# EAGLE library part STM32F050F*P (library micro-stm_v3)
ARM 32-bit Cortex™-M0 CPU 48 MHz maximum frequency 16to 32 Kbytes of Flash memory 4 kbytes of SRAM 15 GPIOs 2.0 to 3.6 V application supply

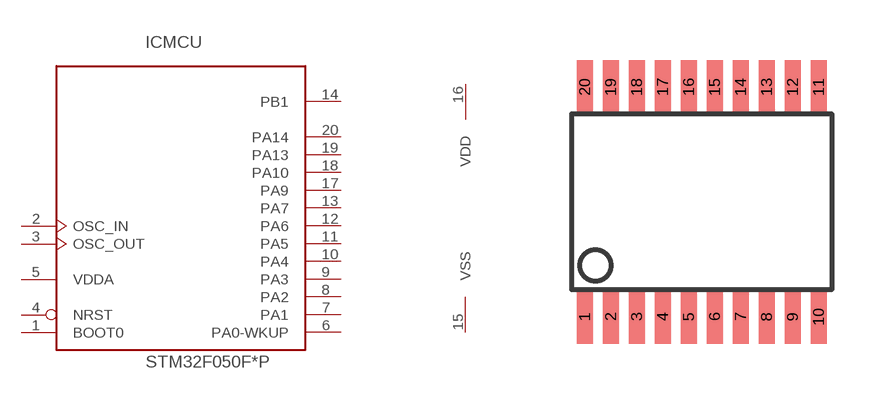
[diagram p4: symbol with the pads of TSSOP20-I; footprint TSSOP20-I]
Designator prefix IC; gates MCU=STM32_20PIN_TYP1 PWR=PWR_VDD1_VSS1

## STM32F050F4P, STM32F050F6P  [TSSOP20-I]
1  MCU:BOOT0  in
2  MCU:OSC_IN
3  MCU:OSC_OUT
4  MCU:NRST
5  MCU:VDDA  pwr
6  MCU:PA0-WKUP
7  MCU:PA1
8  MCU:PA2
9  MCU:PA3
10  MCU:PA4
11  MCU:PA5
12  MCU:PA6
13  MCU:PA7
14  MCU:PB1
15  PWR:VSS  pwr
16  PWR:VDD  pwr
17  MCU:PA9
18  MCU:PA10
19  MCU:PA13
20  MCU:PA14

## Footprint TSSOP20-I (pad centres in mm)
TSSOP20-I 20-pin thin shrink small outline package
smd 0.4 x 1.35: 1 -2.925,-2.875; 2 -2.275,-2.875; 3 -1.625,-2.875; 4 -0.975,-2.875; 5 -0.325,-2.875; 6 0.325,-2.875; 7 0.975,-2.875; 8 1.625,-2.875; 9 2.275,-2.875; 10 2.925,-2.875; 11 2.925,2.875; 12 2.275,2.875; 13 1.625,2.875; 14 0.975,2.875; 15 0.325,2.875; 16 -0.325,2.875; 17 -0.975,2.875; 18 -1.625,2.875; 19 -2.275,2.875; 20 -2.925,2.875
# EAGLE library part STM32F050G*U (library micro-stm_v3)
ARM 32-bit Cortex™-M0 CPU 48 MHz maximum frequency 16 to 32 Kbytes of Flash memory 4 kbytes of SRAM 23 GPIOs 2.0 to 3.6 V application supply

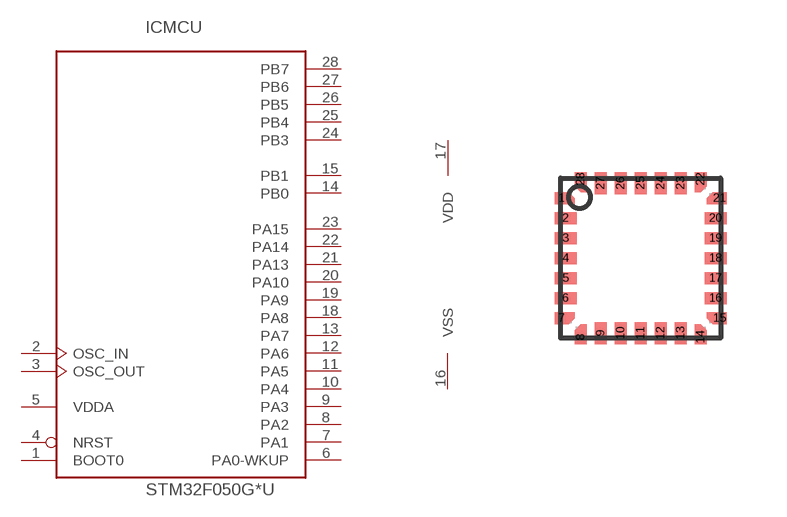
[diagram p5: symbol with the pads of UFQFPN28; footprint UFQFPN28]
Designator prefix IC; gates MCU=STM32_28PIN_TYP1 PWR=PWR_VDD1_VSS1

## STM32F050G4U, STM32F050G6U  [UFQFPN28]
1  MCU:BOOT0  in
2  MCU:OSC_IN
3  MCU:OSC_OUT
4  MCU:NRST
5  MCU:VDDA  pwr
6  MCU:PA0-WKUP
7  MCU:PA1
8  MCU:PA2
9  MCU:PA3
10  MCU:PA4
11  MCU:PA5
12  MCU:PA6
13  MCU:PA7
14  MCU:PB0
15  MCU:PB1
16  PWR:VSS  pwr
17  PWR:VDD  pwr
18  MCU:PA8
19  MCU:PA9
20  MCU:PA10
21  MCU:PA13
22  MCU:PA14
23  MCU:PA15
24  MCU:PB3
25  MCU:PB4
26  MCU:PB5
27  MCU:PB6
28  MCU:PB7

## Footprint UFQFPN28 (pad centres in mm)
UFQFPN28 4 x 4 mm, 28-pin ultra thin fine pitch quad flat no-lead package
smd 0.35 x 0.3: 1 -1.975,1.5; 7 -1.975,-1.5; 15 1.975,-1.5; 21 1.975,1.5
smd 0.55 x 0.3: 2 -1.875,1; 3 -1.875,0.5; 4 -1.875,0; 5 -1.875,-0.5; 6 -1.875,-1; 16 1.875,-1; 17 1.875,-0.5; 18 1.875,0; 19 1.875,0.5; 20 1.875,1
smd 0.3 x 0.35: 8 -1.5,-1.975; 14 1.5,-1.975; 22 1.5,1.975; 28 -1.5,1.975
smd 0.3 x 0.55: 9 -1,-1.875; 10 -0.5,-1.875; 11 0,-1.875; 12 0.5,-1.875; 13 1,-1.875; 23 1,1.875; 24 0.5,1.875; 25 0,1.875; 26 -0.5,1.875; 27 -1,1.875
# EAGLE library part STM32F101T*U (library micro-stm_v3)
ARM 32-bit Cortex™-M3 CPU 36 MHz maximum frequency 16 to 128 Kbytes of Flash memory 4 to 16 kbytes of SRAM 26 GPIOs 2.0 to 3.6 V application supply

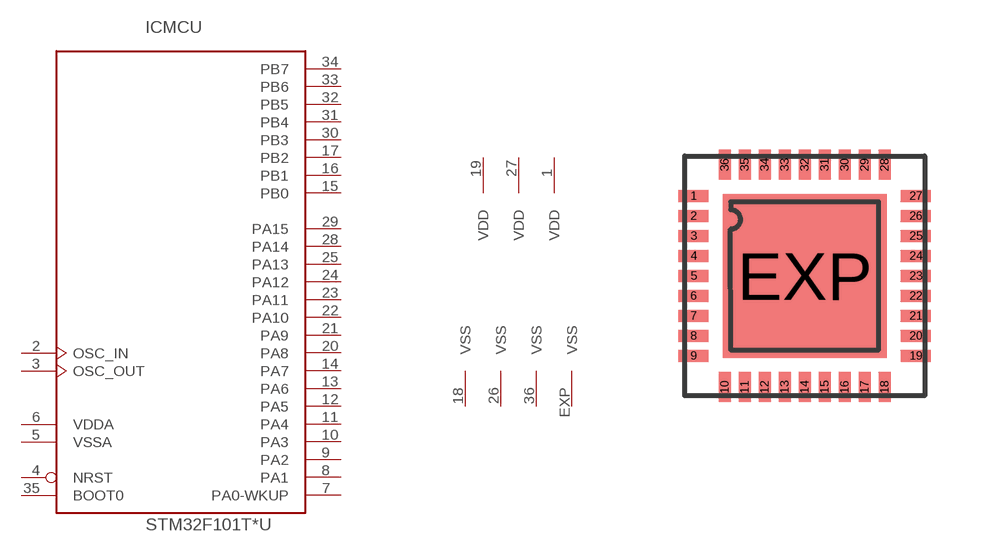
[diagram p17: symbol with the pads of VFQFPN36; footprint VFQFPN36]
Designator prefix IC; gates MCU=STM32_36PIN_TYP1 PWR=PWR_VDD3_VSS4

## STM32F101T4U, STM32F101T6U, STM32F101T8U, STM32F101TBU  [VFQFPN36]
1  PWR:VDD  pwr
2  MCU:OSC_IN
3  MCU:OSC_OUT
4  MCU:NRST
5  MCU:VSSA  pwr
6  MCU:VDDA  pwr
7  MCU:PA0-WKUP
8  MCU:PA1
9  MCU:PA2
10  MCU:PA3
11  MCU:PA4
12  MCU:PA5
13  MCU:PA6
14  MCU:PA7
15  MCU:PB0
16  MCU:PB1
17  MCU:PB2
18  PWR:VSS  pwr
19  PWR:VDD  pwr
20  MCU:PA8
21  MCU:PA9
22  MCU:PA10
23  MCU:PA11
24  MCU:PA12
25  MCU:PA13
26  PWR:VSS  pwr
27  PWR:VDD  pwr
28  MCU:PA14
29  MCU:PA15
30  MCU:PB3
31  MCU:PB4
32  MCU:PB5
33  MCU:PB6
34  MCU:PB7
35  MCU:BOOT0  in
36  PWR:VSS  pwr
EXP  PWR:VSS  pwr

## Footprint VFQFPN36 (pad centres in mm)
VFQFPN36 6 x 6 mm, 36-pin very thin 0.5 mm pitch quad flat no-lead package
smd 0.75 x 0.3: 1 -2.78,2; 2 -2.78,1.5; 3 -2.78,1; 4 -2.78,0.5; 5 -2.78,0; 6 -2.78,-0.5; 7 -2.78,-1; 8 -2.78,-1.5; 9 -2.78,-2; 19 2.78,-2; 20 2.78,-1.5; 21 2.78,-1; 22 2.78,-0.5; 23 2.78,0; 24 2.78,0.5; 25 2.78,1; 26 2.78,1.5; 27 2.78,2
smd 0.3 x 0.75: 10 -2,-2.78; 11 -1.5,-2.78; 12 -1,-2.78; 13 -0.5,-2.78; 14 0,-2.78; 15 0.5,-2.78; 16 1,-2.78; 17 1.5,-2.78; 18 2,-2.78; 28 2,2.78; 29 1.5,2.78; 30 1,2.78; 31 0.5,2.78; 32 0,2.78; 33 -0.5,2.78; 34 -1,2.78; 35 -1.5,2.78; 36 -2,2.78
smd 4.1 x 4.1: EXP 0,0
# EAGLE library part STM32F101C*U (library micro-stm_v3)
ARM 32-bit Cortex™-M3 CPU 36 MHz maximum frequency 16 to 128 Kbytes of Flash memory 4 to 16 kbytes of SRAM 37 GPIOs 2.0 to 3.6 V application supply

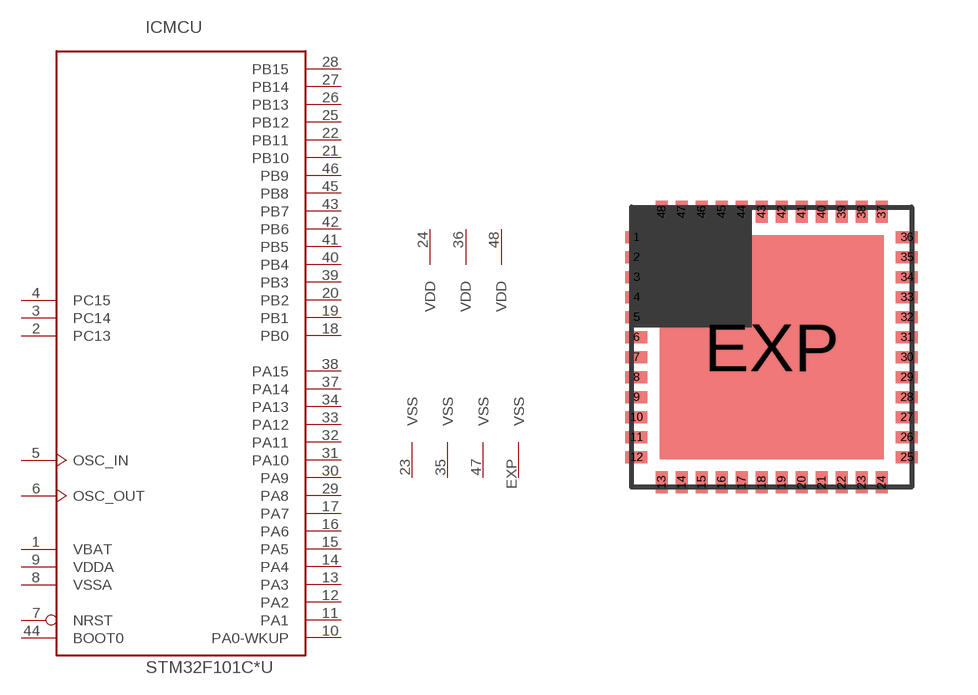
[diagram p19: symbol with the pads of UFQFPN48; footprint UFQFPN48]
Designator prefix IC; gates MCU=STM32_48PIN_TYP3 PWR=PWR_VDD3_VSS4

## STM32F101C4U, STM32F101C6U, STM32F101C8U, STM32F101CBU  [UFQFPN48]
1  MCU:VBAT  pwr
2  MCU:PC13
3  MCU:PC14
4  MCU:PC15
5  MCU:OSC_IN
6  MCU:OSC_OUT
7  MCU:NRST
8  MCU:VSSA  pwr
9  MCU:VDDA  pwr
10  MCU:PA0-WKUP
11  MCU:PA1
12  MCU:PA2
13  MCU:PA3
14  MCU:PA4
15  MCU:PA5
16  MCU:PA6
17  MCU:PA7
18  MCU:PB0
19  MCU:PB1
20  MCU:PB2
21  MCU:PB10
22  MCU:PB11
23  PWR:VSS  pwr
24  PWR:VDD  pwr
25  MCU:PB12
26  MCU:PB13
27  MCU:PB14
28  MCU:PB15
29  MCU:PA8
30  MCU:PA9
31  MCU:PA10
32  MCU:PA11
33  MCU:PA12
34  MCU:PA13
35  PWR:VSS  pwr
36  PWR:VDD  pwr
37  MCU:PA14
38  MCU:PA15
39  MCU:PB3
40  MCU:PB4
41  MCU:PB5
42  MCU:PB6
43  MCU:PB7
44  MCU:BOOT0  in
45  MCU:PB8
46  MCU:PB9
47  PWR:VSS  pwr
48  PWR:VDD  pwr
EXP  PWR:VSS  pwr

## Footprint UFQFPN48 (pad centres in mm)
UFQFPN48 7 x 7 mm, 48-pin ultra thin 0.5 mm pitch quad flat no-lead package
smd 0.55 x 0.3: 1 -3.38,2.75; 2 -3.38,2.25; 3 -3.38,1.75; 4 -3.38,1.25; 5 -3.38,0.75; 6 -3.38,0.25; 7 -3.38,-0.25; 8 -3.38,-0.75; 9 -3.38,-1.25; 10 -3.38,-1.75; 11 -3.38,-2.25; 12 -3.38,-2.75; 25 3.38,-2.75; 26 3.38,-2.25; 27 3.38,-1.75; 28 3.38,-1.25; 29 3.38,-0.75; 30 3.38,-0.25; 31 3.38,0.25; 32 3.38,0.75; 33 3.38,1.25; 34 3.38,1.75; 35 3.38,2.25; 36 3.38,2.75
smd 0.3 x 0.55: 13 -2.75,-3.38; 14 -2.25,-3.38; 15 -1.75,-3.38; 16 -1.25,-3.38; 17 -0.75,-3.38; 18 -0.25,-3.38; 19 0.25,-3.38; 20 0.75,-3.38; 21 1.25,-3.38; 22 1.75,-3.38; 23 2.25,-3.38; 24 2.75,-3.38; 37 2.75,3.38; 38 2.25,3.38; 39 1.75,3.38; 40 1.25,3.38; 41 0.75,3.38; 42 0.25,3.38; 43 -0.25,3.38; 44 -0.75,3.38; 45 -1.25,3.38; 46 -1.75,3.38; 47 -2.25,3.38; 48 -2.75,3.38
smd 5.6 x 5.6: EXP 0,0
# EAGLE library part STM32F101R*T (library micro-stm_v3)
ARM 32-bit Cortex™-M3 CPU 36 MHz maximum frequency 16 to 1024 Kbytes of Flash memory 4 to 80 kbytes of SRAM 51 GPIOs 2.0 to 3.6 V application supply

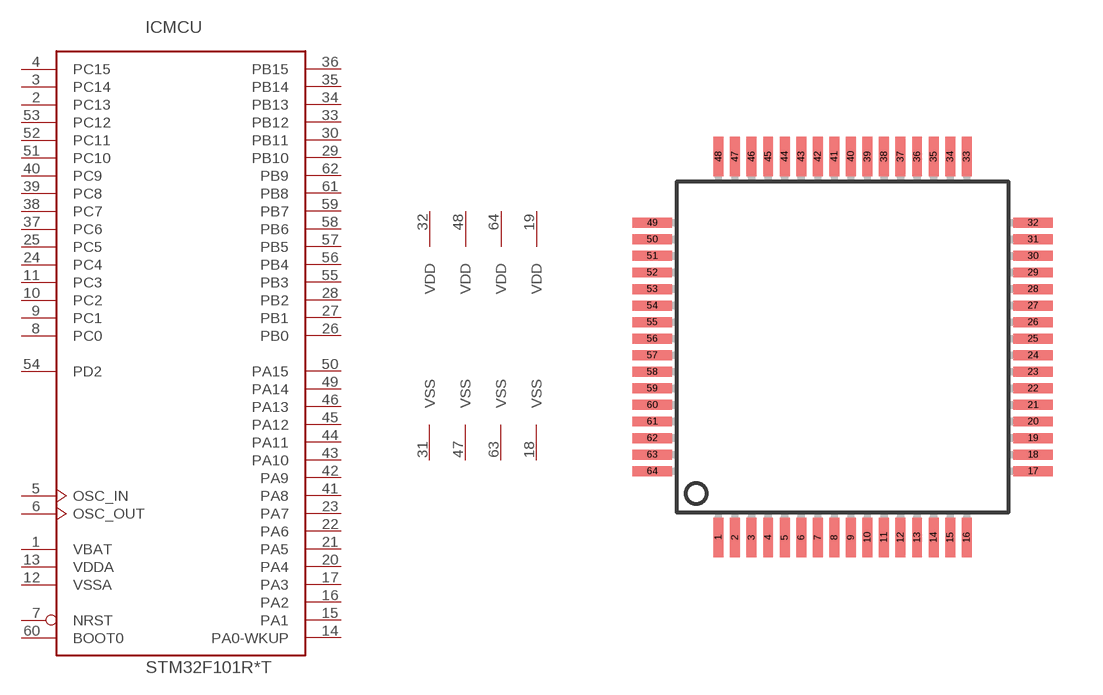
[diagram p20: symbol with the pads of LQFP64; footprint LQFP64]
Designator prefix IC; gates MCU=STM32_64PIN_TYP3 PWR=PWR_VDD4_VSS4

## STM32F101R4T, STM32F101R6T, STM32F101R8T, STM32F101RBT, STM32F101RCT, STM32F101RDT, STM32F101RET, STM32F101RFT, STM32F101RGT  [LQFP64]
1  MCU:VBAT  pwr
2  MCU:PC13
3  MCU:PC14
4  MCU:PC15
5  MCU:OSC_IN
6  MCU:OSC_OUT
7  MCU:NRST
8  MCU:PC0
9  MCU:PC1
10  MCU:PC2
11  MCU:PC3
12  MCU:VSSA  pwr
13  MCU:VDDA  pwr
14  MCU:PA0-WKUP
15  MCU:PA1
16  MCU:PA2
17  MCU:PA3
18  PWR:VSS  pwr
19  PWR:VDD  pwr
20  MCU:PA4
21  MCU:PA5
22  MCU:PA6
23  MCU:PA7
24  MCU:PC4
25  MCU:PC5
26  MCU:PB0
27  MCU:PB1
28  MCU:PB2
29  MCU:PB10
30  MCU:PB11
31  PWR:VSS  pwr
32  PWR:VDD  pwr
33  MCU:PB12
34  MCU:PB13
35  MCU:PB14
36  MCU:PB15
37  MCU:PC6
38  MCU:PC7
39  MCU:PC8
40  MCU:PC9
41  MCU:PA8
42  MCU:PA9
43  MCU:PA10
44  MCU:PA11
45  MCU:PA12
46  MCU:PA13
47  PWR:VSS  pwr
48  PWR:VDD  pwr
49  MCU:PA14
50  MCU:PA15
51  MCU:PC10
52  MCU:PC11
53  MCU:PC12
54  MCU:PD2
55  MCU:PB3
56  MCU:PB4
57  MCU:PB5
58  MCU:PB6
59  MCU:PB7
60  MCU:BOOT0  in
61  MCU:PB8
62  MCU:PB9
63  PWR:VSS  pwr
64  PWR:VDD  pwr

## Footprint LQFP64 (pad centres in mm)
LQFP64 10 x 10 mm, 64-pin low-profile quad flat package
smd 0.3 x 1.2: 1 -3.75,-5.75; 2 -3.25,-5.75; 3 -2.75,-5.75; 4 -2.25,-5.75; 5 -1.75,-5.75; 6 -1.25,-5.75; 7 -0.75,-5.75; 8 -0.25,-5.75; 9 0.25,-5.75; 10 0.75,-5.75; 11 1.25,-5.75; 12 1.75,-5.75; 13 2.25,-5.75; 14 2.75,-5.75; 15 3.25,-5.75; 16 3.75,-5.75; 33 3.75,5.75; 34 3.25,5.75; 35 2.75,5.75; 36 2.25,5.75; 37 1.75,5.75; 38 1.25,5.75; 39 0.75,5.75; 40 0.25,5.75; 41 -0.25,5.75; 42 -0.75,5.75; 43 -1.25,5.75; 44 -1.75,5.75; 45 -2.25,5.75; 46 -2.75,5.75; 47 -3.25,5.75; 48 -3.75,5.75
smd 1.2 x 0.3: 17 5.75,-3.75; 18 5.75,-3.25; 19 5.75,-2.75; 20 5.75,-2.25; 21 5.75,-1.75; 22 5.75,-1.25; 23 5.75,-0.75; 24 5.75,-0.25; 25 5.75,0.25; 26 5.75,0.75; 27 5.75,1.25; 28 5.75,1.75; 29 5.75,2.25; 30 5.75,2.75; 31 5.75,3.25; 32 5.75,3.75; 49 -5.75,3.75; 50 -5.75,3.25; 51 -5.75,2.75; 52 -5.75,2.25; 53 -5.75,1.75; 54 -5.75,1.25; 55 -5.75,0.75; 56 -5.75,0.25; 57 -5.75,-0.25; 58 -5.75,-0.75; 59 -5.75,-1.25; 60 -5.75,-1.75; 61 -5.75,-2.25; 62 -5.75,-2.75; 63 -5.75,-3.25; 64 -5.75,-3.75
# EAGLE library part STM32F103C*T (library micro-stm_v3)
ARM 32-bit Cortex™-M3 CPU 72 MHz maximum frequency 16 to 128 Kbytes of Flash memory 6 to 20 kbytes of SRAM 37 GPIOs 2.0 to 3.6 V application supply

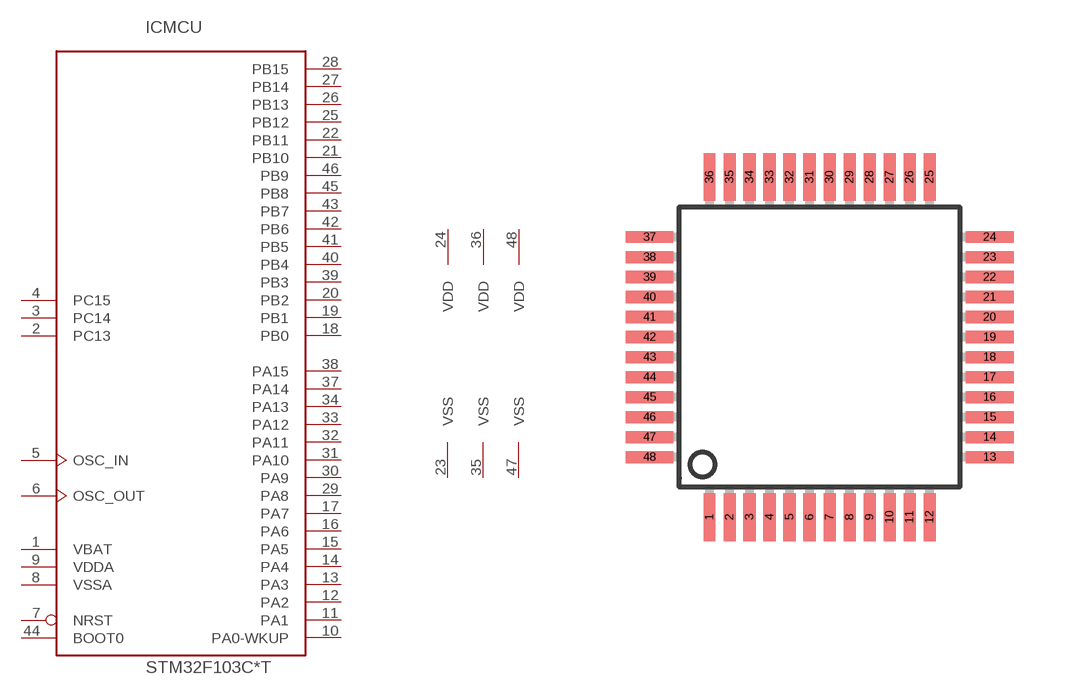
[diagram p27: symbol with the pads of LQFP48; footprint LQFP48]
Designator prefix IC; gates MCU=STM32_48PIN_TYP3 PWR=PWR_VDD3_VSS3

## STM32F103C4T, STM32F103C6T, STM32F103C8T, STM32F103CBT  [LQFP48]
1  MCU:VBAT  pwr
2  MCU:PC13
3  MCU:PC14
4  MCU:PC15
5  MCU:OSC_IN
6  MCU:OSC_OUT
7  MCU:NRST
8  MCU:VSSA  pwr
9  MCU:VDDA  pwr
10  MCU:PA0-WKUP
11  MCU:PA1
12  MCU:PA2
13  MCU:PA3
14  MCU:PA4
15  MCU:PA5
16  MCU:PA6
17  MCU:PA7
18  MCU:PB0
19  MCU:PB1
20  MCU:PB2
21  MCU:PB10
22  MCU:PB11
23  PWR:VSS  pwr
24  PWR:VDD  pwr
25  MCU:PB12
26  MCU:PB13
27  MCU:PB14
28  MCU:PB15
29  MCU:PA8
30  MCU:PA9
31  MCU:PA10
32  MCU:PA11
33  MCU:PA12
34  MCU:PA13
35  PWR:VSS  pwr
36  PWR:VDD  pwr
37  MCU:PA14
38  MCU:PA15
39  MCU:PB3
40  MCU:PB4
41  MCU:PB5
42  MCU:PB6
43  MCU:PB7
44  MCU:BOOT0  in
45  MCU:PB8
46  MCU:PB9
47  PWR:VSS  pwr
48  PWR:VDD  pwr

## Footprint LQFP48 (pad centres in mm)
LQFP48 7 x 7 mm, 48-pin low-profile quad flat package
smd 0.3 x 1.2: 1 -2.75,-4.25; 2 -2.25,-4.25; 3 -1.75,-4.25; 4 -1.25,-4.25; 5 -0.75,-4.25; 6 -0.25,-4.25; 7 0.25,-4.25; 8 0.75,-4.25; 9 1.25,-4.25; 10 1.75,-4.25; 11 2.25,-4.25; 12 2.75,-4.25; 25 2.75,4.25; 26 2.25,4.25; 27 1.75,4.25; 28 1.25,4.25; 29 0.75,4.25; 30 0.25,4.25; 31 -0.25,4.25; 32 -0.75,4.25; 33 -1.25,4.25; 34 -1.75,4.25; 35 -2.25,4.25; 36 -2.75,4.25
smd 1.2 x 0.3: 13 4.25,-2.75; 14 4.25,-2.25; 15 4.25,-1.75; 16 4.25,-1.25; 17 4.25,-0.75; 18 4.25,-0.25; 19 4.25,0.25; 20 4.25,0.75; 21 4.25,1.25; 22 4.25,1.75; 23 4.25,2.25; 24 4.25,2.75; 37 -4.25,2.75; 38 -4.25,2.25; 39 -4.25,1.75; 40 -4.25,1.25; 41 -4.25,0.75; 42 -4.25,0.25; 43 -4.25,-0.25; 44 -4.25,-0.75; 45 -4.25,-1.25; 46 -4.25,-1.75; 47 -4.25,-2.25; 48 -4.25,-2.75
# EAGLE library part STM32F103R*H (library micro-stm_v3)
ARM 32-bit Cortex™-M3 CPU 72 MHz maximum frequency 16 to 128 Kbytes of Flash memory 6 to 20 kbytes of SRAM 51 GPIOs 2.0 to 3.6 V application supply

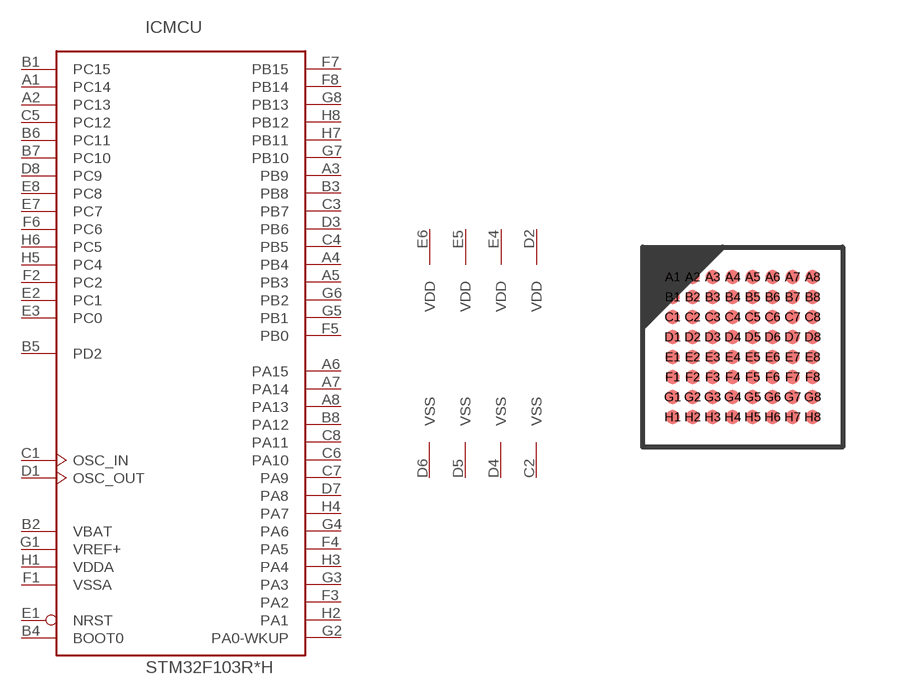
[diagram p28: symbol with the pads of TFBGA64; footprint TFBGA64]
Designator prefix IC; gates MCU=STM32_64PIN_TYP4 PWR=PWR_VDD4_VSS4

## STM32F103R4H, STM32F103R6H, STM32F103R8H, STM32F103RBH  [TFBGA64]
A1  MCU:PC14
A2  MCU:PC13
A3  MCU:PB9
A4  MCU:PB4
A5  MCU:PB3
A6  MCU:PA15
A7  MCU:PA14
A8  MCU:PA13
B1  MCU:PC15
B2  MCU:VBAT  pwr
B3  MCU:PB8
B4  MCU:BOOT0  in
B5  MCU:PD2
B6  MCU:PC11
B7  MCU:PC10
B8  MCU:PA12
C1  MCU:OSC_IN
C2  PWR:VSS  pwr
C3  MCU:PB7
C4  MCU:PB5
C5  MCU:PC12
C6  MCU:PA10
C7  MCU:PA9
C8  MCU:PA11
D1  MCU:OSC_OUT
D2  PWR:VDD  pwr
D3  MCU:PB6
D4  PWR:VSS  pwr
D5  PWR:VSS  pwr
D6  PWR:VSS  pwr
D7  MCU:PA8
D8  MCU:PC9
E1  MCU:NRST
E2  MCU:PC1
E3  MCU:PC0
E4  PWR:VDD  pwr
E5  PWR:VDD  pwr
E6  PWR:VDD  pwr
E7  MCU:PC7
E8  MCU:PC8
F1  MCU:VSSA  pwr
F2  MCU:PC2
F3  MCU:PA2
F4  MCU:PA5
F5  MCU:PB0
F6  MCU:PC6
F7  MCU:PB15
F8  MCU:PB14
G1  MCU:VREF+  pwr
G2  MCU:PA0-WKUP
G3  MCU:PA3
G4  MCU:PA6
G5  MCU:PB1
G6  MCU:PB2
G7  MCU:PB10
G8  MCU:PB13
H1  MCU:VDDA  pwr
H2  MCU:PA1
H3  MCU:PA4
H4  MCU:PA7
H5  MCU:PC4
H6  MCU:PC5
H7  MCU:PB11
H8  MCU:PB12

## Footprint TFBGA64 (pad centres in mm)
TFBGA64 5 x 5 mm, 8 x 8-pin thin 0.5 mm pitch ball grid array package
smd 0.35 x 0.35: A1 -1.75,1.75; A2 -1.25,1.75; A3 -0.75,1.75; A4 -0.25,1.75; A5 0.25,1.75; A6 0.75,1.75; A7 1.25,1.75; A8 1.75,1.75; B1 -1.75,1.25; B2 -1.25,1.25; B3 -0.75,1.25; B4 -0.25,1.25; B5 0.25,1.25; B6 0.75,1.25; B7 1.25,1.25; B8 1.75,1.25; C1 -1.75,0.75; C2 -1.25,0.75; C3 -0.75,0.75; C4 -0.25,0.75; C5 0.25,0.75; C6 0.75,0.75; C7 1.25,0.75; C8 1.75,0.75; D1 -1.75,0.25; D2 -1.25,0.25; D3 -0.75,0.25; D4 -0.25,0.25; D5 0.25,0.25; D6 0.75,0.25; D7 1.25,0.25; D8 1.75,0.25; E1 -1.75,-0.25; E2 -1.25,-0.25; E3 -0.75,-0.25; E4 -0.25,-0.25; E5 0.25,-0.25; E6 0.75,-0.25; E7 1.25,-0.25; E8 1.75,-0.25; F1 -1.75,-0.75; F2 -1.25,-0.75; F3 -0.75,-0.75; F4 -0.25,-0.75; F5 0.25,-0.75; F6 0.75,-0.75; F7 1.25,-0.75; F8 1.75,-0.75; G1 -1.75,-1.25; G2 -1.25,-1.25; G3 -0.75,-1.25; G4 -0.25,-1.25; G5 0.25,-1.25; G6 0.75,-1.25; G7 1.25,-1.25; G8 1.75,-1.25; H1 -1.75,-1.75; H2 -1.25,-1.75; H3 -0.75,-1.75; H4 -0.25,-1.75; H5 0.25,-1.75; H6 0.75,-1.75; H7 1.25,-1.75; H8 1.75,-1.75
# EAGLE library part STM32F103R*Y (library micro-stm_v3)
ARM 32-bit Cortex™-M3 CPU 72 MHz maximum frequency 256 to 512 Kbytes of Flash memory 64 kbytes of SRAM 51 GPIOs 2.0 to 3.6 V application supply

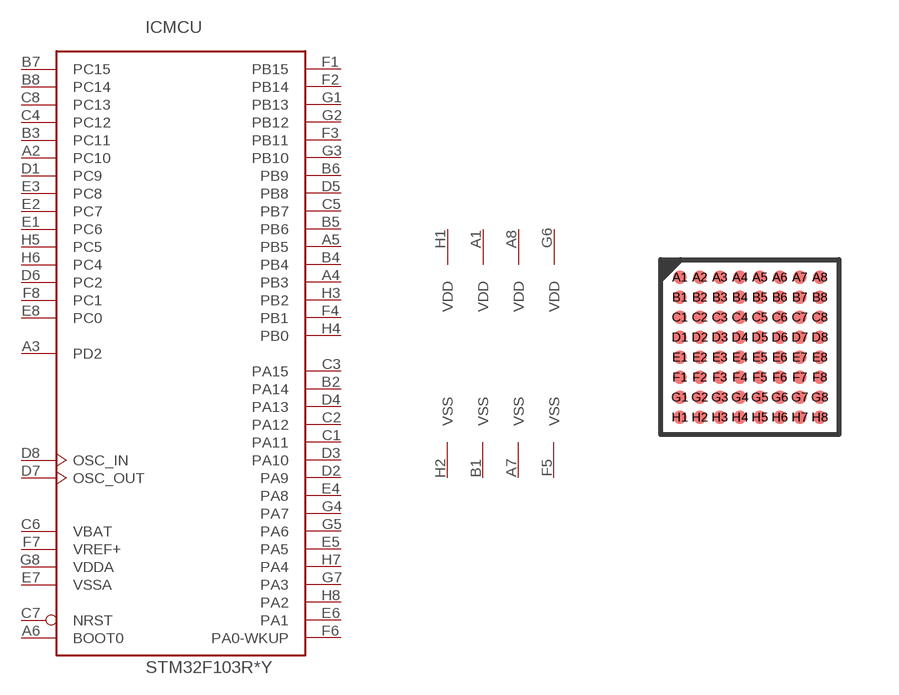
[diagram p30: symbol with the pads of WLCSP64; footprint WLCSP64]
Designator prefix IC; gates MCU=STM32_64PIN_TYP4 PWR=PWR_VDD4_VSS4

## STM32F103RCY, STM32F103RDY, STM32F103REY  [WLCSP64]
A1  PWR:VDD  pwr
A2  MCU:PC10
A3  MCU:PD2
A4  MCU:PB3
A5  MCU:PB5
A6  MCU:BOOT0  in
A7  PWR:VSS  pwr
A8  PWR:VDD  pwr
B1  PWR:VSS  pwr
B2  MCU:PA14
B3  MCU:PC11
B4  MCU:PB4
B5  MCU:PB6
B6  MCU:PB9
B7  MCU:PC15
B8  MCU:PC14
C1  MCU:PA11
C2  MCU:PA12
C3  MCU:PA15
C4  MCU:PC12
C5  MCU:PB7
C6  MCU:VBAT  pwr
C7  MCU:NRST
C8  MCU:PC13
D1  MCU:PC9
D2  MCU:PA9
D3  MCU:PA10
D4  MCU:PA13
D5  MCU:PB8
D6  MCU:PC2
D7  MCU:OSC_OUT
D8  MCU:OSC_IN
E1  MCU:PC6
E2  MCU:PC7
E3  MCU:PC8
E4  MCU:PA8
E5  MCU:PA5
E6  MCU:PA1
E7  MCU:VSSA  pwr
E8  MCU:PC0
F1  MCU:PB15
F2  MCU:PB14
F3  MCU:PB11
F4  MCU:PB1
F5  PWR:VSS  pwr
F6  MCU:PA0-WKUP
F7  MCU:VREF+  pwr
F8  MCU:PC1
G1  MCU:PB13
G2  MCU:PB12
G3  MCU:PB10
G4  MCU:PA7
G5  MCU:PA6
G6  PWR:VDD  pwr
G7  MCU:PA3
G8  MCU:VDDA  pwr
H1  PWR:VDD  pwr
H2  PWR:VSS  pwr
H3  MCU:PB2
H4  MCU:PB0
H5  MCU:PC5
H6  MCU:PC4
H7  MCU:PA4
H8  MCU:PA2

## Footprint WLCSP64 (pad centres in mm)
WLCSP64 4.466 x 4.395 mm, 8 x 8-pin 0.5 mm pitch wafer-level chip-scale package
smd 0.34 x 0.34: A1 -1.75,1.75; A2 -1.25,1.75; A3 -0.75,1.75; A4 -0.25,1.75; A5 0.25,1.75; A6 0.75,1.75; A7 1.25,1.75; A8 1.75,1.75; B1 -1.75,1.25; B2 -1.25,1.25; B3 -0.75,1.25; B4 -0.25,1.25; B5 0.25,1.25; B6 0.75,1.25; B7 1.25,1.25; B8 1.75,1.25; C1 -1.75,0.75; C2 -1.25,0.75; C3 -0.75,0.75; C4 -0.25,0.75; C5 0.25,0.75; C6 0.75,0.75; C7 1.25,0.75; C8 1.75,0.75; D1 -1.75,0.25; D2 -1.25,0.25; D3 -0.75,0.25; D4 -0.25,0.25; D5 0.25,0.25; D6 0.75,0.25; D7 1.25,0.25; D8 1.75,0.25; E1 -1.75,-0.25; E2 -1.25,-0.25; E3 -0.75,-0.25; E4 -0.25,-0.25; E5 0.25,-0.25; E6 0.75,-0.25; E7 1.25,-0.25; E8 1.75,-0.25; F1 -1.75,-0.75; F2 -1.25,-0.75; F3 -0.75,-0.75; F4 -0.25,-0.75; F5 0.25,-0.75; F6 0.75,-0.75; F7 1.25,-0.75; F8 1.75,-0.75; G1 -1.75,-1.25; G2 -1.25,-1.25; G3 -0.75,-1.25; G4 -0.25,-1.25; G5 0.25,-1.25; G6 0.75,-1.25; G7 1.25,-1.25; G8 1.75,-1.25; H1 -1.75,-1.75; H2 -1.25,-1.75; H3 -0.75,-1.75; H4 -0.25,-1.75; H5 0.25,-1.75; H6 0.75,-1.75; H7 1.25,-1.75; H8 1.75,-1.75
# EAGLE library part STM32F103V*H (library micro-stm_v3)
ARM 32-bit Cortex™-M3 CPU 72 MHz maximum frequency 64 to 512 Kbytes of Flash memory 20 to 64 kbytes of SRAM 80 GPIOs 2.0 to 3.6 V application supply

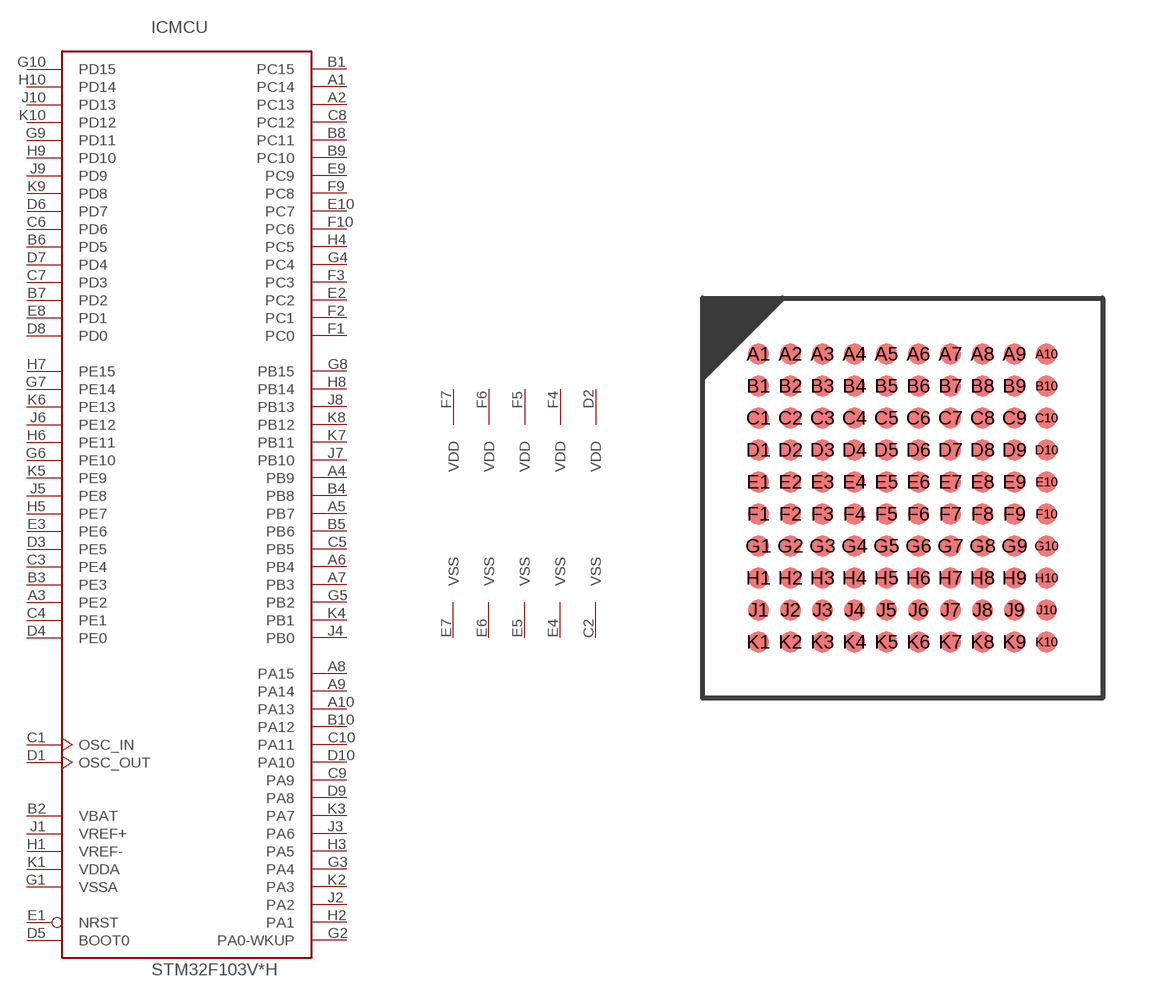
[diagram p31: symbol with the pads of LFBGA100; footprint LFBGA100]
Designator prefix IC; gates MCU=STM32_100PIN_TYP1 PWR=PWR_VDD5_VSS5

## STM32F103V8H, STM32F103VBH, STM32F103VCH, STM32F103VDH, STM32F103VEH  [LFBGA100]
A1  MCU:PC14
A2  MCU:PC13
A3  MCU:PE2
A4  MCU:PB9
A5  MCU:PB7
A6  MCU:PB4
A7  MCU:PB3
A8  MCU:PA15
A9  MCU:PA14
A10  MCU:PA13
B1  MCU:PC15
B2  MCU:VBAT  pwr
B3  MCU:PE3
B4  MCU:PB8
B5  MCU:PB6
B6  MCU:PD5
B7  MCU:PD2
B8  MCU:PC11
B9  MCU:PC10
B10  MCU:PA12
C1  MCU:OSC_IN
C2  PWR:VSS  pwr
C3  MCU:PE4
C4  MCU:PE1
C5  MCU:PB5
C6  MCU:PD6
C7  MCU:PD3
C8  MCU:PC12
C9  MCU:PA9
C10  MCU:PA11
D1  MCU:OSC_OUT
D2  PWR:VDD  pwr
D3  MCU:PE5
D4  MCU:PE0
D5  MCU:BOOT0  in
D6  MCU:PD7
D7  MCU:PD4
D8  MCU:PD0
D9  MCU:PA8
D10  MCU:PA10
E1  MCU:NRST
E2  MCU:PC2
E3  MCU:PE6
E4  PWR:VSS  pwr
E5  PWR:VSS  pwr
E6  PWR:VSS  pwr
E7  PWR:VSS  pwr
E8  MCU:PD1
E9  MCU:PC9
E10  MCU:PC7
F1  MCU:PC0
F2  MCU:PC1
F3  MCU:PC3
F4  PWR:VDD  pwr
F5  PWR:VDD  pwr
F6  PWR:VDD  pwr
F7  PWR:VDD  pwr
F9  MCU:PC8
F10  MCU:PC6
G1  MCU:VSSA  pwr
G2  MCU:PA0-WKUP
G3  MCU:PA4
G4  MCU:PC4
G5  MCU:PB2
G6  MCU:PE10
G7  MCU:PE14
G8  MCU:PB15
G9  MCU:PD11
G10  MCU:PD15
H1  MCU:VREF-  pwr
H2  MCU:PA1
H3  MCU:PA5
H4  MCU:PC5
H5  MCU:PE7
H6  MCU:PE11
H7  MCU:PE15
H8  MCU:PB14
H9  MCU:PD10
H10  MCU:PD14
J1  MCU:VREF+  pwr
J2  MCU:PA2
J3  MCU:PA6
J4  MCU:PB0
J5  MCU:PE8
J6  MCU:PE12
J7  MCU:PB10
J8  MCU:PB13
J9  MCU:PD9
J10  MCU:PD13
K1  MCU:VDDA  pwr
K2  MCU:PA3
K3  MCU:PA7
K4  MCU:PB1
K5  MCU:PE9
K6  MCU:PE13
K7  MCU:PB11
K8  MCU:PB12
K9  MCU:PD8
K10  MCU:PD12

## Footprint LFBGA100 (pad centres in mm)
LFBGA100 10 x 10 mm, 10 x 10-pin low profil 0.8 mm pitch ball grid array package
smd 0.52 x 0.52: A1 -3.6,3.6; A2 -2.8,3.6; A3 -2,3.6; A4 -1.2,3.6; A5 -0.4,3.6; A6 0.4,3.6; A7 1.2,3.6; A8 2,3.6; A9 2.8,3.6; A10 3.6,3.6; B1 -3.6,2.8; B2 -2.8,2.8; B3 -2,2.8; B4 -1.2,2.8; B5 -0.4,2.8; B6 0.4,2.8; B7 1.2,2.8; B8 2,2.8; B9 2.8,2.8; B10 3.6,2.8; C1 -3.6,2; C2 -2.8,2; C3 -2,2; C4 -1.2,2; C5 -0.4,2; C6 0.4,2; C7 1.2,2; C8 2,2; C9 2.8,2; C10 3.6,2; D1 -3.6,1.2; D2 -2.8,1.2; D3 -2,1.2; D4 -1.2,1.2; D5 -0.4,1.2; D6 0.4,1.2; D7 1.2,1.2; D8 2,1.2; D9 2.8,1.2; D10 3.6,1.2; E1 -3.6,0.4; E2 -2.8,0.4; E3 -2,0.4; E4 -1.2,0.4; E5 -0.4,0.4; E6 0.4,0.4; E7 1.2,0.4; E8 2,0.4; E9 2.8,0.4; E10 3.6,0.4; F1 -3.6,-0.4; F2 -2.8,-0.4; F3 -2,-0.4; F4 -1.2,-0.4; F5 -0.4,-0.4; F6 0.4,-0.4; F7 1.2,-0.4; F8 2,-0.4; F9 2.8,-0.4; F10 3.6,-0.4; G1 -3.6,-1.2; G2 -2.8,-1.2; G3 -2,-1.2; G4 -1.2,-1.2; G5 -0.4,-1.2; G6 0.4,-1.2; G7 1.2,-1.2; G8 2,-1.2; G9 2.8,-1.2; G10 3.6,-1.2; H1 -3.6,-2; H2 -2.8,-2; H3 -2,-2; H4 -1.2,-2; H5 -0.4,-2; H6 0.4,-2; H7 1.2,-2; H8 2,-2; H9 2.8,-2; H10 3.6,-2; J1 -3.6,-2.8; J2 -2.8,-2.8; J3 -2,-2.8; J4 -1.2,-2.8; J5 -0.4,-2.8; J6 0.4,-2.8; J7 1.2,-2.8; J8 2,-2.8; J9 2.8,-2.8; J10 3.6,-2.8; K1 -3.6,-3.6; K2 -2.8,-3.6; K3 -2,-3.6; K4 -1.2,-3.6; K5 -0.4,-3.6; K6 0.4,-3.6; K7 1.2,-3.6; K8 2,-3.6; K9 2.8,-3.6; K10 3.6,-3.6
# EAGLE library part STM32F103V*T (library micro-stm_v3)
ARM 32-bit Cortex™-M3 CPU 72 MHz maximum frequency 64 to 1028 Kbytes of Flash memory 20 to 96 kbytes of SRAM 80 GPIOs 2.0 to 3.6 V application supply

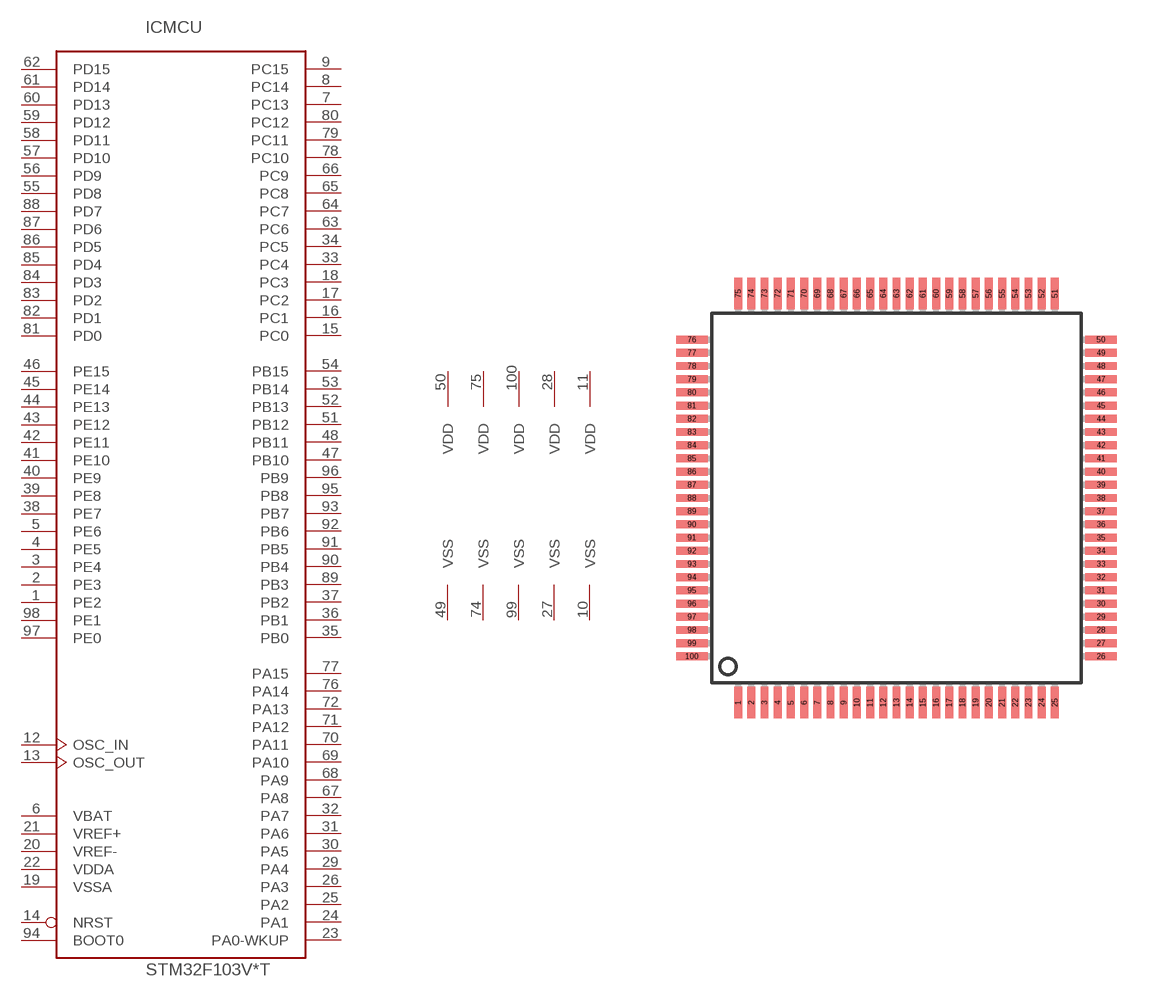
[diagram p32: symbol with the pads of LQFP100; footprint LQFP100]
Designator prefix IC; gates MCU=STM32_100PIN_TYP1 PWR=PWR_VDD5_VSS5

## STM32F103V8T, STM32F103VBT, STM32F103VCT, STM32F103VDT, STM32F103VET, STM32F103VFT, STM32F103VGT  [LQFP100]
1  MCU:PE2
2  MCU:PE3
3  MCU:PE4
4  MCU:PE5
5  MCU:PE6
6  MCU:VBAT  pwr
7  MCU:PC13
8  MCU:PC14
9  MCU:PC15
10  PWR:VSS  pwr
11  PWR:VDD  pwr
12  MCU:OSC_IN
13  MCU:OSC_OUT
14  MCU:NRST
15  MCU:PC0
16  MCU:PC1
17  MCU:PC2
18  MCU:PC3
19  MCU:VSSA  pwr
20  MCU:VREF-  pwr
21  MCU:VREF+  pwr
22  MCU:VDDA  pwr
23  MCU:PA0-WKUP
24  MCU:PA1
25  MCU:PA2
26  MCU:PA3
27  PWR:VSS  pwr
28  PWR:VDD  pwr
29  MCU:PA4
30  MCU:PA5
31  MCU:PA6
32  MCU:PA7
33  MCU:PC4
34  MCU:PC5
35  MCU:PB0
36  MCU:PB1
37  MCU:PB2
38  MCU:PE7
39  MCU:PE8
40  MCU:PE9
41  MCU:PE10
42  MCU:PE11
43  MCU:PE12
44  MCU:PE13
45  MCU:PE14
46  MCU:PE15
47  MCU:PB10
48  MCU:PB11
49  PWR:VSS  pwr
50  PWR:VDD  pwr
51  MCU:PB12
52  MCU:PB13
53  MCU:PB14
54  MCU:PB15
55  MCU:PD8
56  MCU:PD9
57  MCU:PD10
58  MCU:PD11
59  MCU:PD12
60  MCU:PD13
61  MCU:PD14
62  MCU:PD15
63  MCU:PC6
64  MCU:PC7
65  MCU:PC8
66  MCU:PC9
67  MCU:PA8
68  MCU:PA9
69  MCU:PA10
70  MCU:PA11
71  MCU:PA12
72  MCU:PA13
74  PWR:VSS  pwr
75  PWR:VDD  pwr
76  MCU:PA14
77  MCU:PA15
78  MCU:PC10
79  MCU:PC11
80  MCU:PC12
81  MCU:PD0
82  MCU:PD1
83  MCU:PD2
84  MCU:PD3
85  MCU:PD4
86  MCU:PD5
87  MCU:PD6
88  MCU:PD7
89  MCU:PB3
90  MCU:PB4
91  MCU:PB5
92  MCU:PB6
93  MCU:PB7
94  MCU:BOOT0  in
95  MCU:PB8
96  MCU:PB9
97  MCU:PE0
98  MCU:PE1
99  PWR:VSS  pwr
100  PWR:VDD  pwr

## Footprint LQFP100 (pad centres in mm)
LQFP100 14 x 14 mm, 100-pin low-profile quad flat package
smd 0.3 x 1.2: 1 -6,-7.75; 2 -5.5,-7.75; 3 -5,-7.75; 4 -4.5,-7.75; 5 -4,-7.75; 6 -3.5,-7.75; 7 -3,-7.75; 8 -2.5,-7.75; 9 -2,-7.75; 10 -1.5,-7.75; 11 -1,-7.75; 12 -0.5,-7.75; 13 0,-7.75; 14 0.5,-7.75; 15 1,-7.75; 16 1.5,-7.75; 17 2,-7.75; 18 2.5,-7.75; 19 3,-7.75; 20 3.5,-7.75; 21 4,-7.75; 22 4.5,-7.75; 23 5,-7.75; 24 5.5,-7.75; 25 6,-7.75; 51 6,7.75; 52 5.5,7.75; 53 5,7.75; 54 4.5,7.75; 55 4,7.75; 56 3.5,7.75; 57 3,7.75; 58 2.5,7.75; 59 2,7.75; 60 1.5,7.75; 61 1,7.75; 62 0.5,7.75; 63 0,7.75; 64 -0.5,7.75; 65 -1,7.75; 66 -1.5,7.75; 67 -2,7.75; 68 -2.5,7.75; 69 -3,7.75; 70 -3.5,7.75; 71 -4,7.75; 72 -4.5,7.75; 73 -5,7.75; 74 -5.5,7.75; 75 -6,7.75
smd 1.2 x 0.3: 26 7.75,-6; 27 7.75,-5.5; 28 7.75,-5; 29 7.75,-4.5; 30 7.75,-4; 31 7.75,-3.5; 32 7.75,-3; 33 7.75,-2.5; 34 7.75,-2; 35 7.75,-1.5; 36 7.75,-1; 37 7.75,-0.5; 38 7.75,0; 39 7.75,0.5; 40 7.75,1; 41 7.75,1.5; 42 7.75,2; 43 7.75,2.5; 44 7.75,3; 45 7.75,3.5; 46 7.75,4; 47 7.75,4.5; 48 7.75,5; 49 7.75,5.5; 50 7.75,6; 76 -7.75,6; 77 -7.75,5.5; 78 -7.75,5; 79 -7.75,4.5; 80 -7.75,4; 81 -7.75,3.5; 82 -7.75,3; 83 -7.75,2.5; 84 -7.75,2; 85 -7.75,1.5; 86 -7.75,1; 87 -7.75,0.5; 88 -7.75,0; 89 -7.75,-0.5; 90 -7.75,-1; 91 -7.75,-1.5; 92 -7.75,-2; 93 -7.75,-2.5; 94 -7.75,-3; 95 -7.75,-3.5; 96 -7.75,-4; 97 -7.75,-4.5; 98 -7.75,-5; 99 -7.75,-5.5; 100 -7.75,-6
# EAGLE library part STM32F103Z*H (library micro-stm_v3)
ARM 32-bit Cortex™-M3 CPU 72 MHz maximum frequency 256 to 1024 Kbytes of Flash memory 48 to 96 kbytes of SRAM 112 GPIOs 2.0 to 3.6 V application supply

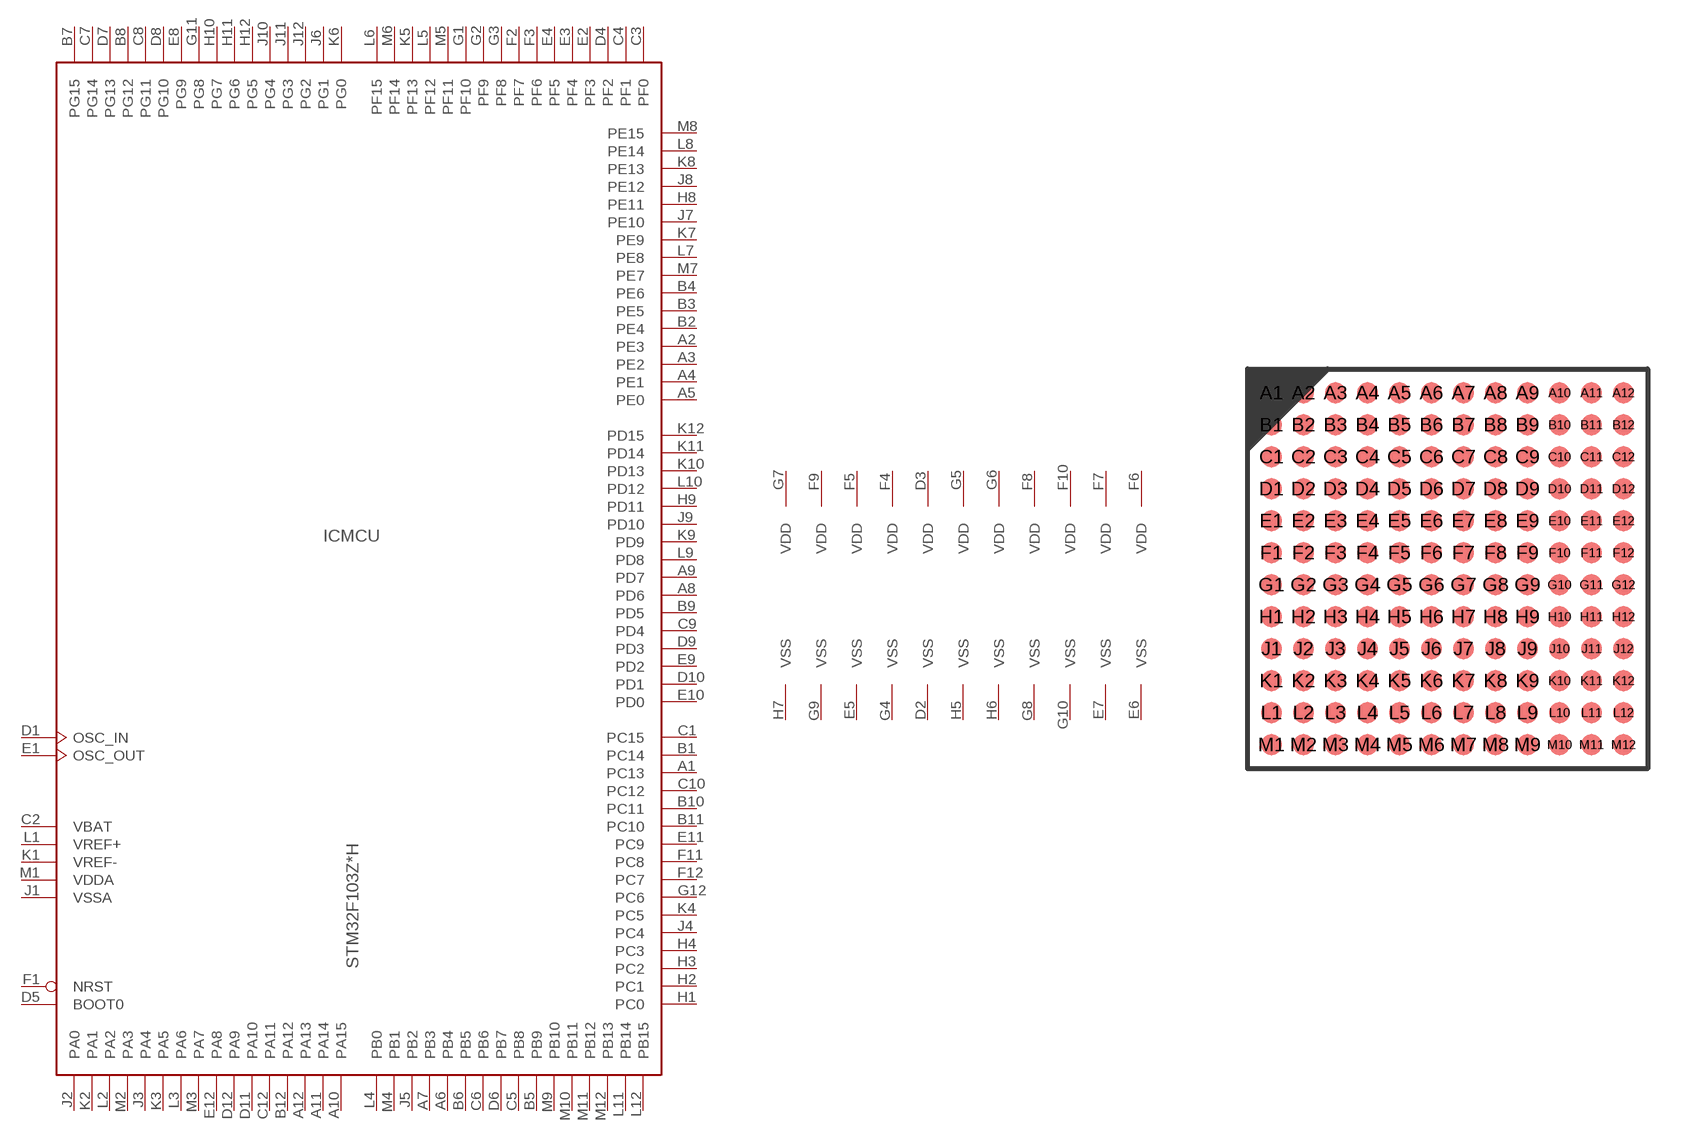
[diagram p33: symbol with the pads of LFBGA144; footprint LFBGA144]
Designator prefix IC; gates MCU=STM32_144PIN_TYP1 PWR=PWR_VDD11_VSS11

## STM32F103ZCH, STM32F103ZDH, STM32F103ZEH, STM32F103ZFH, STM32F103ZGH  [LFBGA144]
A1  MCU:PC13
A2  MCU:PE3
A3  MCU:PE2
A4  MCU:PE1
A5  MCU:PE0
A6  MCU:PB4
A7  MCU:PB3
A8  MCU:PD6
A9  MCU:PD7
A10  MCU:PA15
A11  MCU:PA14
A12  MCU:PA13
B1  MCU:PC14
B2  MCU:PE4
B3  MCU:PE5
B4  MCU:PE6
B5  MCU:PB9
B6  MCU:PB5
B7  MCU:PG15
B8  MCU:PG12
B9  MCU:PD5
B10  MCU:PC11
B11  MCU:PC10
B12  MCU:PA12
C1  MCU:PC15
C2  MCU:VBAT  pwr
C3  MCU:PF0
C4  MCU:PF1
C5  MCU:PB8
C6  MCU:PB6
C7  MCU:PG14
C8  MCU:PG11
C9  MCU:PD4
C10  MCU:PC12
C12  MCU:PA11
D1  MCU:OSC_IN
D2  PWR:VSS  pwr
D3  PWR:VDD  pwr
D4  MCU:PF2
D5  MCU:BOOT0  in
D6  MCU:PB7
D7  MCU:PG13
D8  MCU:PG10
D9  MCU:PD3
D10  MCU:PD1
D11  MCU:PA10
D12  MCU:PA9
E1  MCU:OSC_OUT
E2  MCU:PF3
E3  MCU:PF4
E4  MCU:PF5
E5  PWR:VSS  pwr
E6  PWR:VSS  pwr
E7  PWR:VSS  pwr
E8  MCU:PG9
E9  MCU:PD2
E10  MCU:PD0
E11  MCU:PC9
E12  MCU:PA8
F1  MCU:NRST
F2  MCU:PF7
F3  MCU:PF6
F4  PWR:VDD  pwr
F5  PWR:VDD  pwr
F6  PWR:VDD  pwr
F7  PWR:VDD  pwr
F8  PWR:VDD  pwr
F9  PWR:VDD  pwr
F10  PWR:VDD  pwr
F11  MCU:PC8
F12  MCU:PC7
G1  MCU:PF10
G2  MCU:PF9
G3  MCU:PF8
G4  PWR:VSS  pwr
G5  PWR:VDD  pwr
G6  PWR:VDD  pwr
G7  PWR:VDD  pwr
G8  PWR:VSS  pwr
G9  PWR:VSS  pwr
G10  PWR:VSS  pwr
G11  MCU:PG8
G12  MCU:PC6
H1  MCU:PC0
H2  MCU:PC1
H3  MCU:PC2
H4  MCU:PC3
H5  PWR:VSS  pwr
H6  PWR:VSS  pwr
H7  PWR:VSS  pwr
H8  MCU:PE11
H9  MCU:PD11
H10  MCU:PG7
H11  MCU:PG6
H12  MCU:PG5
J1  MCU:VSSA  pwr
J2  MCU:PA0
J3  MCU:PA4
J4  MCU:PC4
J5  MCU:PB2
J6  MCU:PG1
J7  MCU:PE10
J8  MCU:PE12
J9  MCU:PD10
J10  MCU:PG4
J11  MCU:PG3
J12  MCU:PG2
K1  MCU:VREF-  pwr
K2  MCU:PA1
K3  MCU:PA5
K4  MCU:PC5
K5  MCU:PF13
K6  MCU:PG0
K7  MCU:PE9
K8  MCU:PE13
K9  MCU:PD9
K10  MCU:PD13
K11  MCU:PD14
K12  MCU:PD15
L1  MCU:VREF+  pwr
L2  MCU:PA2
L3  MCU:PA6
L4  MCU:PB0
L5  MCU:PF12
L6  MCU:PF15
L7  MCU:PE8
L8  MCU:PE14
L9  MCU:PD8
L10  MCU:PD12
L11  MCU:PB14
L12  MCU:PB15
M1  MCU:VDDA  pwr
M2  MCU:PA3
M3  MCU:PA7
M4  MCU:PB1
M5  MCU:PF11
M6  MCU:PF14
M7  MCU:PE7
M8  MCU:PE15
M9  MCU:PB10
M10  MCU:PB11
M11  MCU:PB12
M12  MCU:PB13

## Footprint LFBGA144 (pad centres in mm)
LFBGA144 10 x 10 mm, 12 x 12-pin low profil 0.8 mm pitch ball grid array package
smd 0.52 x 0.52: A1 -4.4,4.4; A2 -3.6,4.4; A3 -2.8,4.4; A4 -2,4.4; A5 -1.2,4.4; A6 -0.4,4.4; A7 0.4,4.4; A8 1.2,4.4; A9 2,4.4; A10 2.8,4.4; A11 3.6,4.4; A12 4.4,4.4; B1 -4.4,3.6; B2 -3.6,3.6; B3 -2.8,3.6; B4 -2,3.6; B5 -1.2,3.6; B6 -0.4,3.6; B7 0.4,3.6; B8 1.2,3.6; B9 2,3.6; B10 2.8,3.6; B11 3.6,3.6; B12 4.4,3.6; C1 -4.4,2.8; C2 -3.6,2.8; C3 -2.8,2.8; C4 -2,2.8; C5 -1.2,2.8; C6 -0.4,2.8; C7 0.4,2.8; C8 1.2,2.8; C9 2,2.8; C10 2.8,2.8; C11 3.6,2.8; C12 4.4,2.8; D1 -4.4,2; D2 -3.6,2; D3 -2.8,2; D4 -2,2; D5 -1.2,2; D6 -0.4,2; D7 0.4,2; D8 1.2,2; D9 2,2; D10 2.8,2; D11 3.6,2; D12 4.4,2; E1 -4.4,1.2; E2 -3.6,1.2; E3 -2.8,1.2; E4 -2,1.2; E5 -1.2,1.2; E6 -0.4,1.2; E7 0.4,1.2; E8 1.2,1.2; E9 2,1.2; E10 2.8,1.2; E11 3.6,1.2; E12 4.4,1.2; F1 -4.4,0.4; F2 -3.6,0.4; F3 -2.8,0.4; F4 -2,0.4; F5 -1.2,0.4; F6 -0.4,0.4; F7 0.4,0.4; F8 1.2,0.4; F9 2,0.4; F10 2.8,0.4; F11 3.6,0.4; F12 4.4,0.4; G1 -4.4,-0.4; G2 -3.6,-0.4; G3 -2.8,-0.4; G4 -2,-0.4; G5 -1.2,-0.4; G6 -0.4,-0.4; G7 0.4,-0.4; G8 1.2,-0.4; G9 2,-0.4; G10 2.8,-0.4; G11 3.6,-0.4; G12 4.4,-0.4; H1 -4.4,-1.2; H2 -3.6,-1.2; H3 -2.8,-1.2; H4 -2,-1.2; H5 -1.2,-1.2; H6 -0.4,-1.2; H7 0.4,-1.2; H8 1.2,-1.2; H9 2,-1.2; H10 2.8,-1.2; H11 3.6,-1.2; H12 4.4,-1.2; J1 -4.4,-2; J2 -3.6,-2; J3 -2.8,-2; J4 -2,-2; J5 -1.2,-2; J6 -0.4,-2; J7 0.4,-2; J8 1.2,-2; J9 2,-2; J10 2.8,-2; J11 3.6,-2; J12 4.4,-2; K1 -4.4,-2.8; K2 -3.6,-2.8; K3 -2.8,-2.8; K4 -2,-2.8; K5 -1.2,-2.8; K6 -0.4,-2.8; K7 0.4,-2.8; K8 1.2,-2.8; K9 2,-2.8; K10 2.8,-2.8; K11 3.6,-2.8; K12 4.4,-2.8; L1 -4.4,-3.6; L2 -3.6,-3.6; L3 -2.8,-3.6; L4 -2,-3.6; L5 -1.2,-3.6; L6 -0.4,-3.6; L7 0.4,-3.6; L8 1.2,-3.6; L9 2,-3.6; L10 2.8,-3.6; L11 3.6,-3.6; L12 4.4,-3.6; M1 -4.4,-4.4; M2 -3.6,-4.4; M3 -2.8,-4.4; M4 -2,-4.4; M5 -1.2,-4.4; M6 -0.4,-4.4; M7 0.4,-4.4; M8 1.2,-4.4; M9 2,-4.4; M10 2.8,-4.4; M11 3.6,-4.4; M12 4.4,-4.4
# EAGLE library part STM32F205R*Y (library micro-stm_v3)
ARM 32-bit Cortex™-M3 CPU 120 MHz maximum frequency 512 to 1024 Kbytes of Flash memory 128 kbytes of SRAM 51 GPIOs 1.8 to 3.6 V application supply

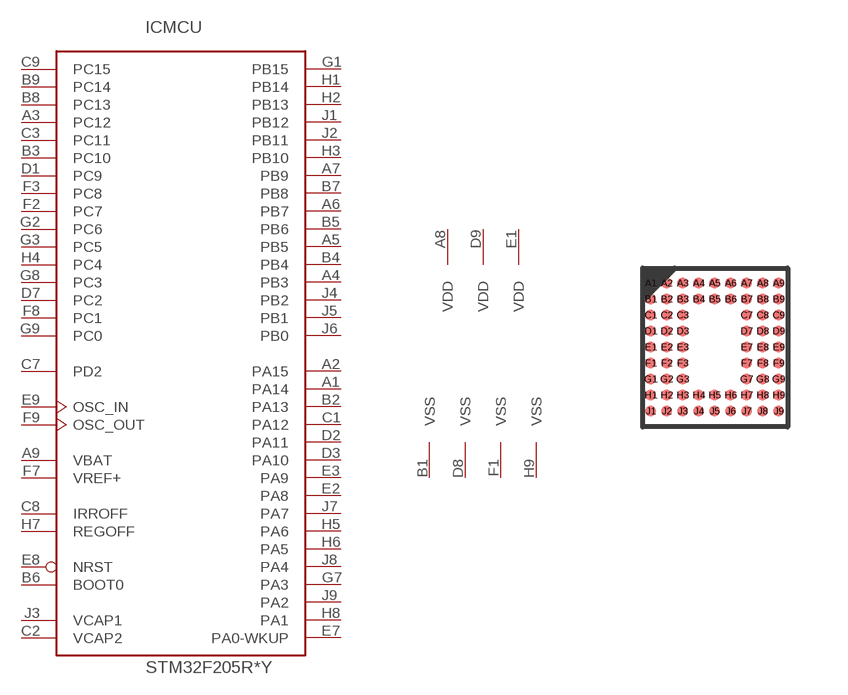
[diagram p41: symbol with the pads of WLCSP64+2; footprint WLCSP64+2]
Designator prefix IC; gates MCU=STM32_66PIN_TYP1 PWR=PWR_VDD3_VSS4

## STM32F205REY, STM32F205RGY  [WLCSP64+2]
A1  MCU:PA14
A2  MCU:PA15
A3  MCU:PC12
A4  MCU:PB3
A5  MCU:PB5
A6  MCU:PB7
A7  MCU:PB9
A8  PWR:VDD  pwr
A9  MCU:VBAT  pwr
B1  PWR:VSS  pwr
B2  MCU:PA13
B3  MCU:PC10
B4  MCU:PB4
B5  MCU:PB6
B6  MCU:BOOT0  in
B7  MCU:PB8
B8  MCU:PC13
B9  MCU:PC14
C1  MCU:PA12
C2  MCU:VCAP2  pwr
C3  MCU:PC11
C7  MCU:PD2
C8  MCU:IRROFF  in
C9  MCU:PC15
D1  MCU:PC9
D2  MCU:PA11
D3  MCU:PA10
D7  MCU:PC2
D8  PWR:VSS  pwr
D9  PWR:VDD  pwr
E1  PWR:VDD  pwr
E2  MCU:PA8
E3  MCU:PA9
E7  MCU:PA0-WKUP
E8  MCU:NRST
E9  MCU:OSC_IN
F1  PWR:VSS  pwr
F2  MCU:PC7
F3  MCU:PC8
F7  MCU:VREF+  pwr
F8  MCU:PC1
F9  MCU:OSC_OUT
G1  MCU:PB15
G2  MCU:PC6
G3  MCU:PC5
G7  MCU:PA3
G8  MCU:PC3
G9  MCU:PC0
H1  MCU:PB14
H2  MCU:PB13
H3  MCU:PB10
H4  MCU:PC4
H5  MCU:PA6
H6  MCU:PA5
H7  MCU:REGOFF  in
H8  MCU:PA1
H9  PWR:VSS  pwr
J1  MCU:PB12
J2  MCU:PB11
J3  MCU:VCAP1  pwr
J4  MCU:PB2
J5  MCU:PB1
J6  MCU:PB0
J7  MCU:PA7
J8  MCU:PA4
J9  MCU:PA2

## Footprint WLCSP64+2 (pad centres in mm)
WLCSP64+2 3.639 x 3.971 mm, 9 x 9-pin 0.4 mm pitch wafer-level chip-scale package
smd 0.27 x 0.27: A1 -1.609,1.609; A2 -1.209,1.609; A3 -0.809,1.609; A4 -0.409,1.609; A5 -0.009,1.609; A6 0.391,1.609; A7 0.791,1.609; A8 1.191,1.609; A9 1.591,1.609; B1 -1.61,1.209; B2 -1.21,1.209; B3 -0.81,1.209; B4 -0.41,1.209; B5 -0.01,1.209; B6 0.39,1.209; B7 0.79,1.209; B8 1.19,1.209; B9 1.59,1.209; C1 -1.61,0.809; C2 -1.21,0.809; C3 -0.81,0.809; C7 0.79,0.809; C8 1.19,0.809; C9 1.59,0.809; D1 -1.61,0.409; D2 -1.21,0.409; D3 -0.81,0.409; D7 0.79,0.409; D8 1.19,0.409; D9 1.59,0.409; E1 -1.61,0.009; E2 -1.21,0.009; E3 -0.81,0.009; E7 0.79,0.009; E8 1.19,0.009; E9 1.59,0.009; F1 -1.61,-0.391; F2 -1.21,-0.391; F3 -0.81,-0.391; F7 0.79,-0.391; F8 1.19,-0.391; F9 1.59,-0.391; G1 -1.61,-0.791; G2 -1.21,-0.791; G3 -0.81,-0.791; G7 0.79,-0.791; G8 1.19,-0.791; G9 1.59,-0.791; H1 -1.61,-1.191; H2 -1.21,-1.191; H3 -0.81,-1.191; H4 -0.41,-1.191; H5 -0.01,-1.191; H6 0.39,-1.191; H7 0.79,-1.191; H8 1.19,-1.191; H9 1.59,-1.191; J1 -1.61,-1.591; J2 -1.21,-1.591; J3 -0.81,-1.591; J4 -0.41,-1.591; J5 -0.01,-1.591; J6 0.39,-1.591; J7 0.79,-1.591; J8 1.19,-1.591; J9 1.59,-1.591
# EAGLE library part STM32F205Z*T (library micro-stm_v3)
ARM 32-bit Cortex™-M3 CPU 120 MHz maximum frequency 256 to 1024 Kbytes of Flash memory 96 to 128 kbytes of SRAM 114 GPIOs 1.8 to 3.6 V application supply

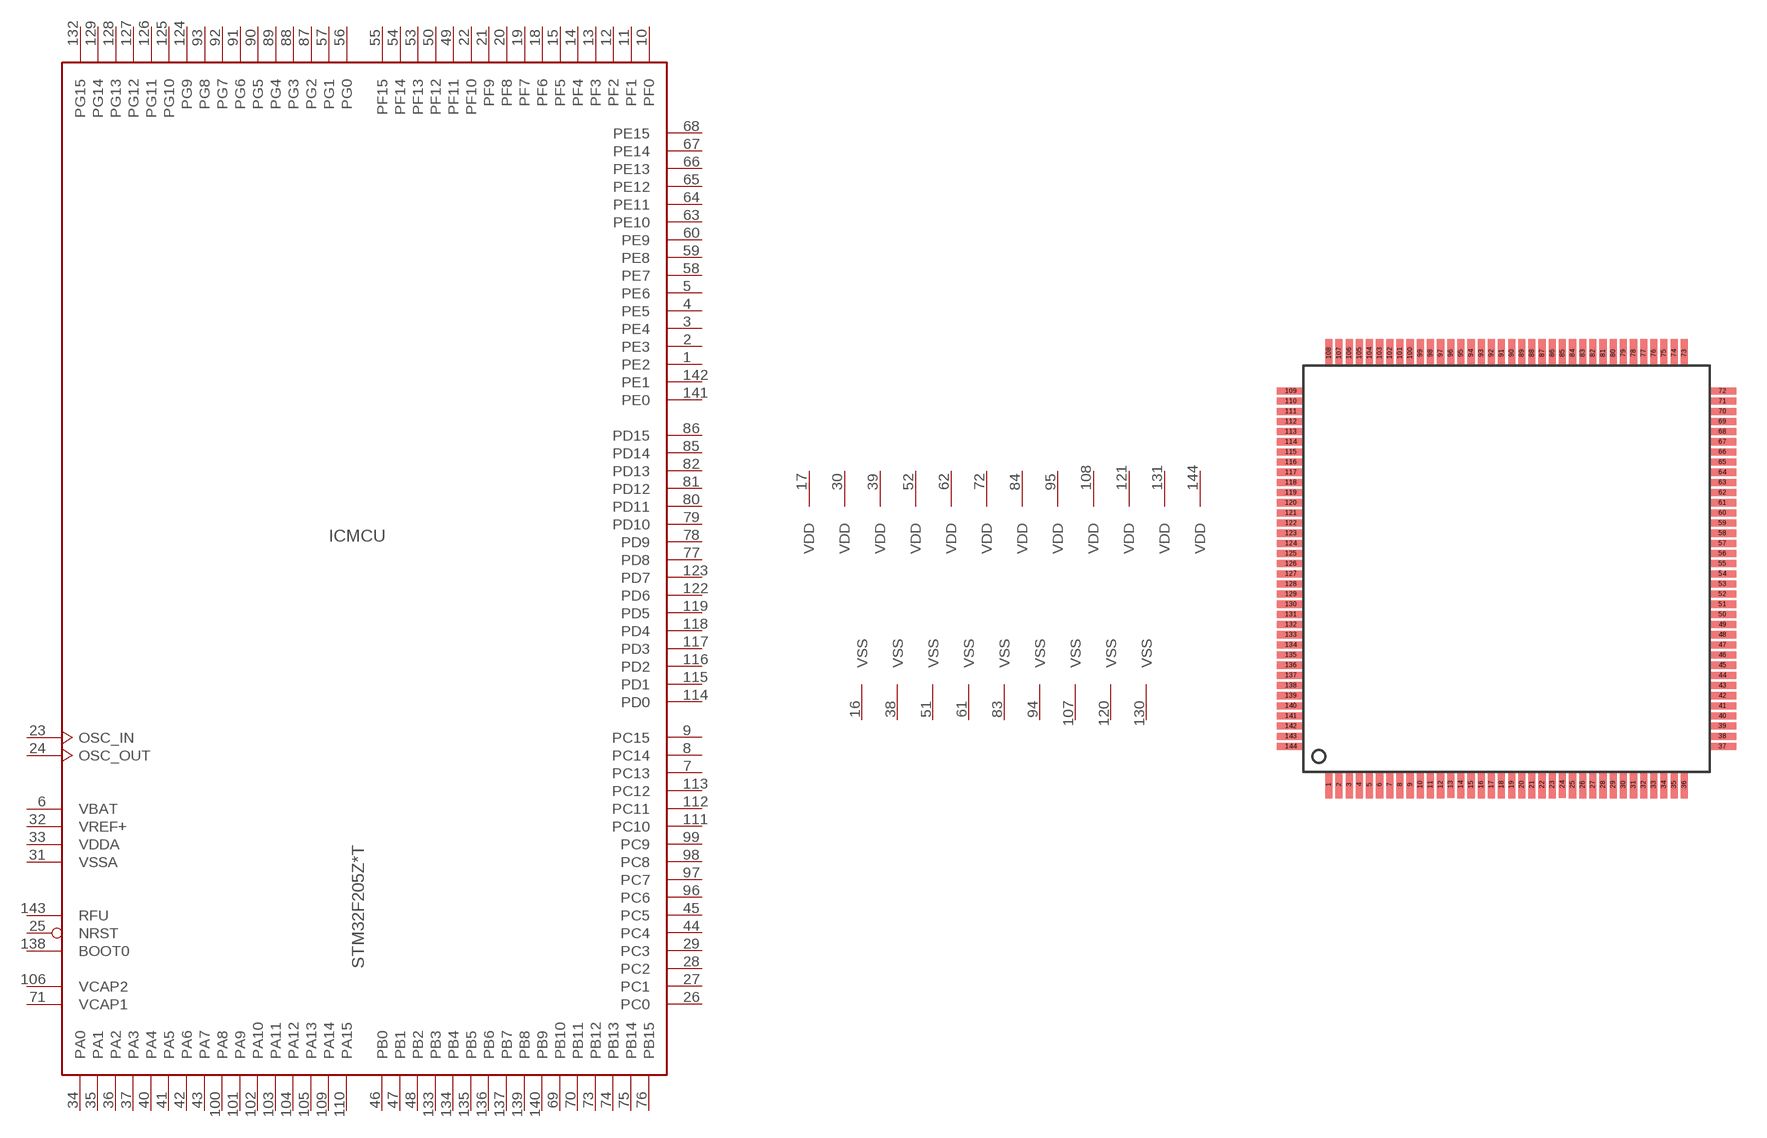
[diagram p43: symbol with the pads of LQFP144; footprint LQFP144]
Designator prefix IC; gates MCU=STM32_144PIN_TYP2 PWR=PWR_VDD12_VSS9

## STM32F205ZCT, STM32F205ZET, STM32F205ZFT, STM32F205ZGT  [LQFP144]
1  MCU:PE2
2  MCU:PE3
3  MCU:PE4
4  MCU:PE5
5  MCU:PE6
6  MCU:VBAT  pwr
7  MCU:PC13
8  MCU:PC14
9  MCU:PC15
10  MCU:PF0
11  MCU:PF1
12  MCU:PF2
13  MCU:PF3
14  MCU:PF4
15  MCU:PF5
16  PWR:VSS  pwr
17  PWR:VDD  pwr
18  MCU:PF6
19  MCU:PF7
20  MCU:PF8
21  MCU:PF9
22  MCU:PF10
23  MCU:OSC_IN
24  MCU:OSC_OUT
25  MCU:NRST
26  MCU:PC0
27  MCU:PC1
28  MCU:PC2
29  MCU:PC3
30  PWR:VDD  pwr
31  MCU:VSSA  pwr
32  MCU:VREF+  pwr
33  MCU:VDDA  pwr
34  MCU:PA0
35  MCU:PA1
36  MCU:PA2
37  MCU:PA3
38  PWR:VSS  pwr
39  PWR:VDD  pwr
40  MCU:PA4
41  MCU:PA5
42  MCU:PA6
43  MCU:PA7
44  MCU:PC4
45  MCU:PC5
46  MCU:PB0
47  MCU:PB1
48  MCU:PB2
49  MCU:PF11
50  MCU:PF12
51  PWR:VSS  pwr
52  PWR:VDD  pwr
53  MCU:PF13
54  MCU:PF14
55  MCU:PF15
56  MCU:PG0
57  MCU:PG1
58  MCU:PE7
59  MCU:PE8
60  MCU:PE9
61  PWR:VSS  pwr
62  PWR:VDD  pwr
63  MCU:PE10
64  MCU:PE11
65  MCU:PE12
66  MCU:PE13
67  MCU:PE14
68  MCU:PE15
69  MCU:PB10
70  MCU:PB11
71  MCU:VCAP1  pwr
72  PWR:VDD  pwr
73  MCU:PB12
74  MCU:PB13
75  MCU:PB14
76  MCU:PB15
77  MCU:PD8
78  MCU:PD9
79  MCU:PD10
80  MCU:PD11
81  MCU:PD12
82  MCU:PD13
83  PWR:VSS  pwr
84  PWR:VDD  pwr
85  MCU:PD14
86  MCU:PD15
87  MCU:PG2
88  MCU:PG3
89  MCU:PG4
90  MCU:PG5
91  MCU:PG6
92  MCU:PG7
93  MCU:PG8
94  PWR:VSS  pwr
95  PWR:VDD  pwr
96  MCU:PC6
97  MCU:PC7
98  MCU:PC8
99  MCU:PC9
100  MCU:PA8
101  MCU:PA9
102  MCU:PA10
103  MCU:PA11
104  MCU:PA12
105  MCU:PA13
106  MCU:VCAP2  pwr
107  PWR:VSS  pwr
108  PWR:VDD  pwr
109  MCU:PA14
110  MCU:PA15
111  MCU:PC10
112  MCU:PC11
113  MCU:PC12
114  MCU:PD0
115  MCU:PD1
116  MCU:PD2
117  MCU:PD3
118  MCU:PD4
119  MCU:PD5
120  PWR:VSS  pwr
121  PWR:VDD  pwr
122  MCU:PD6
123  MCU:PD7
124  MCU:PG9
125  MCU:PG10
126  MCU:PG11
127  MCU:PG12
128  MCU:PG13
129  MCU:PG14
130  PWR:VSS  pwr
131  PWR:VDD  pwr
132  MCU:PG15
133  MCU:PB3
134  MCU:PB4
135  MCU:PB5
136  MCU:PB6
137  MCU:PB7
138  MCU:BOOT0  in
139  MCU:PB8
140  MCU:PB9
141  MCU:PE0
142  MCU:PE1
143  MCU:RFU  in
144  PWR:VDD  pwr

## Footprint LQFP144 (pad centres in mm)
LQFP144 20 x 20 mm, 144-pin low-profile quad flat package
smd 0.35 x 1.35: 1 -8.75,-10.625; 2 -8.25,-10.625; 3 -7.75,-10.625; 4 -7.25,-10.625; 5 -6.75,-10.625; 6 -6.25,-10.625; 7 -5.75,-10.625; 8 -5.25,-10.625; 9 -4.75,-10.625; 10 -4.25,-10.625; 11 -3.75,-10.625; 12 -3.25,-10.625; 13 -2.75,-10.62; 14 -2.25,-10.625; 15 -1.75,-10.625; 16 -1.25,-10.625; 17 -0.75,-10.625; 18 -0.25,-10.625; 19 0.25,-10.625; 20 0.75,-10.625; 21 1.25,-10.625; 22 1.75,-10.625; 23 2.25,-10.625; 24 2.75,-10.62; 25 3.25,-10.625; 26 3.75,-10.625; 27 4.25,-10.625; 28 4.75,-10.625; 29 5.25,-10.625; 30 5.75,-10.625; 31 6.25,-10.625; 32 6.75,-10.625; 33 7.25,-10.625; 34 7.75,-10.625; 35 8.25,-10.625; 36 8.75,-10.625; 73 8.75,10.625; 74 8.25,10.625; 75 7.75,10.625; 76 7.25,10.625; 77 6.75,10.625; 78 6.25,10.625; 79 5.75,10.625; 80 5.25,10.625; 81 4.75,10.625; 82 4.25,10.625; 83 3.75,10.625; 84 3.25,10.625; 85 2.75,10.625; 86 2.25,10.625; 87 1.75,10.625; 88 1.25,10.625; 89 0.75,10.625; 90 0.25,10.625; 91 -0.25,10.625; 92 -0.75,10.625; 93 -1.25,10.625; 94 -1.75,10.625; 95 -2.25,10.625; 96 -2.75,10.625; 97 -3.25,10.625; 98 -3.75,10.625; 99 -4.25,10.625; 100 -4.75,10.625; 101 -5.25,10.625; 102 -5.75,10.625; 103 -6.25,10.625; 104 -6.75,10.625; 105 -7.25,10.625; 106 -7.75,10.625; 107 -8.25,10.625; 108 -8.75,10.625
smd 1.35 x 0.35: 37 10.625,-8.75; 38 10.625,-8.25; 39 10.625,-7.75; 40 10.625,-7.25; 41 10.625,-6.75; 42 10.625,-6.25; 43 10.625,-5.75; 44 10.625,-5.25; 45 10.625,-4.75; 46 10.625,-4.25; 47 10.625,-3.75; 48 10.625,-3.25; 49 10.625,-2.75; 50 10.625,-2.25; 51 10.625,-1.75; 52 10.625,-1.25; 53 10.625,-0.75; 54 10.625,-0.25; 55 10.625,0.25; 56 10.625,0.75; 57 10.625,1.25; 58 10.625,1.75; 59 10.625,2.25; 60 10.625,2.75; 61 10.625,3.25; 62 10.625,3.75; 63 10.625,4.25; 64 10.625,4.75; 65 10.625,5.25; 66 10.625,5.75; 67 10.625,6.25; 68 10.625,6.75; 69 10.625,7.25; 70 10.625,7.75; 71 10.625,8.25; 72 10.625,8.75; 109 -10.625,8.75; 110 -10.625,8.25; 111 -10.625,7.75; 112 -10.625,7.25; 113 -10.625,6.75; 114 -10.625,6.25; 115 -10.625,5.75; 116 -10.625,5.25; 117 -10.625,4.75; 118 -10.625,4.25; 119 -10.625,3.75; 120 -10.625,3.25; 121 -10.625,2.75; 122 -10.625,2.25; 123 -10.625,1.75; 124 -10.625,1.25; 125 -10.625,0.75; 126 -10.625,0.25; 127 -10.625,-0.25; 128 -10.625,-0.75; 129 -10.625,-1.25; 130 -10.625,-1.75; 131 -10.625,-2.25; 132 -10.625,-2.75; 133 -10.625,-3.25; 134 -10.625,-3.75; 135 -10.625,-4.25; 136 -10.625,-4.75; 137 -10.625,-5.25; 138 -10.625,-5.75; 139 -10.625,-6.25; 140 -10.625,-6.75; 141 -10.625,-7.25; 142 -10.625,-7.75; 143 -10.625,-8.25; 144 -10.625,-8.75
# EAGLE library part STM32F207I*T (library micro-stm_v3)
ARM 32-bit Cortex™-M3 CPU 120 MHz maximum frequency 256 to 1024 Kbytes of Flash memory 128 kbytes of SRAM 140 GPIOs 1.8 to 3.6 V application supply

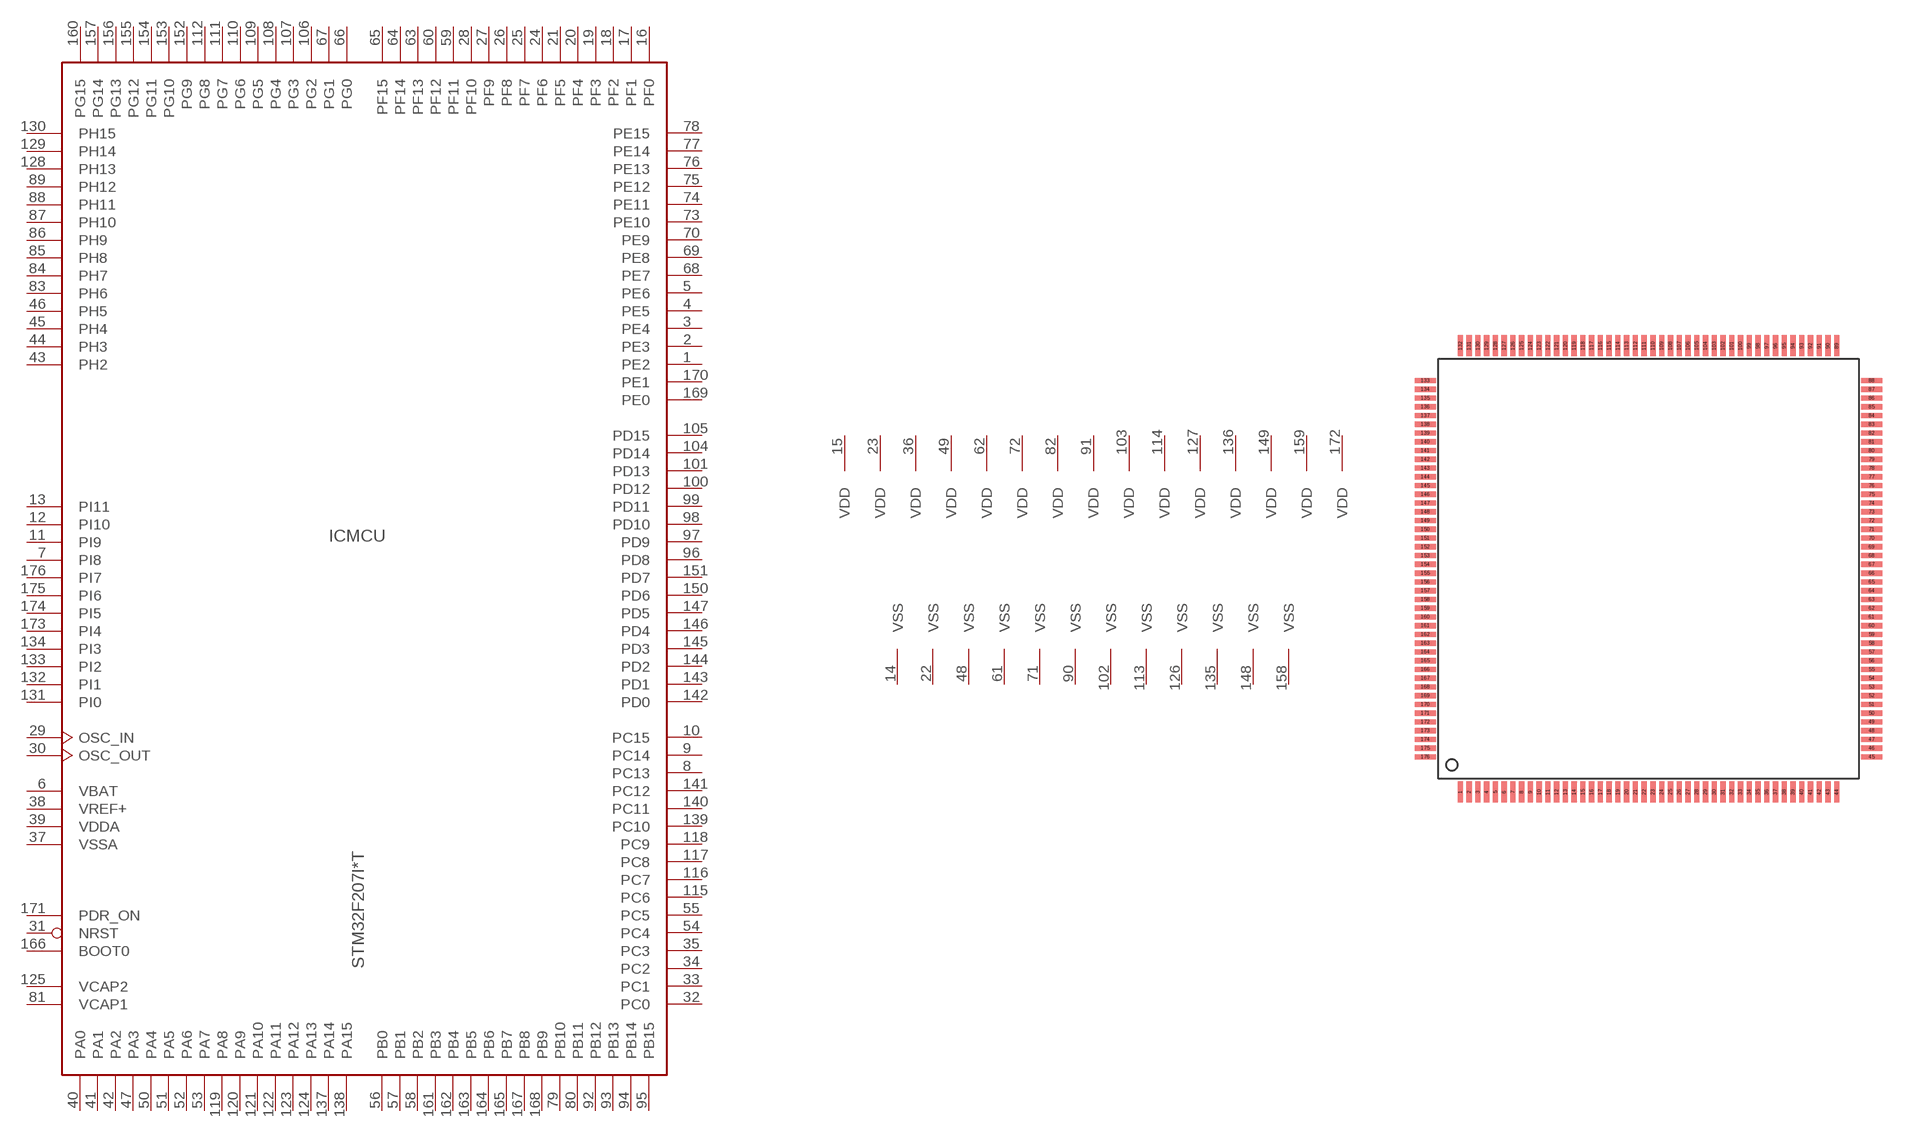
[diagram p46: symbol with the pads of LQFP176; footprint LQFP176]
Designator prefix IC; gates MCU=STM32_176PIN_TYP1 PWR=PWR_VDD15_VSS12

## STM32F207ICT, STM32F207IET, STM32F207IFT, STM32F207IGT  [LQFP176]
1  MCU:PE2
2  MCU:PE3
3  MCU:PE4
4  MCU:PE5
5  MCU:PE6
6  MCU:VBAT  pwr
7  MCU:PI8
8  MCU:PC13
9  MCU:PC14
10  MCU:PC15
11  MCU:PI9
12  MCU:PI10
13  MCU:PI11
14  PWR:VSS  pwr
15  PWR:VDD  pwr
16  MCU:PF0
17  MCU:PF1
18  MCU:PF2
19  MCU:PF3
20  MCU:PF4
21  MCU:PF5
22  PWR:VSS  pwr
23  PWR:VDD  pwr
24  MCU:PF6
25  MCU:PF7
26  MCU:PF8
27  MCU:PF9
28  MCU:PF10
29  MCU:OSC_IN
30  MCU:OSC_OUT
31  MCU:NRST
32  MCU:PC0
33  MCU:PC1
34  MCU:PC2
35  MCU:PC3
36  PWR:VDD  pwr
37  MCU:VSSA  pwr
38  MCU:VREF+  pwr
39  MCU:VDDA  pwr
40  MCU:PA0
41  MCU:PA1
42  MCU:PA2
43  MCU:PH2
44  MCU:PH3
45  MCU:PH4
46  MCU:PH5
47  MCU:PA3
48  PWR:VSS  pwr
49  PWR:VDD  pwr
50  MCU:PA4
51  MCU:PA5
52  MCU:PA6
53  MCU:PA7
54  MCU:PC4
55  MCU:PC5
56  MCU:PB0
57  MCU:PB1
58  MCU:PB2
59  MCU:PF11
60  MCU:PF12
61  PWR:VSS  pwr
62  PWR:VDD  pwr
63  MCU:PF13
64  MCU:PF14
65  MCU:PF15
66  MCU:PG0
67  MCU:PG1
68  MCU:PE7
69  MCU:PE8
70  MCU:PE9
71  PWR:VSS  pwr
72  PWR:VDD  pwr
73  MCU:PE10
74  MCU:PE11
75  MCU:PE12
76  MCU:PE13
77  MCU:PE14
78  MCU:PE15
79  MCU:PB10
80  MCU:PB11
81  MCU:VCAP1  pwr
82  PWR:VDD  pwr
83  MCU:PH6
84  MCU:PH7
85  MCU:PH8
86  MCU:PH9
87  MCU:PH10
88  MCU:PH11
89  MCU:PH12
90  PWR:VSS  pwr
91  PWR:VDD  pwr
92  MCU:PB12
93  MCU:PB13
94  MCU:PB14
95  MCU:PB15
96  MCU:PD8
97  MCU:PD9
98  MCU:PD10
99  MCU:PD11
100  MCU:PD12
101  MCU:PD13
102  PWR:VSS  pwr
103  PWR:VDD  pwr
104  MCU:PD14
105  MCU:PD15
106  MCU:PG2
107  MCU:PG3
108  MCU:PG4
109  MCU:PG5
110  MCU:PG6
111  MCU:PG7
112  MCU:PG8
113  PWR:VSS  pwr
114  PWR:VDD  pwr
115  MCU:PC6
116  MCU:PC7
117  MCU:PC8
118  MCU:PC9
119  MCU:PA8
120  MCU:PA9
121  MCU:PA10
122  MCU:PA11
123  MCU:PA12
124  MCU:PA13
125  MCU:VCAP2  pwr
126  PWR:VSS  pwr
127  PWR:VDD  pwr
128  MCU:PH13
129  MCU:PH14
130  MCU:PH15
131  MCU:PI0
132  MCU:PI1
133  MCU:PI2
134  MCU:PI3
135  PWR:VSS  pwr
136  PWR:VDD  pwr
137  MCU:PA14
138  MCU:PA15
139  MCU:PC10
140  MCU:PC11
141  MCU:PC12
142  MCU:PD0
143  MCU:PD1
144  MCU:PD2
145  MCU:PD3
146  MCU:PD4
147  MCU:PD5
148  PWR:VSS  pwr
149  PWR:VDD  pwr
150  MCU:PD6
151  MCU:PD7
152  MCU:PG9
153  MCU:PG10
154  MCU:PG11
155  MCU:PG12
156  MCU:PG13
157  MCU:PG14
158  PWR:VSS  pwr
159  PWR:VDD  pwr
160  MCU:PG15
161  MCU:PB3
162  MCU:PB4
163  MCU:PB5
164  MCU:PB6
165  MCU:PB7
166  MCU:BOOT0  in
167  MCU:PB8
168  MCU:PB9
169  MCU:PE0
170  MCU:PE1
171  MCU:PDR_ON  in
172  PWR:VDD  pwr
173  MCU:PI4
174  MCU:PI5
175  MCU:PI6
176  MCU:PI7

## Footprint LQFP176 (pad centres in mm)
LQFP176 24 x 24 mm, 176-pin low-profile quad flat package
smd 0.3 x 1.2: 1 -10.75,-12.75; 2 -10.25,-12.75; 3 -9.75,-12.75; 4 -9.25,-12.75; 5 -8.75,-12.75; 6 -8.25,-12.75; 7 -7.75,-12.75; 8 -7.25,-12.75; 9 -6.75,-12.75; 10 -6.25,-12.75; 11 -5.75,-12.75; 12 -5.25,-12.75; 13 -4.75,-12.75; 14 -4.25,-12.75; 15 -3.75,-12.75; 16 -3.25,-12.75; 17 -2.75,-12.75; 18 -2.25,-12.75; 19 -1.75,-12.75; 20 -1.25,-12.75; 21 -0.75,-12.75; 22 -0.25,-12.75; 23 0.25,-12.75; 24 0.75,-12.75; 25 1.25,-12.75; 26 1.75,-12.75; 27 2.25,-12.75; 28 2.75,-12.75; 29 3.25,-12.75; 30 3.75,-12.75; 31 4.25,-12.75; 32 4.75,-12.75; 33 5.25,-12.75; 34 5.75,-12.75; 35 6.25,-12.75; 36 6.75,-12.75; 37 7.25,-12.75; 38 7.75,-12.75; 39 8.25,-12.75; 40 8.75,-12.75; 41 9.25,-12.75; 42 9.75,-12.75; 43 10.25,-12.75; 44 10.75,-12.75; 89 10.75,12.75; 90 10.25,12.75; 91 9.75,12.75; 92 9.25,12.75; 93 8.75,12.75; 94 8.25,12.75; 95 7.75,12.75; 96 7.25,12.75; 97 6.75,12.75; 98 6.25,12.75; 99 5.75,12.75; 100 5.25,12.75; 101 4.75,12.75; 102 4.25,12.75; 103 3.75,12.75; 104 3.25,12.75; 105 2.75,12.75; 106 2.25,12.75; 107 1.75,12.75; 108 1.25,12.75; 109 0.75,12.75; 110 0.25,12.75; 111 -0.25,12.75; 112 -0.75,12.75; 113 -1.25,12.75; 114 -1.75,12.75; 115 -2.25,12.75; 116 -2.75,12.75; 117 -3.25,12.75; 118 -3.75,12.75; 119 -4.25,12.75; 120 -4.75,12.75; 121 -5.25,12.75; 122 -5.75,12.75; 123 -6.25,12.75; 124 -6.75,12.75; 125 -7.25,12.75; 126 -7.75,12.75; 127 -8.25,12.75; 128 -8.75,12.75; 129 -9.25,12.75; 130 -9.75,12.75; 131 -10.25,12.75; 132 -10.75,12.75
smd 1.2 x 0.3: 45 12.75,-10.75; 46 12.75,-10.25; 47 12.75,-9.75; 48 12.75,-9.25; 49 12.75,-8.75; 50 12.75,-8.25; 51 12.75,-7.75; 52 12.75,-7.25; 53 12.75,-6.75; 54 12.75,-6.25; 55 12.75,-5.75; 56 12.75,-5.25; 57 12.75,-4.75; 58 12.75,-4.25; 59 12.75,-3.75; 60 12.75,-3.25; 61 12.75,-2.75; 62 12.75,-2.25; 63 12.75,-1.75; 64 12.75,-1.25; 65 12.75,-0.75; 66 12.75,-0.25; 67 12.75,0.25; 68 12.75,0.75; 69 12.75,1.25; 70 12.75,1.75; 71 12.75,2.25; 72 12.75,2.75; 73 12.75,3.25; 74 12.75,3.75; 75 12.75,4.25; 76 12.75,4.75; 77 12.75,5.25; 78 12.75,5.75; 79 12.75,6.25; 80 12.75,6.75; 81 12.75,7.25; 82 12.75,7.75; 83 12.75,8.25; 84 12.75,8.75; 85 12.75,9.25; 86 12.75,9.75; 87 12.75,10.25; 88 12.75,10.75; 133 -12.75,10.75; 134 -12.75,10.25; 135 -12.75,9.75; 136 -12.75,9.25; 137 -12.75,8.75; 138 -12.75,8.25; 139 -12.75,7.75; 140 -12.75,7.25; 141 -12.75,6.75; 142 -12.75,6.25; 143 -12.75,5.75; 144 -12.75,5.25; 145 -12.75,4.75; 146 -12.75,4.25; 147 -12.75,3.75; 148 -12.75,3.25; 149 -12.75,2.75; 150 -12.75,2.25; 151 -12.75,1.75; 152 -12.75,1.25; 153 -12.75,0.75; 154 -12.75,0.25; 155 -12.75,-0.25; 156 -12.75,-0.75; 157 -12.75,-1.25; 158 -12.75,-1.75; 159 -12.75,-2.25; 160 -12.75,-2.75; 161 -12.75,-3.25; 162 -12.75,-3.75; 163 -12.75,-4.25; 164 -12.75,-4.75; 165 -12.75,-5.25; 166 -12.75,-5.75; 167 -12.75,-6.25; 168 -12.75,-6.75; 169 -12.75,-7.25; 170 -12.75,-7.75; 171 -12.75,-8.25; 172 -12.75,-8.75; 173 -12.75,-9.25; 174 -12.75,-9.75; 175 -12.75,-10.25; 176 -12.75,-10.75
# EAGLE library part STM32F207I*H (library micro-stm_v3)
ARM 32-bit Cortex™-M3 CPU 120 MHz maximum frequency 256 to 1024 Kbytes of Flash memory 128 kbytes of SRAM 140 GPIOs 1.8 to 3.6 V application supply

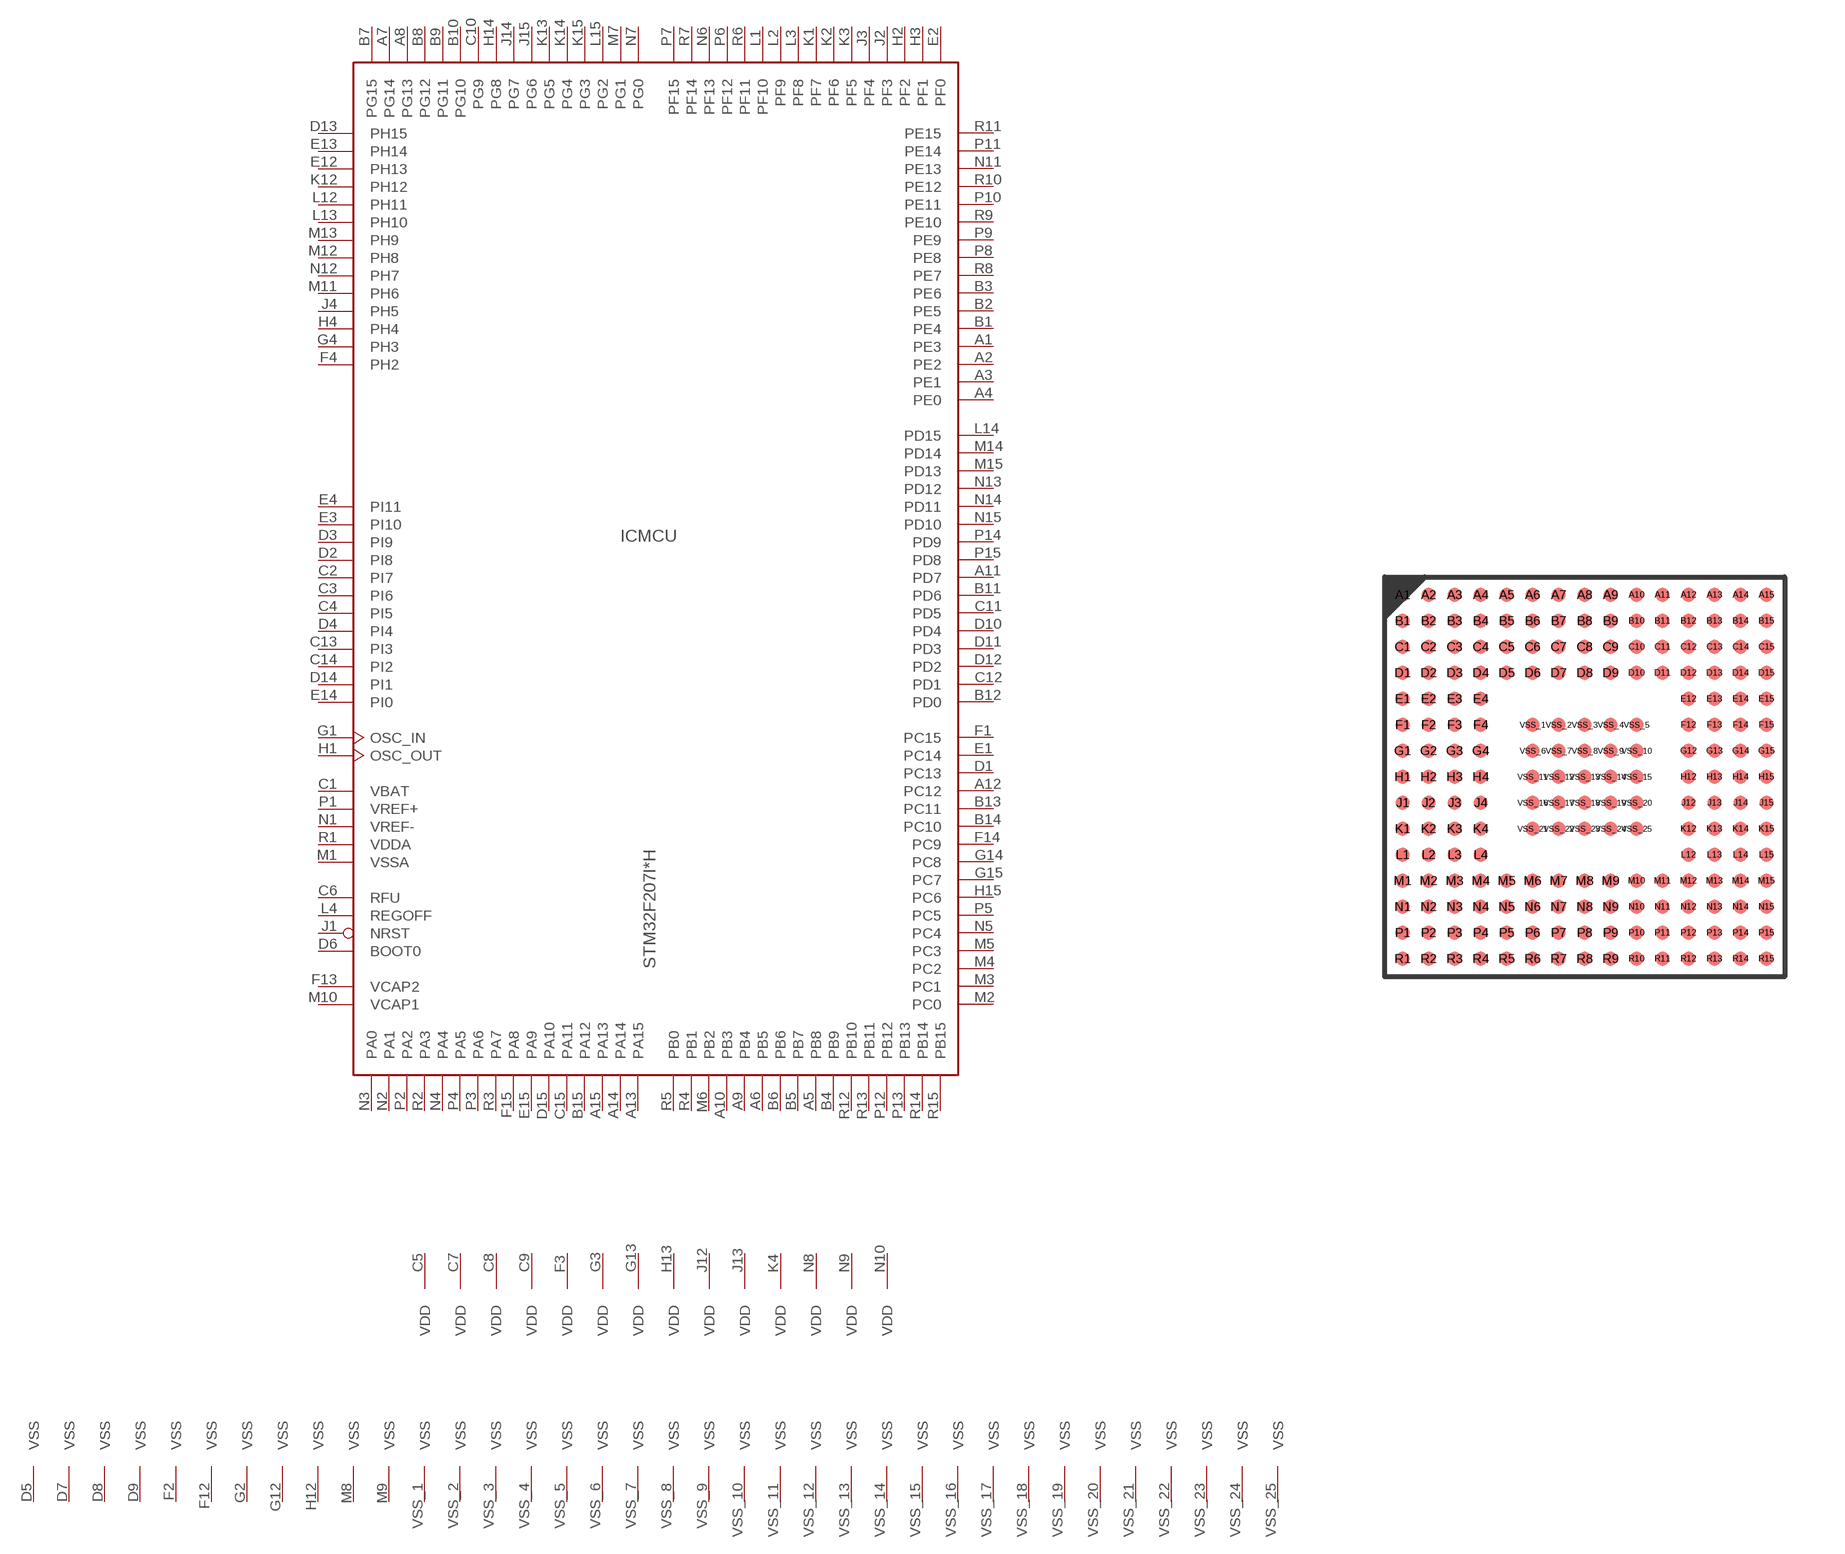
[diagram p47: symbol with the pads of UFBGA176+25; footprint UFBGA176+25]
Designator prefix IC; gates MCU=STM32_176PIN_TYP2 PWR=PWR_VDD14_VSS36

## STM32F207ICH, STM32F207IEH, STM32F207IFH, STM32F207IGH  [UFBGA176+25]
A1  MCU:PE3
A2  MCU:PE2
A3  MCU:PE1
A4  MCU:PE0
A5  MCU:PB8
A6  MCU:PB5
A7  MCU:PG14
A8  MCU:PG13
A9  MCU:PB4
A10  MCU:PB3
A11  MCU:PD7
A12  MCU:PC12
A13  MCU:PA15
A14  MCU:PA14
A15  MCU:PA13
B1  MCU:PE4
B2  MCU:PE5
B3  MCU:PE6
B4  MCU:PB9
B5  MCU:PB7
B6  MCU:PB6
B7  MCU:PG15
B8  MCU:PG12
B9  MCU:PG11
B10  MCU:PG10
B11  MCU:PD6
B12  MCU:PD0
B13  MCU:PC11
B14  MCU:PC10
B15  MCU:PA12
C1  MCU:VBAT  pwr
C2  MCU:PI7
C3  MCU:PI6
C4  MCU:PI5
C5  PWR:VDD  pwr
C6  MCU:RFU  in
C7  PWR:VDD  pwr
C8  PWR:VDD  pwr
C9  PWR:VDD  pwr
C10  MCU:PG9
C11  MCU:PD5
C12  MCU:PD1
C13  MCU:PI3
C14  MCU:PI2
C15  MCU:PA11
D1  MCU:PC13
D2  MCU:PI8
D3  MCU:PI9
D4  MCU:PI4
D5  PWR:VSS  pwr
D6  MCU:BOOT0  in
D7  PWR:VSS  pwr
D8  PWR:VSS  pwr
D9  PWR:VSS  pwr
D10  MCU:PD4
D11  MCU:PD3
D12  MCU:PD2
D13  MCU:PH15
D14  MCU:PI1
D15  MCU:PA10
E1  MCU:PC14
E2  MCU:PF0
E3  MCU:PI10
E4  MCU:PI11
E12  MCU:PH13
E13  MCU:PH14
E14  MCU:PI0
E15  MCU:PA9
F1  MCU:PC15
F2  PWR:VSS  pwr
F3  PWR:VDD  pwr
F4  MCU:PH2
F12  PWR:VSS  pwr
F13  MCU:VCAP2  pwr
F14  MCU:PC9
F15  MCU:PA8
G1  MCU:OSC_IN
G2  PWR:VSS  pwr
G3  PWR:VDD  pwr
G4  MCU:PH3
G12  PWR:VSS  pwr
G13  PWR:VDD  pwr
G14  MCU:PC8
G15  MCU:PC7
H1  MCU:OSC_OUT
H2  MCU:PF2
H3  MCU:PF1
H4  MCU:PH4
H12  PWR:VSS  pwr
H13  PWR:VDD  pwr
H14  MCU:PG8
H15  MCU:PC6
J1  MCU:NRST
J2  MCU:PF3
J3  MCU:PF4
J4  MCU:PH5
J12  PWR:VDD  pwr
J13  PWR:VDD  pwr
J14  MCU:PG7
J15  MCU:PG6
K1  MCU:PF7
K2  MCU:PF6
K3  MCU:PF5
K4  PWR:VDD  pwr
K12  MCU:PH12
K13  MCU:PG5
K14  MCU:PG4
K15  MCU:PG3
L1  MCU:PF10
L2  MCU:PF9
L3  MCU:PF8
L4  MCU:REGOFF  in
L12  MCU:PH11
L13  MCU:PH10
L14  MCU:PD15
L15  MCU:PG2
M1  MCU:VSSA  pwr
M2  MCU:PC0
M3  MCU:PC1
M4  MCU:PC2
M5  MCU:PC3
M6  MCU:PB2
M7  MCU:PG1
M8  PWR:VSS  pwr
M9  PWR:VSS  pwr
M10  MCU:VCAP1  pwr
M11  MCU:PH6
M12  MCU:PH8
M13  MCU:PH9
M14  MCU:PD14
M15  MCU:PD13
N1  MCU:VREF-  pwr
N2  MCU:PA1
N3  MCU:PA0
N4  MCU:PA4
N5  MCU:PC4
N6  MCU:PF13
N7  MCU:PG0
N8  PWR:VDD  pwr
N9  PWR:VDD  pwr
N10  PWR:VDD  pwr
N11  MCU:PE13
N12  MCU:PH7
N13  MCU:PD12
N14  MCU:PD11
N15  MCU:PD10
P1  MCU:VREF+  pwr
P2  MCU:PA2
P3  MCU:PA6
P4  MCU:PA5
P5  MCU:PC5
P6  MCU:PF12
P7  MCU:PF15
P8  MCU:PE8
P9  MCU:PE9
P10  MCU:PE11
P11  MCU:PE14
P12  MCU:PB12
P13  MCU:PB13
P14  MCU:PD9
P15  MCU:PD8
R1  MCU:VDDA  pwr
R2  MCU:PA3
R3  MCU:PA7
R4  MCU:PB1
R5  MCU:PB0
R6  MCU:PF11
R7  MCU:PF14
R8  MCU:PE7
R9  MCU:PE10
R10  MCU:PE12
R11  MCU:PE15
R12  MCU:PB10
R13  MCU:PB11
R14  MCU:PB14
R15  MCU:PB15
VSS_1  PWR:VSS  pwr
VSS_2  PWR:VSS  pwr
VSS_3  PWR:VSS  pwr
VSS_4  PWR:VSS  pwr
VSS_5  PWR:VSS  pwr
VSS_6  PWR:VSS  pwr
VSS_7  PWR:VSS  pwr
VSS_8  PWR:VSS  pwr
VSS_9  PWR:VSS  pwr
VSS_10  PWR:VSS  pwr
VSS_11  PWR:VSS  pwr
VSS_12  PWR:VSS  pwr
VSS_13  PWR:VSS  pwr
VSS_14  PWR:VSS  pwr
VSS_15  PWR:VSS  pwr
VSS_16  PWR:VSS  pwr
VSS_17  PWR:VSS  pwr
VSS_18  PWR:VSS  pwr
VSS_19  PWR:VSS  pwr
VSS_20  PWR:VSS  pwr
VSS_21  PWR:VSS  pwr
VSS_22  PWR:VSS  pwr
VSS_23  PWR:VSS  pwr
VSS_24  PWR:VSS  pwr
VSS_25  PWR:VSS  pwr

## Footprint UFBGA176+25 (pad centres in mm)
UFBGA176+25 10 x 10 mm, 15 x 15-pin ultra fine 0.65 mm pitch ball grid array package
smd 0.35 x 0.35: A1 -4.55,4.55; A2 -3.9,4.55; A3 -3.25,4.55; A4 -2.6,4.55; A5 -1.95,4.55; A6 -1.3,4.55; A7 -0.65,4.55; A8 0,4.55; A9 0.65,4.55; A10 1.3,4.55; A11 1.95,4.55; A12 2.6,4.55; A13 3.25,4.55; A14 3.9,4.55; A15 4.55,4.55; B1 -4.55,3.9; B2 -3.9,3.9; B3 -3.25,3.9; B4 -2.6,3.9; B5 -1.95,3.9; B6 -1.3,3.9; B7 -0.65,3.9; B8 0,3.9; B9 0.65,3.9; B10 1.3,3.9; B11 1.95,3.9; B12 2.6,3.9; B13 3.25,3.9; B14 3.9,3.9; B15 4.55,3.9; C1 -4.55,3.25; C2 -3.9,3.25; C3 -3.25,3.25; C4 -2.6,3.25; C5 -1.95,3.25; C6 -1.3,3.25; C7 -0.65,3.25; C8 0,3.25; C9 0.65,3.25; C10 1.3,3.25; C11 1.95,3.25; C12 2.6,3.25; C13 3.25,3.25; C14 3.9,3.25; C15 4.55,3.25; D1 -4.55,2.6; D2 -3.9,2.6; D3 -3.25,2.6; D4 -2.6,2.6; D5 -1.95,2.6; D6 -1.3,2.6; D7 -0.65,2.6; D8 0,2.6; D9 0.65,2.6; D10 1.3,2.6; D11 1.95,2.6; D12 2.6,2.6; D13 3.25,2.6; D14 3.9,2.6; D15 4.55,2.6; E1 -4.55,1.95; E2 -3.9,1.95; E3 -3.25,1.95; E4 -2.6,1.95; E12 2.6,1.95; E13 3.25,1.95; E14 3.9,1.95; E15 4.55,1.95; F1 -4.55,1.3; F2 -3.9,1.3; F3 -3.25,1.3; F4 -2.6,1.3; F12 2.6,1.3; F13 3.25,1.3; F14 3.9,1.3; F15 4.55,1.3; G1 -4.55,0.65; G2 -3.9,0.65; G3 -3.25,0.65; G4 -2.6,0.65; G12 2.6,0.65; G13 3.25,0.65; G14 3.9,0.65; G15 4.55,0.65; H1 -4.55,0; H2 -3.9,0; H3 -3.25,0; H4 -2.6,0; H12 2.6,0; H13 3.25,0; H14 3.9,0; H15 4.55,0; J1 -4.55,-0.65; J2 -3.9,-0.65; J3 -3.25,-0.65; J4 -2.6,-0.65; J12 2.6,-0.65; J13 3.25,-0.65; J14 3.9,-0.65; J15 4.55,-0.65; K1 -4.55,-1.3; K2 -3.9,-1.3; K3 -3.25,-1.3; K4 -2.6,-1.3; K12 2.6,-1.3; K13 3.25,-1.3; K14 3.9,-1.3; K15 4.55,-1.3; L1 -4.55,-1.95; L2 -3.9,-1.95; L3 -3.25,-1.95; L4 -2.6,-1.95; L12 2.6,-1.95; L13 3.25,-1.95; L14 3.9,-1.95; L15 4.55,-1.95; M1 -4.55,-2.6; M2 -3.9,-2.6; M3 -3.25,-2.6; M4 -2.6,-2.6; M5 -1.95,-2.6; M6 -1.3,-2.6; M7 -0.65,-2.6; M8 0,-2.6; M9 0.65,-2.6; M10 1.3,-2.6; M11 1.95,-2.6; M12 2.6,-2.6; M13 3.25,-2.6; M14 3.9,-2.6; M15 4.55,-2.6; N1 -4.55,-3.25; N2 -3.9,-3.25; N3 -3.25,-3.25; N4 -2.6,-3.25; N5 -1.95,-3.25; N6 -1.3,-3.25; N7 -0.65,-3.25; N8 0,-3.25; N9 0.65,-3.25; N10 1.3,-3.25; N11 1.95,-3.25; N12 2.6,-3.25; N13 3.25,-3.25; N14 3.9,-3.25; N15 4.55,-3.25; P1 -4.55,-3.9; P2 -3.9,-3.9; P3 -3.25,-3.9; P4 -2.6,-3.9; P5 -1.95,-3.9; P6 -1.3,-3.9; P7 -0.65,-3.9; P8 0,-3.9; P9 0.65,-3.9; P10 1.3,-3.9; P11 1.95,-3.9; P12 2.6,-3.9; P13 3.25,-3.9; P14 3.9,-3.9; P15 4.55,-3.9; R1 -4.55,-4.55; R2 -3.9,-4.55; R3 -3.25,-4.55; R4 -2.6,-4.55; R5 -1.95,-4.55; R6 -1.3,-4.55; R7 -0.65,-4.55; R8 0,-4.55; R9 0.65,-4.55; R10 1.3,-4.55; R11 1.95,-4.55; R12 2.6,-4.55; R13 3.25,-4.55; R14 3.9,-4.55; R15 4.55,-4.55; VSS_1 -1.3,1.3; VSS_2 -0.65,1.3; VSS_3 0,1.3; VSS_4 0.65,1.3; VSS_5 1.3,1.3; VSS_6 -1.3,0.65; VSS_7 -0.65,0.65; VSS_8 0,0.65; VSS_9 0.65,0.65; VSS_10 1.3,0.65; VSS_11 -1.3,0; VSS_12 -0.65,0; VSS_13 0,0; VSS_14 0.65,0; VSS_15 1.3,0; VSS_16 -1.3,-0.65; VSS_17 -0.65,-0.65; VSS_18 0,-0.65; VSS_19 0.65,-0.65; VSS_20 1.3,-0.65; VSS_21 -1.3,-1.3; VSS_22 -0.65,-1.3; VSS_23 0,-1.3; VSS_24 0.65,-1.3; VSS_25 1.3,-1.3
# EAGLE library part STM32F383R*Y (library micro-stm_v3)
ARM 32-bit Cortex™-M3 CPU 72 MHz maximum frequency 64 to 256 Kbytes of Flash memory 16 to 32 kbytes of SRAM 51 GPIOs 1.8 to 3.6 V application supply

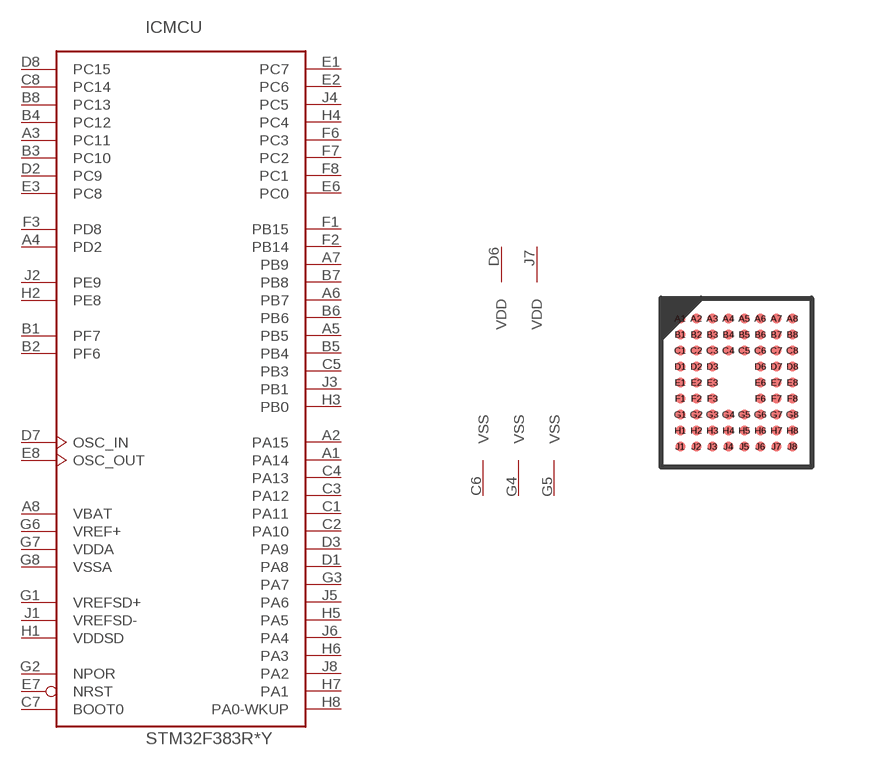
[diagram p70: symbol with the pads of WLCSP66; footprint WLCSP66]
Designator prefix IC; gates MCU=STM32_66PIN_TYP2 PWR=PWR_VDD2_VSS3

## STM32F383R8Y, STM32F383RBY, STM32F383RCY  [WLCSP66]
A1  MCU:PA14
A2  MCU:PA15
A3  MCU:PC11
A4  MCU:PD2
A5  MCU:PB5
A6  MCU:PB7
A7  MCU:PB9
A8  MCU:VBAT  pwr
B1  MCU:PF7
B2  MCU:PF6
B3  MCU:PC10
B4  MCU:PC12
B5  MCU:PB4
B6  MCU:PB6
B7  MCU:PB8
B8  MCU:PC13
C1  MCU:PA11
C2  MCU:PA10
C3  MCU:PA12
C4  MCU:PA13
C5  MCU:PB3
C6  PWR:VSS  pwr
C7  MCU:BOOT0  in
C8  MCU:PC14
D1  MCU:PA8
D2  MCU:PC9
D3  MCU:PA9
D6  PWR:VDD  pwr
D7  MCU:OSC_IN
D8  MCU:PC15
E1  MCU:PC7
E2  MCU:PC6
E3  MCU:PC8
E6  MCU:PC0
E7  MCU:NRST
E8  MCU:OSC_OUT
F1  MCU:PB15
F2  MCU:PB14
F3  MCU:PD8
F6  MCU:PC3
F7  MCU:PC2
F8  MCU:PC1
G1  MCU:VREFSD+  pwr
G2  MCU:NPOR  in
G3  MCU:PA7
G4  PWR:VSS  pwr
G5  PWR:VSS  pwr
G6  MCU:VREF+  pwr
G7  MCU:VDDA  pwr
G8  MCU:VSSA  pwr
H1  MCU:VDDSD  pwr
H2  MCU:PE8
H3  MCU:PB0
H4  MCU:PC4
H5  MCU:PA5
H6  MCU:PA3
H7  MCU:PA1
H8  MCU:PA0-WKUP
J1  MCU:VREFSD-  pwr
J2  MCU:PE9
J3  MCU:PB1
J4  MCU:PC5
J5  MCU:PA6
J6  MCU:PA4
J7  PWR:VDD  pwr
J8  MCU:PA2

## Footprint WLCSP66 (pad centres in mm)
WLCSP66 3.767 x 4.229 mm, 8 x 9-pin 0.4 mm pitch wafer-level chip-scale package
smd 0.25 x 0.25: A1 -1.4,1.6; A2 -1,1.6; A3 -0.6,1.6; A4 -0.2,1.6; A5 0.2,1.6; A6 0.6,1.6; A7 1,1.6; A8 1.4,1.6; B1 -1.4,1.2; B2 -1,1.2; B3 -0.6,1.2; B4 -0.2,1.2; B5 0.2,1.2; B6 0.6,1.2; B7 1,1.2; B8 1.4,1.2; C1 -1.4,0.8; C2 -1,0.8; C3 -0.6,0.8; C4 -0.2,0.8; C5 0.2,0.8; C6 0.6,0.8; C7 1,0.8; C8 1.4,0.8; D1 -1.4,0.4; D2 -1,0.4; D3 -0.6,0.4; D6 0.6,0.4; D7 1,0.4; D8 1.4,0.4; E1 -1.4,0; E2 -1,0; E3 -0.6,0; E6 0.6,0; E7 1,0; E8 1.4,0; F1 -1.4,-0.4; F2 -1,-0.4; F3 -0.6,-0.4; F6 0.6,-0.4; F7 1,-0.4; F8 1.4,-0.4; G1 -1.4,-0.8; G2 -1,-0.8; G3 -0.6,-0.8; G4 -0.2,-0.8; G5 0.2,-0.8; G6 0.6,-0.8; G7 1,-0.8; G8 1.4,-0.8; H1 -1.4,-1.2; H2 -1,-1.2; H3 -0.6,-1.2; H4 -0.2,-1.2; H5 0.2,-1.2; H6 0.6,-1.2; H7 1,-1.2; H8 1.4,-1.2; J1 -1.4,-1.6; J2 -1,-1.6; J3 -0.6,-1.6; J4 -0.2,-1.6; J5 0.2,-1.6; J6 0.6,-1.6; J7 1,-1.6; J8 1.4,-1.6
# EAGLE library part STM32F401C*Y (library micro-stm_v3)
ARM 32-bit Cortex™-M3 CPU 84 MHz maximum frequency 128 to 256 Kbytes of Flash memory 64 kbytes of SRAM 36 GPIOs 1.7 to 3.6 V application supply

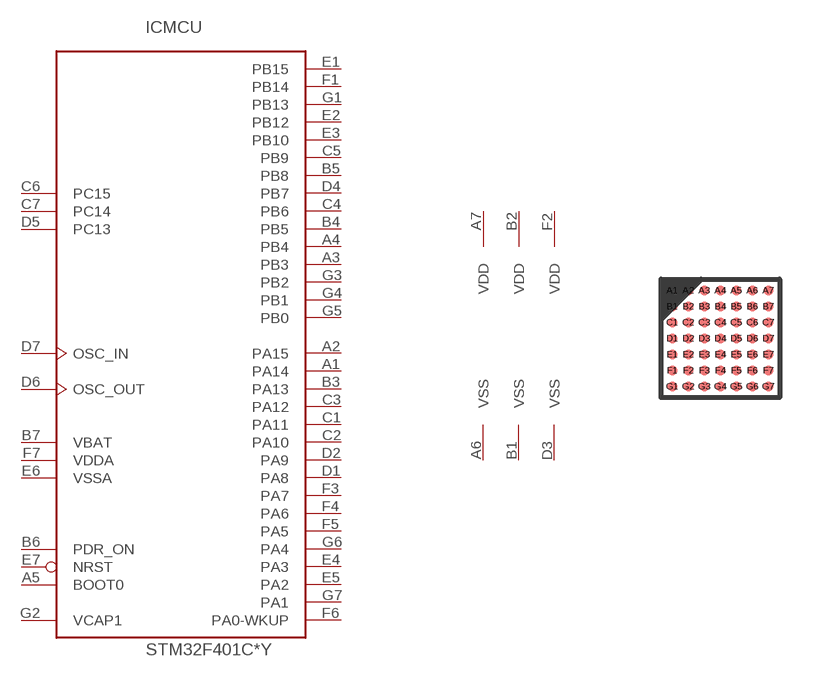
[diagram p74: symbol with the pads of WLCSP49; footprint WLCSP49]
Designator prefix IC; gates MCU=STM32_49PIN_TYP1 PWR=PWR_VDD3_VSS3

## STM32F401CBY, STM32F401CCY  [WLCSP49]
A1  MCU:PA14
A2  MCU:PA15
A3  MCU:PB3
A4  MCU:PB4
A5  MCU:BOOT0  in
A6  PWR:VSS  pwr
A7  PWR:VDD  pwr
B1  PWR:VSS  pwr
B2  PWR:VDD  pwr
B3  MCU:PA13
B4  MCU:PB5
B5  MCU:PB8
B6  MCU:PDR_ON  in
B7  MCU:VBAT  pwr
C1  MCU:PA11
C2  MCU:PA10
C3  MCU:PA12
C4  MCU:PB6
C5  MCU:PB9
C6  MCU:PC15
C7  MCU:PC14
D1  MCU:PA8
D2  MCU:PA9
D3  PWR:VSS  pwr
D4  MCU:PB7
D5  MCU:PC13
D6  MCU:OSC_OUT
D7  MCU:OSC_IN
E1  MCU:PB15
E2  MCU:PB12
E3  MCU:PB10
E4  MCU:PA3
E5  MCU:PA2
E6  MCU:VSSA  pwr
E7  MCU:NRST
F1  MCU:PB14
F2  PWR:VDD  pwr
F3  MCU:PA7
F4  MCU:PA6
F5  MCU:PA5
F6  MCU:PA0-WKUP
F7  MCU:VDDA  pwr
G1  MCU:PB13
G2  MCU:VCAP1  pwr
G3  MCU:PB2
G4  MCU:PB1
G5  MCU:PB0
G6  MCU:PA4
G7  MCU:PA1

## Footprint WLCSP49 (pad centres in mm)
WLCSP49 2.965 x 2.965 mm, 7 x 7-pin 0.4 mm pitch wafer-level chip-scale package
smd 0.25 x 0.25: A1 -1.2,1.2; A2 -0.8,1.2; A3 -0.4,1.2; A4 0,1.2; A5 0.4,1.2; A6 0.8,1.2; A7 1.2,1.2; B1 -1.2,0.8; B2 -0.8,0.8; B3 -0.4,0.8; B4 0,0.8; B5 0.4,0.8; B6 0.8,0.8; B7 1.2,0.8; C1 -1.2,0.4; C2 -0.8,0.4; C3 -0.4,0.4; C4 0,0.4; C5 0.4,0.4; C6 0.8,0.4; C7 1.2,0.4; D1 -1.2,0; D2 -0.8,0; D3 -0.4,0; D4 0,0; D5 0.4,0; D6 0.8,0; D7 1.2,0; E1 -1.2,-0.4; E2 -0.8,-0.4; E3 -0.4,-0.4; E4 0,-0.4; E5 0.4,-0.4; E6 0.8,-0.4; E7 1.2,-0.4; F1 -1.2,-0.8; F2 -0.8,-0.8; F3 -0.4,-0.8; F4 0,-0.8; F5 0.4,-0.8; F6 0.8,-0.8; F7 1.2,-0.8; G1 -1.2,-1.2; G2 -0.8,-1.2; G3 -0.4,-1.2; G4 0,-1.2; G5 0.4,-1.2; G6 0.8,-1.2; G7 1.2,-1.2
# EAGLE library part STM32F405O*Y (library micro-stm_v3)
ARM 32-bit Cortex™-M3 CPU 168 MHz maximum frequency 512 to 1024 Kbytes of Flash memory 192 kbytes of SRAM 72 GPIOs 1.8 to 3.6 V application supply

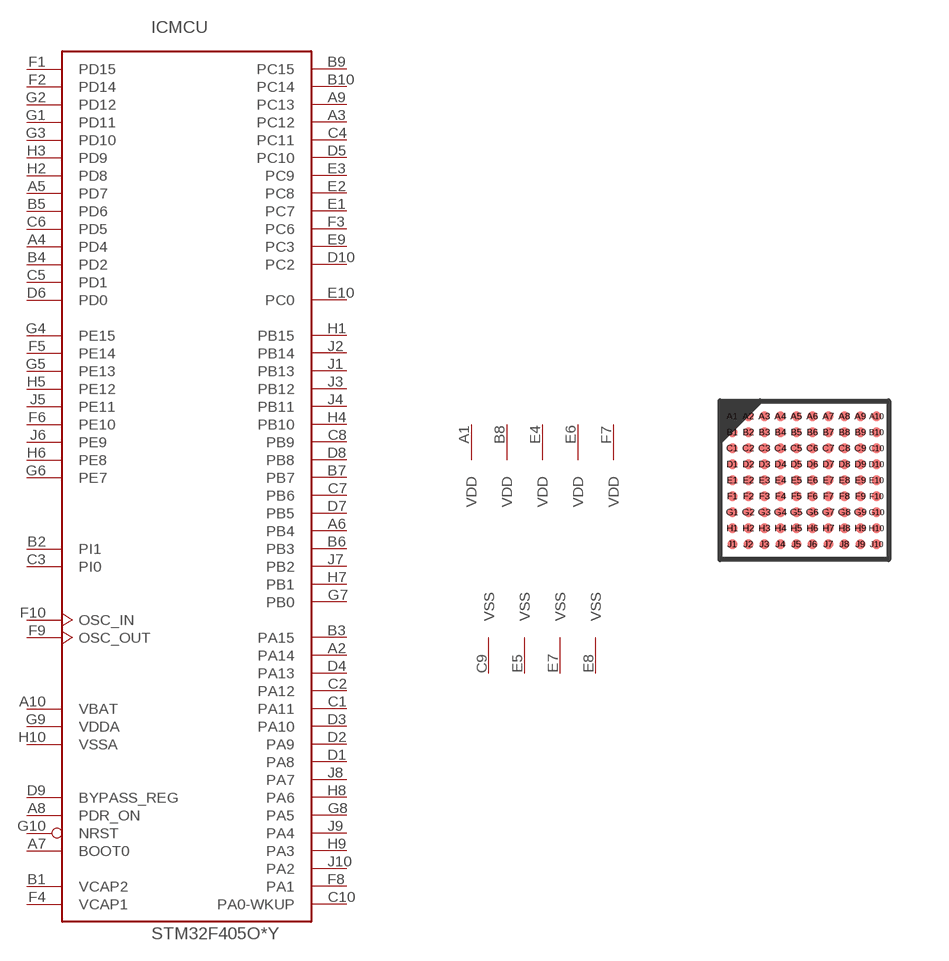
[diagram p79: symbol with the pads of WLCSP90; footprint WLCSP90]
Designator prefix IC; gates MCU=STM32_90PIN_TYP1 PWR=PWR_VDD5_VSS4

## STM32F405OEY, STM32F405OGY  [WLCSP90]
A1  PWR:VDD  pwr
A2  MCU:PA14
A3  MCU:PC12
A4  MCU:PD4
A5  MCU:PD7
A6  MCU:PB4
A7  MCU:BOOT0  in
A8  MCU:PDR_ON  in
A9  MCU:PC13
A10  MCU:VBAT  pwr
B1  MCU:VCAP2  pwr
B2  MCU:PI1
B3  MCU:PA15
B4  MCU:PD2
B5  MCU:PD6
B6  MCU:PB3
B7  MCU:PB7
B8  PWR:VDD  pwr
B9  MCU:PC15
B10  MCU:PC14
C1  MCU:PA11
C2  MCU:PA12
C3  MCU:PI0
C4  MCU:PC11
C5  MCU:PD1
C6  MCU:PD5
C7  MCU:PB6
C8  MCU:PB9
C9  PWR:VSS  pwr
C10  MCU:PA0-WKUP
D1  MCU:PA8
D2  MCU:PA9
D3  MCU:PA10
D4  MCU:PA13
D5  MCU:PC10
D6  MCU:PD0
D7  MCU:PB5
D8  MCU:PB8
D9  MCU:BYPASS_REG  in
D10  MCU:PC2
E1  MCU:PC7
E2  MCU:PC8
E3  MCU:PC9
E4  PWR:VDD  pwr
E5  PWR:VSS  pwr
E6  PWR:VDD  pwr
E7  PWR:VSS  pwr
E8  PWR:VSS  pwr
E9  MCU:PC3
E10  MCU:PC0
F1  MCU:PD15
F2  MCU:PD14
F3  MCU:PC6
F4  MCU:VCAP1  pwr
F5  MCU:PE14
F6  MCU:PE10
F7  PWR:VDD  pwr
F8  MCU:PA1
F9  MCU:OSC_OUT
F10  MCU:OSC_IN
G1  MCU:PD11
G2  MCU:PD12
G3  MCU:PD10
G4  MCU:PE15
G5  MCU:PE13
G6  MCU:PE7
G7  MCU:PB0
G8  MCU:PA5
G9  MCU:VDDA  pwr
G10  MCU:NRST
H1  MCU:PB15
H2  MCU:PD8
H3  MCU:PD9
H4  MCU:PB10
H5  MCU:PE12
H6  MCU:PE8
H7  MCU:PB1
H8  MCU:PA6
H9  MCU:PA3
H10  MCU:VSSA  pwr
J1  MCU:PB13
J2  MCU:PB14
J3  MCU:PB12
J4  MCU:PB11
J5  MCU:PE11
J6  MCU:PE9
J7  MCU:PB2
J8  MCU:PA7
J9  MCU:PA4
J10  MCU:PA2

## Footprint WLCSP90 (pad centres in mm)
WLCSP90 4.218 x 3.969 mm, 10 x 9-pin 0.4 mm pitch wafer-level chip-scale package
smd 0.25 x 0.25: A1 -1.8,1.6; A2 -1.4,1.6; A3 -1,1.6; A4 -0.6,1.6; A5 -0.2,1.6; A6 0.2,1.6; A7 0.6,1.6; A8 1,1.6; A9 1.4,1.6; A10 1.8,1.6; B1 -1.8,1.2; B2 -1.4,1.2; B3 -1,1.2; B4 -0.6,1.2; B5 -0.2,1.2; B6 0.2,1.2; B7 0.6,1.2; B8 1,1.2; B9 1.4,1.2; B10 1.8,1.2; C1 -1.8,0.8; C2 -1.4,0.8; C3 -1,0.8; C4 -0.6,0.8; C5 -0.2,0.8; C6 0.2,0.8; C7 0.6,0.8; C8 1,0.8; C9 1.4,0.8; C10 1.8,0.8; D1 -1.8,0.4; D2 -1.4,0.4; D3 -1,0.4; D4 -0.6,0.4; D5 -0.2,0.4; D6 0.2,0.4; D7 0.6,0.4; D8 1,0.4; D9 1.4,0.4; D10 1.8,0.4; E1 -1.8,0; E2 -1.4,0; E3 -1,0; E4 -0.6,0; E5 -0.2,0; E6 0.2,0; E7 0.6,0; E8 1,0; E9 1.4,0; E10 1.8,0; F1 -1.8,-0.4; F2 -1.4,-0.4; F3 -1,-0.4; F4 -0.6,-0.4; F5 -0.2,-0.4; F6 0.2,-0.4; F7 0.6,-0.4; F8 1,-0.4; F9 1.4,-0.4; F10 1.8,-0.4; G1 -1.8,-0.8; G2 -1.4,-0.8; G3 -1,-0.8; G4 -0.6,-0.8; G5 -0.2,-0.8; G6 0.2,-0.8; G7 0.6,-0.8; G8 1,-0.8; G9 1.4,-0.8; G10 1.8,-0.8; H1 -1.8,-1.2; H2 -1.4,-1.2; H3 -1,-1.2; H4 -0.6,-1.2; H5 -0.2,-1.2; H6 0.2,-1.2; H7 0.6,-1.2; H8 1,-1.2; H9 1.4,-1.2; H10 1.8,-1.2; J1 -1.8,-1.6; J2 -1.4,-1.6; J3 -1,-1.6; J4 -0.6,-1.6; J5 -0.2,-1.6; J6 0.2,-1.6; J7 0.6,-1.6; J8 1,-1.6; J9 1.4,-1.6; J10 1.8,-1.6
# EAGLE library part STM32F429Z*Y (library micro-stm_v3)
ARM 32-bit Cortex™-M3 CPU 180 MHz maximum frequency 1024 to 2048 Kbytes of Flash memory 256 kbytes of SRAM 114 GPIOs 1.8 to 3.6 V application supply

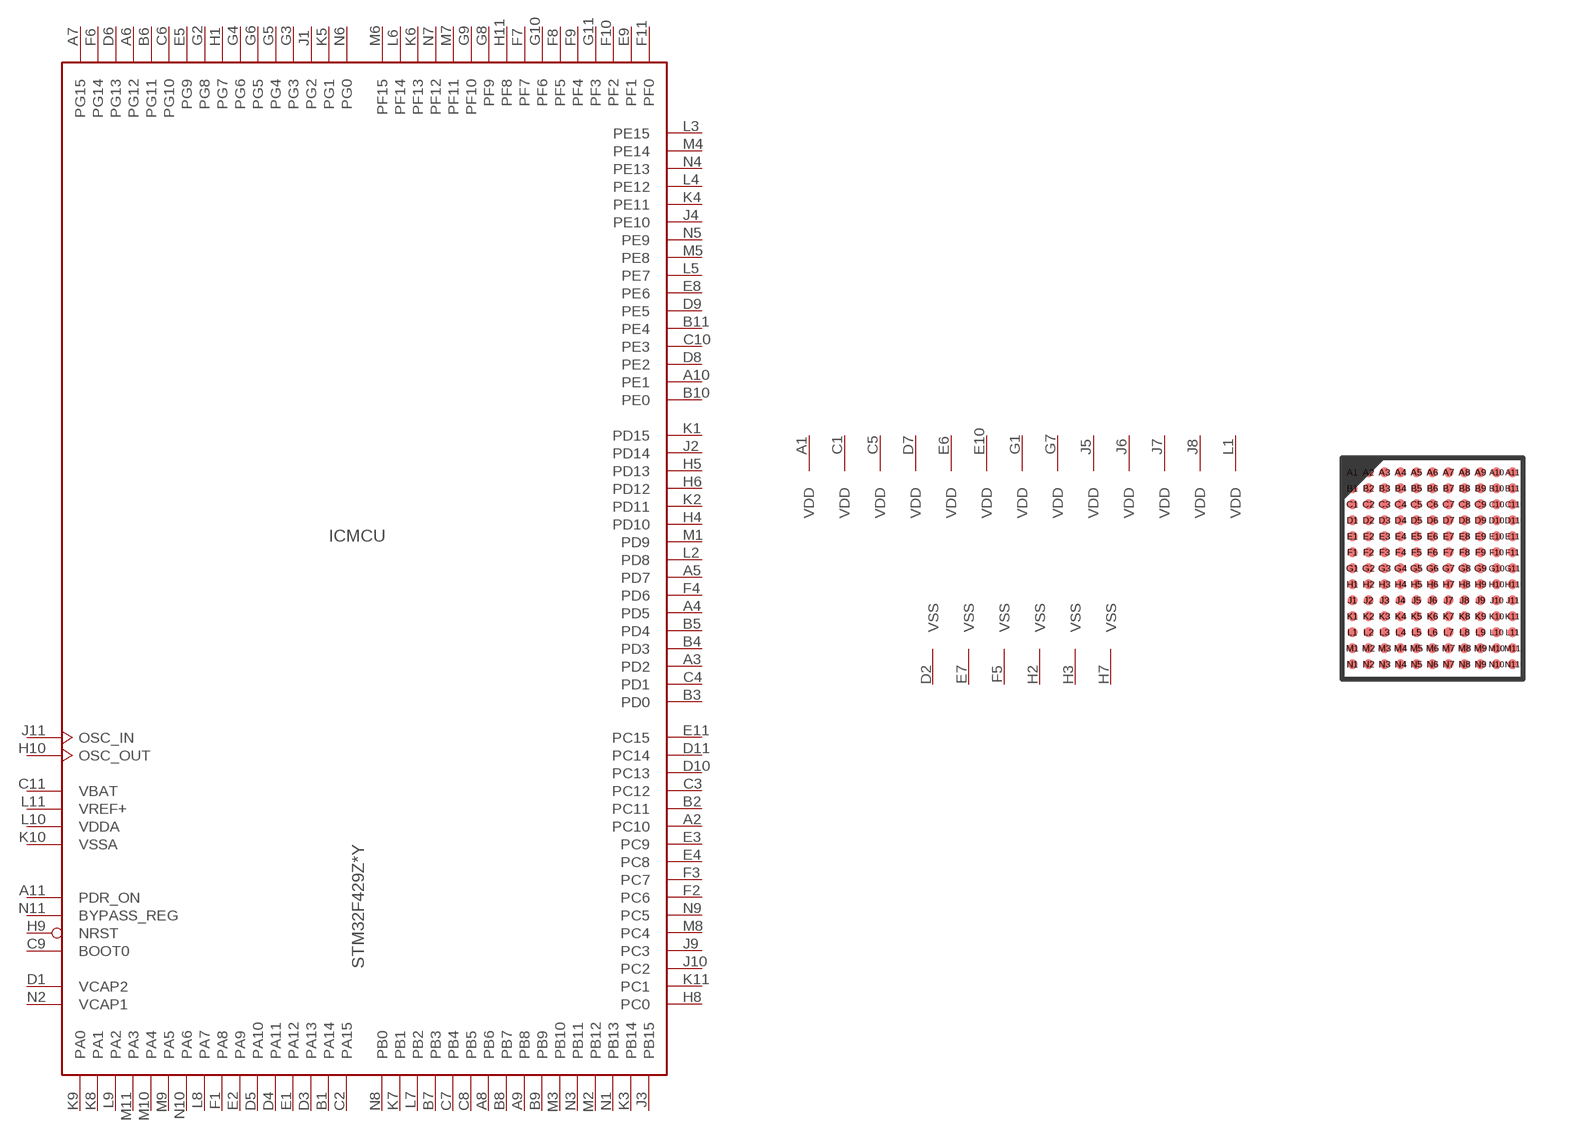
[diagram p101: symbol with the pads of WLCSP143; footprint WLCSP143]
Designator prefix IC; gates MCU=STM32_143PIN_TYP1 PWR=PWR_VDD13_VSS6

## STM32F429ZGY, STM32F429ZIY  [WLCSP143]
A1  PWR:VDD  pwr
A2  MCU:PC10
A3  MCU:PD2
A4  MCU:PD5
A5  MCU:PD7
A6  MCU:PG12
A7  MCU:PG15
A8  MCU:PB6
A9  MCU:PB8
A10  MCU:PE1
A11  MCU:PDR_ON  in
B1  MCU:PA14
B2  MCU:PC11
B3  MCU:PD0
B4  MCU:PD3
B5  MCU:PD4
B6  MCU:PG11
B7  MCU:PB3
B8  MCU:PB7
B9  MCU:PB9
B10  MCU:PE0
B11  MCU:PE4
C1  PWR:VDD  pwr
C2  MCU:PA15
C3  MCU:PC12
C4  MCU:PD1
C5  PWR:VDD  pwr
C6  MCU:PG10
C7  MCU:PB4
C8  MCU:PB5
C9  MCU:BOOT0  in
C10  MCU:PE3
C11  MCU:VBAT  pwr
D1  MCU:VCAP2  pwr
D2  PWR:VSS  pwr
D3  MCU:PA13
D4  MCU:PA11
D5  MCU:PA10
D6  MCU:PG13
D7  PWR:VDD  pwr
D8  MCU:PE2
D9  MCU:PE5
D10  MCU:PC13
D11  MCU:PC14
E1  MCU:PA12
E2  MCU:PA9
E3  MCU:PC9
E4  MCU:PC8
E5  MCU:PG9
E6  PWR:VDD  pwr
E7  PWR:VSS  pwr
E8  MCU:PE6
E9  MCU:PF1
E10  PWR:VDD  pwr
E11  MCU:PC15
F1  MCU:PA8
F2  MCU:PC6
F3  MCU:PC7
F4  MCU:PD6
F5  PWR:VSS  pwr
F6  MCU:PG14
F7  MCU:PF7
F8  MCU:PF5
F9  MCU:PF4
F10  MCU:PF2
F11  MCU:PF0
G1  PWR:VDD  pwr
G2  MCU:PG8
G3  MCU:PG3
G4  MCU:PG6
G5  MCU:PG4
G6  MCU:PG5
G7  PWR:VDD  pwr
G8  MCU:PF9
G9  MCU:PF10
G10  MCU:PF6
G11  MCU:PF3
H1  MCU:PG7
H2  PWR:VSS  pwr
H3  PWR:VSS  pwr
H4  MCU:PD10
H5  MCU:PD13
H6  MCU:PD12
H7  PWR:VSS  pwr
H8  MCU:PC0
H9  MCU:NRST
H10  MCU:OSC_OUT
H11  MCU:PF8
J1  MCU:PG2
J2  MCU:PD14
J3  MCU:PB15
J4  MCU:PE10
J5  PWR:VDD  pwr
J6  PWR:VDD  pwr
J7  PWR:VDD  pwr
J8  PWR:VDD  pwr
J9  MCU:PC3
J10  MCU:PC2
J11  MCU:OSC_IN
K1  MCU:PD15
K2  MCU:PD11
K3  MCU:PB14
K4  MCU:PE11
K5  MCU:PG1
K6  MCU:PF13
K7  MCU:PB1
K8  MCU:PA1
K9  MCU:PA0
K10  MCU:VSSA  pwr
K11  MCU:PC1
L1  PWR:VDD  pwr
L2  MCU:PD8
L3  MCU:PE15
L4  MCU:PE12
L5  MCU:PE7
L6  MCU:PF14
L7  MCU:PB2
L8  MCU:PA7
L9  MCU:PA2
L10  MCU:VDDA  pwr
L11  MCU:VREF+  pwr
M1  MCU:PD9
M2  MCU:PB12
M3  MCU:PB10
M4  MCU:PE14
M5  MCU:PE8
M6  MCU:PF15
M7  MCU:PF11
M8  MCU:PC4
M9  MCU:PA5
M10  MCU:PA4
M11  MCU:PA3
N1  MCU:PB13
N2  MCU:VCAP1  pwr
N3  MCU:PB11
N4  MCU:PE13
N5  MCU:PE9
N6  MCU:PG0
N7  MCU:PF12
N8  MCU:PB0
N9  MCU:PC5
N10  MCU:PA6
N11  MCU:BYPASS_REG  in

## Footprint WLCSP143 (pad centres in mm)
WLCSP143 4.521 x 5.547 mm, 11 x 13-pin 0.4 mm pitch wafer-level chip-scale package
smd 0.25 x 0.25: A1 -1.999,2.405; A2 -1.599,2.405; A3 -1.199,2.405; A4 -0.799,2.405; A5 -0.399,2.405; A6 0.001,2.405; A7 0.401,2.405; A8 0.801,2.405; A9 1.201,2.405; A10 1.601,2.405; A11 2.001,2.405; B1 -1.999,2.005; B2 -1.599,2.005; B3 -1.199,2.005; B4 -0.799,2.005; B5 -0.399,2.005; B6 0.001,2.005; B7 0.401,2.005; B8 0.801,2.005; B9 1.201,2.005; B10 1.601,2.005; B11 2.001,2.005; C1 -1.999,1.605; C2 -1.599,1.605; C3 -1.199,1.605; C4 -0.799,1.605; C5 -0.399,1.605; C6 0.001,1.605; C7 0.401,1.605; C8 0.801,1.605; C9 1.201,1.605; C10 1.601,1.605; C11 2.001,1.605; D1 -1.999,1.205; D2 -1.599,1.205; D3 -1.199,1.205; D4 -0.799,1.205; D5 -0.399,1.205; D6 0.001,1.205; D7 0.401,1.205; D8 0.801,1.205; D9 1.201,1.205; D10 1.601,1.205; D11 2.001,1.205; E1 -1.999,0.805; E2 -1.599,0.805; E3 -1.199,0.805; E4 -0.799,0.805; E5 -0.399,0.805; E6 0.001,0.805; E7 0.401,0.805; E8 0.801,0.805; E9 1.201,0.805; E10 1.601,0.805; E11 2.001,0.805; F1 -1.999,0.405; F2 -1.599,0.405; F3 -1.199,0.405; F4 -0.799,0.405; F5 -0.399,0.405; F6 0.001,0.405; F7 0.401,0.405; F8 0.801,0.405; F9 1.201,0.405; F10 1.601,0.405; F11 2.001,0.405; G1 -1.999,0.005; G2 -1.599,0.005; G3 -1.199,0.005; G4 -0.799,0.005; G5 -0.399,0.005; G6 0.001,0.005; G7 0.401,0.005; G8 0.801,0.005; G9 1.201,0.005; G10 1.601,0.005; G11 2.001,0.005; H1 -1.999,-0.395; H2 -1.599,-0.395; H3 -1.199,-0.395; H4 -0.799,-0.395; H5 -0.399,-0.395; H6 0.001,-0.395; H7 0.401,-0.395; H8 0.801,-0.395; H9 1.201,-0.395; H10 1.601,-0.395; H11 2.001,-0.395; J1 -1.999,-0.795; J2 -1.599,-0.795; J3 -1.199,-0.795; J4 -0.799,-0.795; J5 -0.399,-0.795; J6 0.001,-0.795; J7 0.401,-0.795; J8 0.801,-0.795; J9 1.201,-0.795; J10 1.601,-0.795; J11 2.001,-0.795; K1 -1.999,-1.195; K2 -1.599,-1.195; K3 -1.199,-1.195; K4 -0.799,-1.195; K5 -0.399,-1.195; K6 0.001,-1.195; K7 0.401,-1.195; K8 0.801,-1.195; K9 1.201,-1.195; K10 1.601,-1.195; K11 2.001,-1.195; L1 -1.999,-1.595; L2 -1.599,-1.595; L3 -1.199,-1.595; L4 -0.799,-1.595; L5 -0.399,-1.595; L6 0.001,-1.595; L7 0.401,-1.595; L8 0.801,-1.595; L9 1.201,-1.595; L10 1.601,-1.595; L11 2.001,-1.595; M1 -1.999,-1.995; M2 -1.599,-1.995; M3 -1.199,-1.995; M4 -0.799,-1.995; M5 -0.399,-1.995; M6 0.001,-1.995; M7 0.401,-1.995; M8 0.801,-1.995; M9 1.201,-1.995; M10 1.601,-1.995; M11 2.001,-1.995; N1 -1.999,-2.395; N2 -1.599,-2.395; N3 -1.199,-2.395; N4 -0.799,-2.395; N5 -0.399,-2.395; N6 0.001,-2.395; N7 0.401,-2.395; N8 0.801,-2.395; N9 1.201,-2.395; N10 1.601,-2.395; N11 2.001,-2.395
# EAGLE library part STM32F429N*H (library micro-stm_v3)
ARM 32-bit Cortex™-M3 CPU 180 MHz maximum frequency 1024 to 2048 Kbytes of Flash memory 256 kbytes of SRAM 168 GPIOs 1.8 to 3.6 V application supply

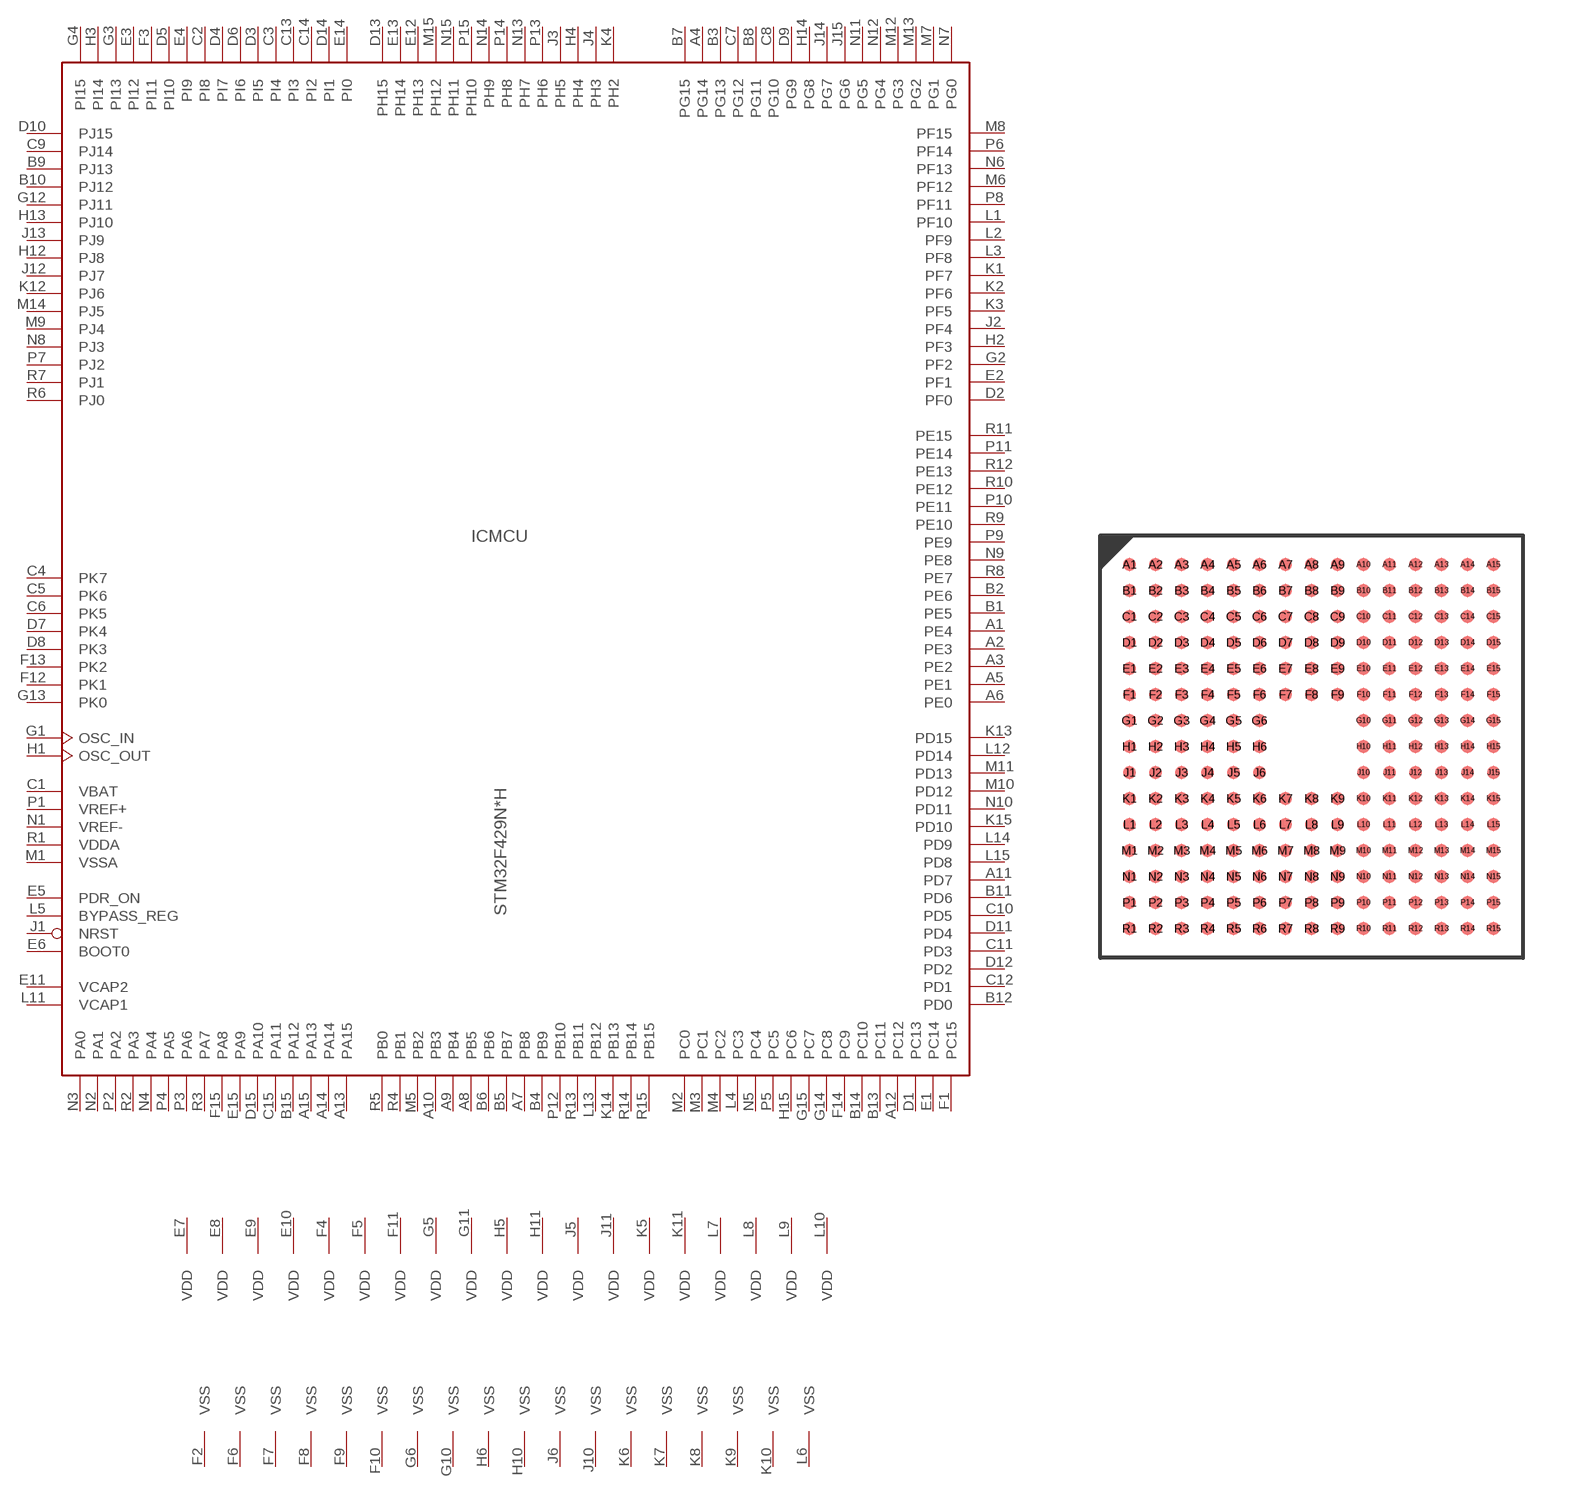
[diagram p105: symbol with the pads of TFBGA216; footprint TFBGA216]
Designator prefix IC; gates MCU=STM32_216PIN_TYP1 PWR=PWR_VDD19_VSS18

## STM32F429NGH, STM32F429NIH  [TFBGA216]
A1  MCU:PE4
A2  MCU:PE3
A3  MCU:PE2
A4  MCU:PG14
A5  MCU:PE1
A6  MCU:PE0
A7  MCU:PB8
A8  MCU:PB5
A9  MCU:PB4
A10  MCU:PB3
A11  MCU:PD7
A12  MCU:PC12
A13  MCU:PA15
A14  MCU:PA14
A15  MCU:PA13
B1  MCU:PE5
B2  MCU:PE6
B3  MCU:PG13
B4  MCU:PB9
B5  MCU:PB7
B6  MCU:PB6
B7  MCU:PG15
B8  MCU:PG11
B9  MCU:PJ13
B10  MCU:PJ12
B11  MCU:PD6
B12  MCU:PD0
B13  MCU:PC11
B14  MCU:PC10
B15  MCU:PA12
C1  MCU:VBAT  pwr
C2  MCU:PI8
C3  MCU:PI4
C4  MCU:PK7
C5  MCU:PK6
C6  MCU:PK5
C7  MCU:PG12
C8  MCU:PG10
C9  MCU:PJ14
C10  MCU:PD5
C11  MCU:PD3
C12  MCU:PD1
C13  MCU:PI3
C14  MCU:PI2
C15  MCU:PA11
D1  MCU:PC13
D2  MCU:PF0
D3  MCU:PI5
D4  MCU:PI7
D5  MCU:PI10
D6  MCU:PI6
D7  MCU:PK4
D8  MCU:PK3
D9  MCU:PG9
D10  MCU:PJ15
D11  MCU:PD4
D12  MCU:PD2
D13  MCU:PH15
D14  MCU:PI1
D15  MCU:PA10
E1  MCU:PC14
E2  MCU:PF1
E3  MCU:PI12
E4  MCU:PI9
E5  MCU:PDR_ON  in
E6  MCU:BOOT0  in
E7  PWR:VDD  pwr
E8  PWR:VDD  pwr
E9  PWR:VDD  pwr
E10  PWR:VDD  pwr
E11  MCU:VCAP2  pwr
E12  MCU:PH13
E13  MCU:PH14
E14  MCU:PI0
E15  MCU:PA9
F1  MCU:PC15
F2  PWR:VSS  pwr
F3  MCU:PI11
F4  PWR:VDD  pwr
F5  PWR:VDD  pwr
F6  PWR:VSS  pwr
F7  PWR:VSS  pwr
F8  PWR:VSS  pwr
F9  PWR:VSS  pwr
F10  PWR:VSS  pwr
F11  PWR:VDD  pwr
F12  MCU:PK1
F13  MCU:PK2
F14  MCU:PC9
F15  MCU:PA8
G1  MCU:OSC_IN
G2  MCU:PF2
G3  MCU:PI13
G4  MCU:PI15
G5  PWR:VDD  pwr
G6  PWR:VSS  pwr
G10  PWR:VSS  pwr
G11  PWR:VDD  pwr
G12  MCU:PJ11
G13  MCU:PK0
G14  MCU:PC8
G15  MCU:PC7
H1  MCU:OSC_OUT
H2  MCU:PF3
H3  MCU:PI14
H4  MCU:PH4
H5  PWR:VDD  pwr
H6  PWR:VSS  pwr
H10  PWR:VSS  pwr
H11  PWR:VDD  pwr
H12  MCU:PJ8
H13  MCU:PJ10
H14  MCU:PG8
H15  MCU:PC6
J1  MCU:NRST
J2  MCU:PF4
J3  MCU:PH5
J4  MCU:PH3
J5  PWR:VDD  pwr
J6  PWR:VSS  pwr
J10  PWR:VSS  pwr
J11  PWR:VDD  pwr
J12  MCU:PJ7
J13  MCU:PJ9
J14  MCU:PG7
J15  MCU:PG6
K1  MCU:PF7
K2  MCU:PF6
K3  MCU:PF5
K4  MCU:PH2
K5  PWR:VDD  pwr
K6  PWR:VSS  pwr
K7  PWR:VSS  pwr
K8  PWR:VSS  pwr
K9  PWR:VSS  pwr
K10  PWR:VSS  pwr
K11  PWR:VDD  pwr
K12  MCU:PJ6
K13  MCU:PD15
K14  MCU:PB13
K15  MCU:PD10
L1  MCU:PF10
L2  MCU:PF9
L3  MCU:PF8
L4  MCU:PC3
L5  MCU:BYPASS_REG  in
L6  PWR:VSS  pwr
L7  PWR:VDD  pwr
L8  PWR:VDD  pwr
L9  PWR:VDD  pwr
L10  PWR:VDD  pwr
L11  MCU:VCAP1  pwr
L12  MCU:PD14
L13  MCU:PB12
L14  MCU:PD9
L15  MCU:PD8
M1  MCU:VSSA  pwr
M2  MCU:PC0
M3  MCU:PC1
M4  MCU:PC2
M5  MCU:PB2
M6  MCU:PF12
M7  MCU:PG1
M8  MCU:PF15
M9  MCU:PJ4
M10  MCU:PD12
M11  MCU:PD13
M12  MCU:PG3
M13  MCU:PG2
M14  MCU:PJ5
M15  MCU:PH12
N1  MCU:VREF-  pwr
N2  MCU:PA1
N3  MCU:PA0
N4  MCU:PA4
N5  MCU:PC4
N6  MCU:PF13
N7  MCU:PG0
N8  MCU:PJ3
N9  MCU:PE8
N10  MCU:PD11
N11  MCU:PG5
N12  MCU:PG4
N13  MCU:PH7
N14  MCU:PH9
N15  MCU:PH11
P1  MCU:VREF+  pwr
P2  MCU:PA2
P3  MCU:PA6
P4  MCU:PA5
P5  MCU:PC5
P6  MCU:PF14
P7  MCU:PJ2
P8  MCU:PF11
P9  MCU:PE9
P10  MCU:PE11
P11  MCU:PE14
P12  MCU:PB10
P13  MCU:PH6
P14  MCU:PH8
P15  MCU:PH10
R1  MCU:VDDA  pwr
R2  MCU:PA3
R3  MCU:PA7
R4  MCU:PB1
R5  MCU:PB0
R6  MCU:PJ0
R7  MCU:PJ1
R8  MCU:PE7
R9  MCU:PE10
R10  MCU:PE12
R11  MCU:PE15
R12  MCU:PE13
R13  MCU:PB11
R14  MCU:PB14
R15  MCU:PB15

## Footprint TFBGA216 (pad centres in mm)
TFBGA216 13 x 13 mm, 15 x 15-pin thin fine 0.8 mm pitch ball grid array package
smd 0.4 x 0.4: A1 -5.6,5.6; A2 -4.8,5.6; A3 -4,5.6; A4 -3.2,5.6; A5 -2.4,5.6; A6 -1.6,5.6; A7 -0.8,5.6; A8 0,5.6; A9 0.8,5.6; A10 1.6,5.6; A11 2.4,5.6; A12 3.2,5.6; A13 4,5.6; A14 4.8,5.6; A15 5.6,5.6; B1 -5.6,4.8; B2 -4.8,4.8; B3 -4,4.8; B4 -3.2,4.8; B5 -2.4,4.8; B6 -1.6,4.8; B7 -0.8,4.8; B8 0,4.8; B9 0.8,4.8; B10 1.6,4.8; B11 2.4,4.8; B12 3.2,4.8; B13 4,4.8; B14 4.8,4.8; B15 5.6,4.8; C1 -5.6,4; C2 -4.8,4; C3 -4,4; C4 -3.2,4; C5 -2.4,4; C6 -1.6,4; C7 -0.8,4; C8 0,4; C9 0.8,4; C10 1.6,4; C11 2.4,4; C12 3.2,4; C13 4,4; C14 4.8,4; C15 5.6,4; D1 -5.6,3.2; D2 -4.8,3.2; D3 -4,3.2; D4 -3.2,3.2; D5 -2.4,3.2; D6 -1.6,3.2; D7 -0.8,3.2; D8 0,3.2; D9 0.8,3.2; D10 1.6,3.2; D11 2.4,3.2; D12 3.2,3.2; D13 4,3.2; D14 4.8,3.2; D15 5.6,3.2; E1 -5.6,2.4; E2 -4.8,2.4; E3 -4,2.4; E4 -3.2,2.4; E5 -2.4,2.4; E6 -1.6,2.4; E7 -0.8,2.4; E8 0,2.4; E9 0.8,2.4; E10 1.6,2.4; E11 2.4,2.4; E12 3.2,2.4; E13 4,2.4; E14 4.8,2.4; E15 5.6,2.4; F1 -5.6,1.6; F2 -4.8,1.6; F3 -4,1.6; F4 -3.2,1.6; F5 -2.4,1.6; F6 -1.6,1.6; F7 -0.8,1.6; F8 0,1.6; F9 0.8,1.6; F10 1.6,1.6; F11 2.4,1.6; F12 3.2,1.6; F13 4,1.6; F14 4.8,1.6; F15 5.6,1.6; G1 -5.6,0.8; G2 -4.8,0.8; G3 -4,0.8; G4 -3.2,0.8; G5 -2.4,0.8; G6 -1.6,0.8; G10 1.6,0.8; G11 2.4,0.8; G12 3.2,0.8; G13 4,0.8; G14 4.8,0.8; G15 5.6,0.8; H1 -5.6,0; H2 -4.8,0; H3 -4,0; H4 -3.2,0; H5 -2.4,0; H6 -1.6,0; H10 1.6,0; H11 2.4,0; H12 3.2,0; H13 4,0; H14 4.8,0; H15 5.6,0; J1 -5.6,-0.8; J2 -4.8,-0.8; J3 -4,-0.8; J4 -3.2,-0.8; J5 -2.4,-0.8; J6 -1.6,-0.8; J10 1.6,-0.8; J11 2.4,-0.8; J12 3.2,-0.8; J13 4,-0.8; J14 4.8,-0.8; J15 5.6,-0.8; K1 -5.6,-1.6; K2 -4.8,-1.6; K3 -4,-1.6; K4 -3.2,-1.6; K5 -2.4,-1.6; K6 -1.6,-1.6; K7 -0.8,-1.6; K8 0,-1.6; K9 0.8,-1.6; K10 1.6,-1.6; K11 2.4,-1.6; K12 3.2,-1.6; K13 4,-1.6; K14 4.8,-1.6; K15 5.6,-1.6; L1 -5.6,-2.4; L2 -4.8,-2.4; L3 -4,-2.4; L4 -3.2,-2.4; L5 -2.4,-2.4; L6 -1.6,-2.4; L7 -0.8,-2.4; L8 0,-2.4; L9 0.8,-2.4; L10 1.6,-2.4; L11 2.4,-2.4; L12 3.2,-2.4; L13 4,-2.4; L14 4.8,-2.4; L15 5.6,-2.4; M1 -5.6,-3.2; M2 -4.8,-3.2; M3 -4,-3.2; M4 -3.2,-3.2; M5 -2.4,-3.2; M6 -1.6,-3.2; M7 -0.8,-3.2; M8 0,-3.2; M9 0.8,-3.2; M10 1.6,-3.2; M11 2.4,-3.2; M12 3.2,-3.2; M13 4,-3.2; M14 4.8,-3.2; M15 5.6,-3.2; N1 -5.6,-4; N2 -4.8,-4; N3 -4,-4; N4 -3.2,-4; N5 -2.4,-4; N6 -1.6,-4; N7 -0.8,-4; N8 0,-4; N9 0.8,-4; N10 1.6,-4; N11 2.4,-4; N12 3.2,-4; N13 4,-4; N14 4.8,-4; N15 5.6,-4; P1 -5.6,-4.8; P2 -4.8,-4.8; P3 -4,-4.8; P4 -3.2,-4.8; P5 -2.4,-4.8; P6 -1.6,-4.8; P7 -0.8,-4.8; P8 0,-4.8; P9 0.8,-4.8; P10 1.6,-4.8; P11 2.4,-4.8; P12 3.2,-4.8; P13 4,-4.8; P14 4.8,-4.8; P15 5.6,-4.8; R1 -5.6,-5.6; R2 -4.8,-5.6; R3 -4,-5.6; R4 -3.2,-5.6; R5 -2.4,-5.6; R6 -1.6,-5.6; R7 -0.8,-5.6; R8 0,-5.6; R9 0.8,-5.6; R10 1.6,-5.6; R11 2.4,-5.6; R12 3.2,-5.6; R13 4,-5.6; R14 4.8,-5.6; R15 5.6,-5.6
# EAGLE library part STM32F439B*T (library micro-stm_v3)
ARM 32-bit Cortex™-M3 CPU 180 MHz maximum frequency 1024 to 2048 Kbytes of Flash memory 256 kbytes of SRAM 168 GPIOs 1.8 to 3.6 V application supply

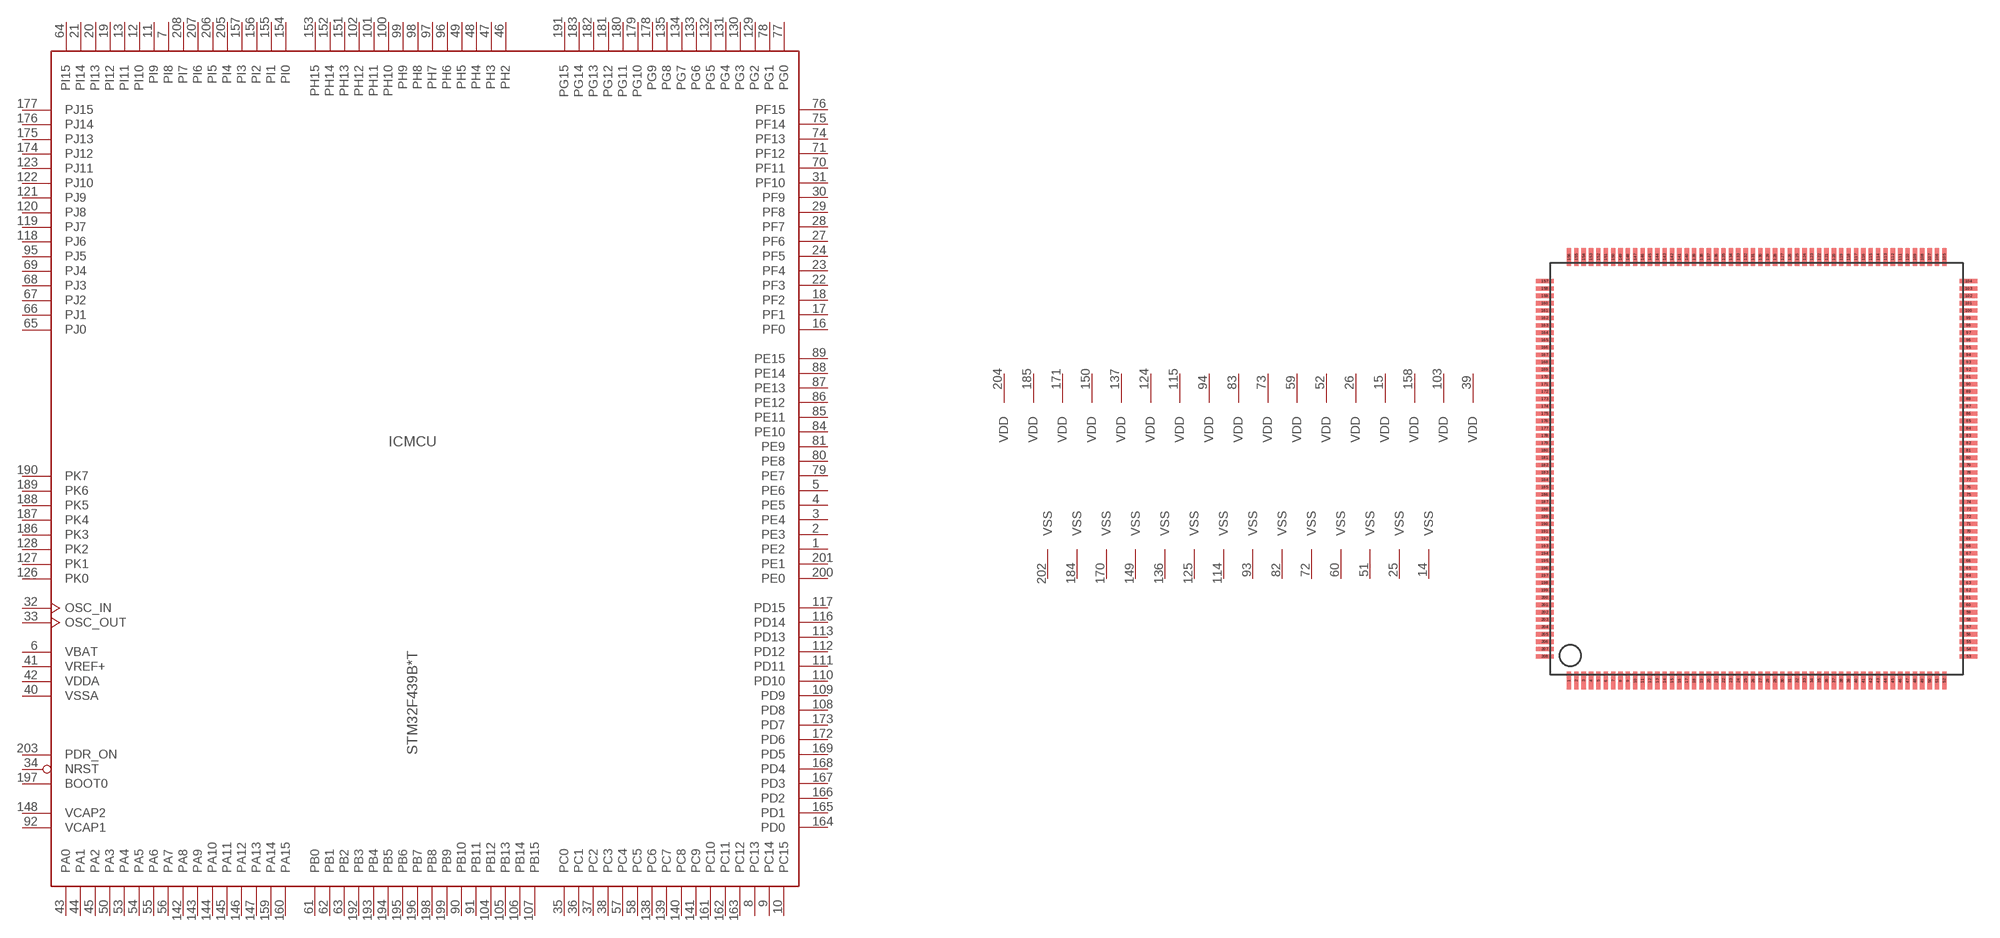
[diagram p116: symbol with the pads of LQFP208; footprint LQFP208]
Designator prefix IC; gates MCU=STM32_208PIN_TYP1 PWR=PWR_VDD17_VSS14

## STM32F439BGT, STM32F439BIT  [LQFP208]
1  MCU:PE2
2  MCU:PE3
3  MCU:PE4
4  MCU:PE5
5  MCU:PE6
6  MCU:VBAT  pwr
7  MCU:PI8
8  MCU:PC13
9  MCU:PC14
10  MCU:PC15
11  MCU:PI9
12  MCU:PI10
13  MCU:PI11
14  PWR:VSS  pwr
15  PWR:VDD  pwr
16  MCU:PF0
17  MCU:PF1
18  MCU:PF2
19  MCU:PI12
20  MCU:PI13
21  MCU:PI14
22  MCU:PF3
23  MCU:PF4
24  MCU:PF5
25  PWR:VSS  pwr
26  PWR:VDD  pwr
27  MCU:PF6
28  MCU:PF7
29  MCU:PF8
30  MCU:PF9
31  MCU:PF10
32  MCU:OSC_IN
33  MCU:OSC_OUT
34  MCU:NRST
35  MCU:PC0
36  MCU:PC1
37  MCU:PC2
38  MCU:PC3
39  PWR:VDD  pwr
40  MCU:VSSA  pwr
41  MCU:VREF+  pwr
42  MCU:VDDA  pwr
43  MCU:PA0
44  MCU:PA1
45  MCU:PA2
46  MCU:PH2
47  MCU:PH3
48  MCU:PH4
49  MCU:PH5
50  MCU:PA3
51  PWR:VSS  pwr
52  PWR:VDD  pwr
53  MCU:PA4
54  MCU:PA5
55  MCU:PA6
56  MCU:PA7
57  MCU:PC4
58  MCU:PC5
59  PWR:VDD  pwr
60  PWR:VSS  pwr
61  MCU:PB0
62  MCU:PB1
63  MCU:PB2
64  MCU:PI15
65  MCU:PJ0
66  MCU:PJ1
67  MCU:PJ2
68  MCU:PJ3
69  MCU:PJ4
70  MCU:PF11
71  MCU:PF12
72  PWR:VSS  pwr
73  PWR:VDD  pwr
74  MCU:PF13
75  MCU:PF14
76  MCU:PF15
77  MCU:PG0
78  MCU:PG1
79  MCU:PE7
80  MCU:PE8
81  MCU:PE9
82  PWR:VSS  pwr
83  PWR:VDD  pwr
84  MCU:PE10
85  MCU:PE11
86  MCU:PE12
87  MCU:PE13
88  MCU:PE14
89  MCU:PE15
90  MCU:PB10
91  MCU:PB11
92  MCU:VCAP1  pwr
93  PWR:VSS  pwr
94  PWR:VDD  pwr
95  MCU:PJ5
96  MCU:PH6
97  MCU:PH7
98  MCU:PH8
99  MCU:PH9
100  MCU:PH10
101  MCU:PH11
102  MCU:PH12
103  PWR:VDD  pwr
104  MCU:PB12
105  MCU:PB13
106  MCU:PB14
107  MCU:PB15
108  MCU:PD8
109  MCU:PD9
110  MCU:PD10
111  MCU:PD11
112  MCU:PD12
113  MCU:PD13
114  PWR:VSS  pwr
115  PWR:VDD  pwr
116  MCU:PD14
117  MCU:PD15
118  MCU:PJ6
119  MCU:PJ7
120  MCU:PJ8
121  MCU:PJ9
122  MCU:PJ10
123  MCU:PJ11
124  PWR:VDD  pwr
125  PWR:VSS  pwr
126  MCU:PK0
127  MCU:PK1
128  MCU:PK2
129  MCU:PG2
130  MCU:PG3
131  MCU:PG4
132  MCU:PG5
133  MCU:PG6
134  MCU:PG7
135  MCU:PG8
136  PWR:VSS  pwr
137  PWR:VDD  pwr
138  MCU:PC6
139  MCU:PC7
140  MCU:PC8
141  MCU:PC9
142  MCU:PA8
143  MCU:PA9
144  MCU:PA10
145  MCU:PA11
146  MCU:PA12
147  MCU:PA13
148  MCU:VCAP2  pwr
149  PWR:VSS  pwr
150  PWR:VDD  pwr
151  MCU:PH13
152  MCU:PH14
153  MCU:PH15
154  MCU:PI0
155  MCU:PI1
156  MCU:PI2
157  MCU:PI3
158  PWR:VDD  pwr
159  MCU:PA14
160  MCU:PA15
161  MCU:PC10
162  MCU:PC11
163  MCU:PC12
164  MCU:PD0
165  MCU:PD1
166  MCU:PD2
167  MCU:PD3
168  MCU:PD4
169  MCU:PD5
170  PWR:VSS  pwr
171  PWR:VDD  pwr
172  MCU:PD6
173  MCU:PD7
174  MCU:PJ12
175  MCU:PJ13
176  MCU:PJ14
177  MCU:PJ15
178  MCU:PG9
179  MCU:PG10
180  MCU:PG11
181  MCU:PG12
182  MCU:PG13
183  MCU:PG14
184  PWR:VSS  pwr
185  PWR:VDD  pwr
186  MCU:PK3
187  MCU:PK4
188  MCU:PK5
189  MCU:PK6
190  MCU:PK7
191  MCU:PG15
192  MCU:PB3
193  MCU:PB4
194  MCU:PB5
195  MCU:PB6
196  MCU:PB7
197  MCU:BOOT0  in
198  MCU:PB8
199  MCU:PB9
200  MCU:PE0
201  MCU:PE1
202  PWR:VSS  pwr
203  MCU:PDR_ON  in
204  PWR:VDD  pwr
205  MCU:PI4
206  MCU:PI5
207  MCU:PI6
208  MCU:PI7

## Footprint LQFP208 (pad centres in mm)
LQFP208 28 x 28 mm, 208-pin low-profile quad flat package
smd 0.3 x 1.2: 1 -12.75,-14.4; 2 -12.25,-14.4; 3 -11.75,-14.4; 4 -11.25,-14.4; 5 -10.75,-14.4; 6 -10.25,-14.4; 7 -9.75,-14.4; 8 -9.25,-14.4; 9 -8.75,-14.4; 10 -8.25,-14.4; 11 -7.75,-14.4; 12 -7.25,-14.4; 13 -6.75,-14.4; 14 -6.25,-14.4; 15 -5.75,-14.4; 16 -5.25,-14.4; 17 -4.75,-14.4; 18 -4.25,-14.4; 19 -3.75,-14.4; 20 -3.25,-14.4; 21 -2.75,-14.4; 22 -2.25,-14.4; 23 -1.75,-14.4; 24 -1.25,-14.4; 25 -0.75,-14.4; 26 -0.25,-14.4; 27 0.25,-14.4; 28 0.75,-14.4; 29 1.25,-14.4; 30 1.75,-14.4; 31 2.25,-14.4; 32 2.75,-14.4; 33 3.25,-14.4; 34 3.75,-14.4; 35 4.25,-14.4; 36 4.75,-14.4; 37 5.25,-14.4; 38 5.75,-14.4; 39 6.25,-14.4; 40 6.75,-14.4; 41 7.25,-14.4; 42 7.75,-14.4; 43 8.25,-14.4; 44 8.75,-14.4; 45 9.25,-14.4; 46 9.75,-14.4; 47 10.25,-14.4; 48 10.75,-14.4; 49 11.25,-14.4; 50 11.75,-14.4; 51 12.25,-14.4; 52 12.75,-14.4; 105 12.75,14.4; 106 12.25,14.4; 107 11.75,14.4; 108 11.25,14.4; 109 10.75,14.4; 110 10.25,14.4; 111 9.75,14.4; 112 9.25,14.4; 113 8.75,14.4; 114 8.25,14.4; 115 7.75,14.4; 116 7.25,14.4; 117 6.75,14.4; 118 6.25,14.4; 119 5.75,14.4; 120 5.25,14.4; 121 4.75,14.4; 122 4.25,14.4; 123 3.75,14.4; 124 3.25,14.4; 125 2.75,14.4; 126 2.25,14.4; 127 1.75,14.4; 128 1.25,14.4; 129 0.75,14.4; 130 0.25,14.4; 131 -0.25,14.4; 132 -0.75,14.4; 133 -1.25,14.4; 134 -1.75,14.4; 135 -2.25,14.4; 136 -2.75,14.4; 137 -3.25,14.4; 138 -3.75,14.4; 139 -4.25,14.4; 140 -4.75,14.4; 141 -5.25,14.4; 142 -5.75,14.4; 143 -6.25,14.4; 144 -6.75,14.4; 145 -7.25,14.4; 146 -7.75,14.4; 147 -8.25,14.4; 148 -8.75,14.4; 149 -9.25,14.4; 150 -9.75,14.4; 151 -10.25,14.4; 152 -10.75,14.4; 153 -11.25,14.4; 154 -11.75,14.4; 155 -12.25,14.4; 156 -12.75,14.4
smd 1.2 x 0.3: 53 14.4,-12.75; 54 14.4,-12.25; 55 14.4,-11.75; 56 14.4,-11.25; 57 14.4,-10.75; 58 14.4,-10.25; 59 14.4,-9.75; 60 14.4,-9.25; 61 14.4,-8.75; 62 14.4,-8.25; 63 14.4,-7.75; 64 14.4,-7.25; 65 14.4,-6.75; 66 14.4,-6.25; 67 14.4,-5.75; 68 14.4,-5.25; 69 14.4,-4.75; 70 14.4,-4.25; 71 14.4,-3.75; 72 14.4,-3.25; 73 14.4,-2.75; 74 14.4,-2.25; 75 14.4,-1.75; 76 14.4,-1.25; 77 14.4,-0.75; 78 14.4,-0.25; 79 14.4,0.25; 80 14.4,0.75; 81 14.4,1.25; 82 14.4,1.75; 83 14.4,2.25; 84 14.4,2.75; 85 14.4,3.25; 86 14.4,3.75; 87 14.4,4.25; 88 14.4,4.75; 89 14.4,5.25; 90 14.4,5.75; 91 14.4,6.25; 92 14.4,6.75; 93 14.4,7.25; 94 14.4,7.75; 95 14.4,8.25; 96 14.4,8.75; 97 14.4,9.25; 98 14.4,9.75; 99 14.4,10.25; 100 14.4,10.75; 101 14.4,11.25; 102 14.4,11.75; 103 14.4,12.25; 104 14.4,12.75; 157 -14.4,12.75; 158 -14.4,12.25; 159 -14.4,11.75; 160 -14.4,11.25; 161 -14.4,10.75; 162 -14.4,10.25; 163 -14.4,9.75; 164 -14.4,9.25; 165 -14.4,8.75; 166 -14.4,8.25; 167 -14.4,7.75; 168 -14.4,7.25; 169 -14.4,6.75; 170 -14.4,6.25; 171 -14.4,5.75; 172 -14.4,5.25; 173 -14.4,4.75; 174 -14.4,4.25; 175 -14.4,3.75; 176 -14.4,3.25; 177 -14.4,2.75; 178 -14.4,2.25; 179 -14.4,1.75; 180 -14.4,1.25; 181 -14.4,0.75; 182 -14.4,0.25; 183 -14.4,-0.25; 184 -14.4,-0.75; 185 -14.4,-1.25; 186 -14.4,-1.75; 187 -14.4,-2.25; 188 -14.4,-2.75; 189 -14.4,-3.25; 190 -14.4,-3.75; 191 -14.4,-4.25; 192 -14.4,-4.75; 193 -14.4,-5.25; 194 -14.4,-5.75; 195 -14.4,-6.25; 196 -14.4,-6.75; 197 -14.4,-7.25; 198 -14.4,-7.75; 199 -14.4,-8.25; 200 -14.4,-8.75; 201 -14.4,-9.25; 202 -14.4,-9.75; 203 -14.4,-10.25; 204 -14.4,-10.75; 205 -14.4,-11.25; 206 -14.4,-11.75; 207 -14.4,-12.25; 208 -14.4,-12.75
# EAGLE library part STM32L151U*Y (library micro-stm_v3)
ARM 32-bit Cortex™-M3 CPU 32 MHz maximum frequency 256 Kbytes of Flash memory 8 kbytes of SRAM 51 GPIOs 1.8 to 3.6 V application supply

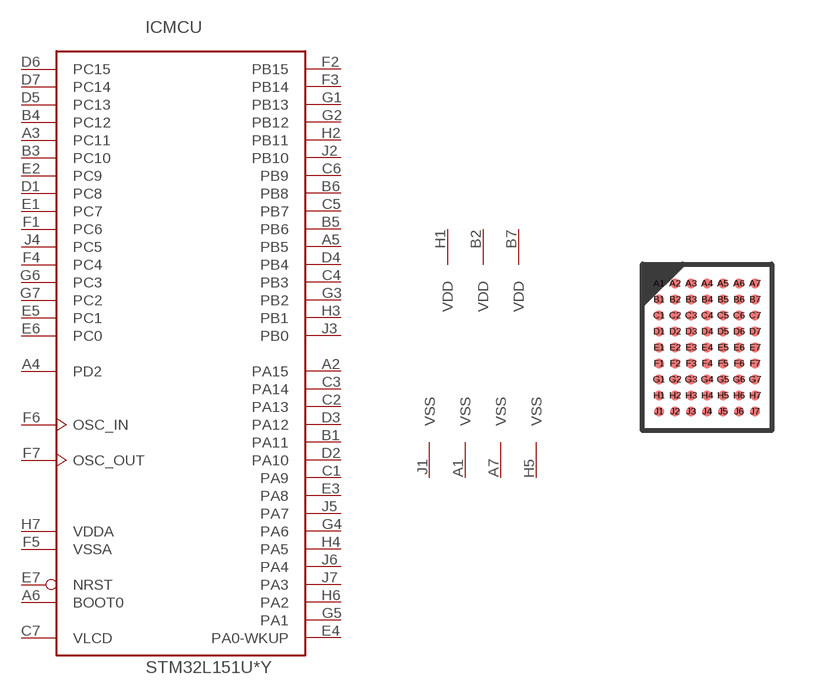
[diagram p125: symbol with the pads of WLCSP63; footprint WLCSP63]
Designator prefix IC; gates MCU=STM32_63PIN_TYP1 PWR=PWR_VDD3_VSS4

## STM32L151UCY  [WLCSP63]
A1  PWR:VSS  pwr
A2  MCU:PA15
A3  MCU:PC11
A4  MCU:PD2
A5  MCU:PB5
A6  MCU:BOOT0  in
A7  PWR:VSS  pwr
B1  MCU:PA11
B2  PWR:VDD  pwr
B3  MCU:PC10
B4  MCU:PC12
B5  MCU:PB6
B6  MCU:PB8
B7  PWR:VDD  pwr
C1  MCU:PA9
C2  MCU:PA13
C3  MCU:PA14
C4  MCU:PB3
C5  MCU:PB7
C6  MCU:PB9
C7  MCU:VLCD  pwr
D1  MCU:PC8
D2  MCU:PA10
D3  MCU:PA12
D4  MCU:PB4
D5  MCU:PC13
D6  MCU:PC15
D7  MCU:PC14
E1  MCU:PC7
E2  MCU:PC9
E3  MCU:PA8
E4  MCU:PA0-WKUP
E5  MCU:PC1
E6  MCU:PC0
E7  MCU:NRST
F1  MCU:PC6
F2  MCU:PB15
F3  MCU:PB14
F4  MCU:PC4
F5  MCU:VSSA  pwr
F6  MCU:OSC_IN
F7  MCU:OSC_OUT
G1  MCU:PB13
G2  MCU:PB12
G3  MCU:PB2
G4  MCU:PA6
G5  MCU:PA1
G6  MCU:PC3
G7  MCU:PC2
H1  PWR:VDD  pwr
H2  MCU:PB11
H3  MCU:PB1
H4  MCU:PA5
H5  PWR:VSS  pwr
H6  MCU:PA2
H7  MCU:VDDA  pwr
J1  PWR:VSS  pwr
J2  MCU:PB10
J3  MCU:PB0
J4  MCU:PC5
J5  MCU:PA7
J6  MCU:PA4
J7  MCU:PA3

## Footprint WLCSP63 (pad centres in mm)
WLCSP63 3.228 x 4.164 mm, 7 x 9-pin 0.4 mm pitch wafer-level chip-scale package
smd 0.25 x 0.25: A1 -1.2,1.6; A2 -0.8,1.6; A3 -0.4,1.6; A4 0,1.6; A5 0.4,1.6; A6 0.8,1.6; A7 1.2,1.6; B1 -1.2,1.2; B2 -0.8,1.2; B3 -0.4,1.2; B4 0,1.2; B5 0.4,1.2; B6 0.8,1.2; B7 1.2,1.2; C1 -1.2,0.8; C2 -0.8,0.8; C3 -0.4,0.8; C4 0,0.8; C5 0.4,0.8; C6 0.8,0.8; C7 1.2,0.8; D1 -1.2,0.4; D2 -0.8,0.4; D3 -0.4,0.4; D4 0,0.4; D5 0.4,0.4; D6 0.8,0.4; D7 1.2,0.4; E1 -1.2,0; E2 -0.8,0; E3 -0.4,0; E4 0,0; E5 0.4,0; E6 0.8,0; E7 1.2,0; F1 -1.2,-0.4; F2 -0.8,-0.4; F3 -0.4,-0.4; F4 0,-0.4; F5 0.4,-0.4; F6 0.8,-0.4; F7 1.2,-0.4; G1 -1.2,-0.8; G2 -0.8,-0.8; G3 -0.4,-0.8; G4 0,-0.8; G5 0.4,-0.8; G6 0.8,-0.8; G7 1.2,-0.8; H1 -1.2,-1.2; H2 -0.8,-1.2; H3 -0.4,-1.2; H4 0,-1.2; H5 0.4,-1.2; H6 0.8,-1.2; H7 1.2,-1.2; J1 -1.2,-1.6; J2 -0.8,-1.6; J3 -0.4,-1.6; J4 0,-1.6; J5 0.4,-1.6; J6 0.8,-1.6; J7 1.2,-1.6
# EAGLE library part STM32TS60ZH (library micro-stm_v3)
ARM 32-bit Cortex™-M3 CPU 72 MHz maximum frequency 32 Kbytes of Flash memory 10 kbytes of SRAM 138 GPIOs 2.4 to 3.6 V application supply

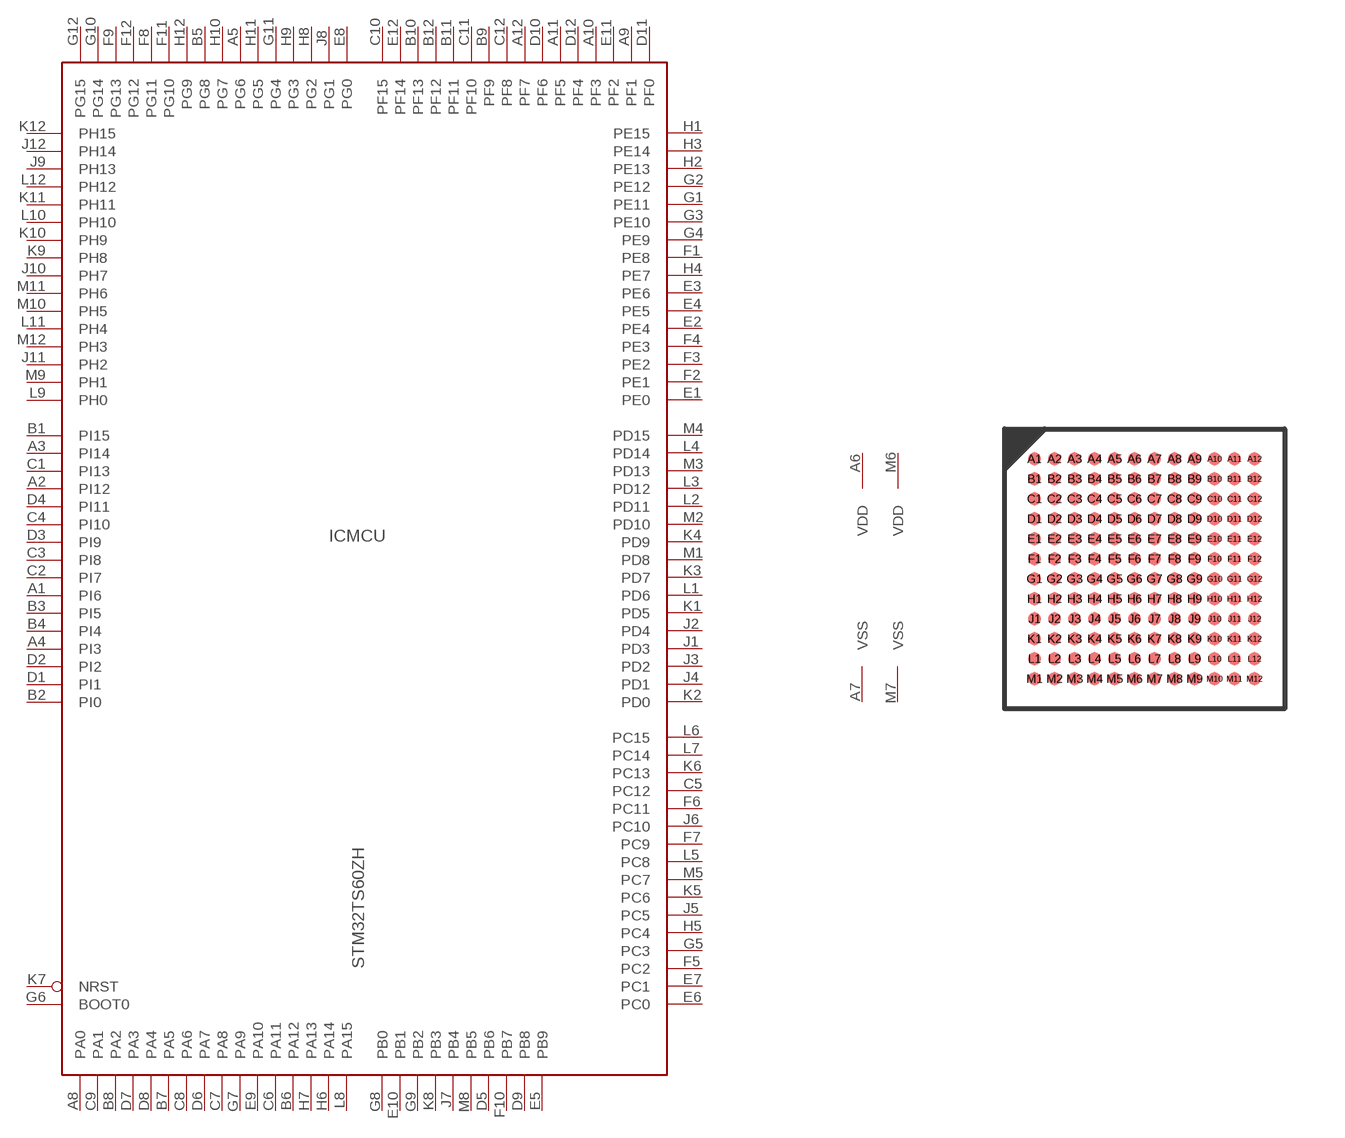
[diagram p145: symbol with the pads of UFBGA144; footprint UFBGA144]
Designator prefix IC; gates MCU=STM32_144PIN_TYP5 PWR=PWR_VDD2_VSS2

## STM32TS60ZH  [UFBGA144]
A1  MCU:PI6
A2  MCU:PI12
A3  MCU:PI14
A4  MCU:PI3
A5  MCU:PG6
A6  PWR:VDD  pwr
A7  PWR:VSS  pwr
A8  MCU:PA0
A9  MCU:PF1
A10  MCU:PF3
A11  MCU:PF5
A12  MCU:PF7
B1  MCU:PI15
B2  MCU:PI0
B3  MCU:PI5
B4  MCU:PI4
B5  MCU:PG8
B6  MCU:PA12
B7  MCU:PA5
B8  MCU:PA2
B9  MCU:PF9
B10  MCU:PF13
B11  MCU:PF11
B12  MCU:PF12
C1  MCU:PI13
C2  MCU:PI7
C3  MCU:PI8
C4  MCU:PI10
C5  MCU:PC12
C6  MCU:PA11
C7  MCU:PA8
C8  MCU:PA6
C9  MCU:PA1
C10  MCU:PF15
C11  MCU:PF10
C12  MCU:PF8
D1  MCU:PI1
D2  MCU:PI2
D3  MCU:PI9
D4  MCU:PI11
D5  MCU:PB6
D6  MCU:PA7
D7  MCU:PA3
D8  MCU:PA4
D9  MCU:PB8
D10  MCU:PF6
D11  MCU:PF0
D12  MCU:PF4
E1  MCU:PE0
E2  MCU:PE4
E3  MCU:PE6
E4  MCU:PE5
E5  MCU:PB9
E6  MCU:PC0
E7  MCU:PC1
E8  MCU:PG0
E9  MCU:PA10
E10  MCU:PB1
E11  MCU:PF2
E12  MCU:PF14
F1  MCU:PE8
F2  MCU:PE1
F3  MCU:PE2
F4  MCU:PE3
F5  MCU:PC2
F6  MCU:PC11
F7  MCU:PC9
F8  MCU:PG11
F9  MCU:PG13
F10  MCU:PB7
F11  MCU:PG10
F12  MCU:PG12
G1  MCU:PE11
G2  MCU:PE12
G3  MCU:PE10
G4  MCU:PE9
G5  MCU:PC3
G6  MCU:BOOT0  in
G7  MCU:PA9
G8  MCU:PB0
G9  MCU:PB2
G10  MCU:PG14
G11  MCU:PG4
G12  MCU:PG15
H1  MCU:PE15
H2  MCU:PE13
H3  MCU:PE14
H4  MCU:PE7
H5  MCU:PC4
H6  MCU:PA14
H7  MCU:PA13
H8  MCU:PG2
H9  MCU:PG3
H10  MCU:PG7
H11  MCU:PG5
H12  MCU:PG9
J1  MCU:PD3
J2  MCU:PD4
J3  MCU:PD2
J4  MCU:PD1
J5  MCU:PC5
J6  MCU:PC10
J7  MCU:PB4
J8  MCU:PG1
J9  MCU:PH13
J10  MCU:PH7
J11  MCU:PH2
J12  MCU:PH14
K1  MCU:PD5
K2  MCU:PD0
K3  MCU:PD7
K4  MCU:PD9
K5  MCU:PC6
K6  MCU:PC13
K7  MCU:NRST
K8  MCU:PB3
K9  MCU:PH8
K10  MCU:PH9
K11  MCU:PH11
K12  MCU:PH15
L1  MCU:PD6
L2  MCU:PD11
L3  MCU:PD12
L4  MCU:PD14
L5  MCU:PC8
L6  MCU:PC15
L7  MCU:PC14
L8  MCU:PA15
L9  MCU:PH0
L10  MCU:PH10
L11  MCU:PH4
L12  MCU:PH12
M1  MCU:PD8
M2  MCU:PD10
M3  MCU:PD13
M4  MCU:PD15
M5  MCU:PC7
M6  PWR:VDD  pwr
M7  PWR:VSS  pwr
M8  MCU:PB5
M9  MCU:PH1
M10  MCU:PH5
M11  MCU:PH6
M12  MCU:PH3

## Footprint UFBGA144 (pad centres in mm)
UFBGA144 7 x 7 mm, 12 x 12-pin ultra fine 0.5 mm pitch ball grid array package
smd 0.32 x 0.32: A1 -2.75,2.75; A2 -2.25,2.75; A3 -1.75,2.75; A4 -1.25,2.75; A5 -0.75,2.75; A6 -0.25,2.75; A7 0.25,2.75; A8 0.75,2.75; A9 1.25,2.75; A10 1.75,2.75; A11 2.25,2.75; A12 2.75,2.75; B1 -2.75,2.25; B2 -2.25,2.25; B3 -1.75,2.25; B4 -1.25,2.25; B5 -0.75,2.25; B6 -0.25,2.25; B7 0.25,2.25; B8 0.75,2.25; B9 1.25,2.25; B10 1.75,2.25; B11 2.25,2.25; B12 2.75,2.25; C1 -2.75,1.75; C2 -2.25,1.75; C3 -1.75,1.75; C4 -1.25,1.75; C5 -0.75,1.75; C6 -0.25,1.75; C7 0.25,1.75; C8 0.75,1.75; C9 1.25,1.75; C10 1.75,1.75; C11 2.25,1.75; C12 2.75,1.75; D1 -2.75,1.25; D2 -2.25,1.25; D3 -1.75,1.25; D4 -1.25,1.25; D5 -0.75,1.25; D6 -0.25,1.25; D7 0.25,1.25; D8 0.75,1.25; D9 1.25,1.25; D10 1.75,1.25; D11 2.25,1.25; D12 2.75,1.25; E1 -2.75,0.75; E2 -2.25,0.75; E3 -1.75,0.75; E4 -1.25,0.75; E5 -0.75,0.75; E6 -0.25,0.75; E7 0.25,0.75; E8 0.75,0.75; E9 1.25,0.75; E10 1.75,0.75; E11 2.25,0.75; E12 2.75,0.75; F1 -2.75,0.25; F2 -2.25,0.25; F3 -1.75,0.25; F4 -1.25,0.25; F5 -0.75,0.25; F6 -0.25,0.25; F7 0.25,0.25; F8 0.75,0.25; F9 1.25,0.25; F10 1.75,0.25; F11 2.25,0.25; F12 2.75,0.25; G1 -2.75,-0.25; G2 -2.25,-0.25; G3 -1.75,-0.25; G4 -1.25,-0.25; G5 -0.75,-0.25; G6 -0.25,-0.25; G7 0.25,-0.25; G8 0.75,-0.25; G9 1.25,-0.25; G10 1.75,-0.25; G11 2.25,-0.25; G12 2.75,-0.25; H1 -2.75,-0.75; H2 -2.25,-0.75; H3 -1.75,-0.75; H4 -1.25,-0.75; H5 -0.75,-0.75; H6 -0.25,-0.75; H7 0.25,-0.75; H8 0.75,-0.75; H9 1.25,-0.75; H10 1.75,-0.75; H11 2.25,-0.75; H12 2.75,-0.75; J1 -2.75,-1.25; J2 -2.25,-1.25; J3 -1.75,-1.25; J4 -1.25,-1.25; J5 -0.75,-1.25; J6 -0.25,-1.25; J7 0.25,-1.25; J8 0.75,-1.25; J9 1.25,-1.25; J10 1.75,-1.25; J11 2.25,-1.25; J12 2.75,-1.25; K1 -2.75,-1.75; K2 -2.25,-1.75; K3 -1.75,-1.75; K4 -1.25,-1.75; K5 -0.75,-1.75; K6 -0.25,-1.75; K7 0.25,-1.75; K8 0.75,-1.75; K9 1.25,-1.75; K10 1.75,-1.75; K11 2.25,-1.75; K12 2.75,-1.75; L1 -2.75,-2.25; L2 -2.25,-2.25; L3 -1.75,-2.25; L4 -1.25,-2.25; L5 -0.75,-2.25; L6 -0.25,-2.25; L7 0.25,-2.25; L8 0.75,-2.25; L9 1.25,-2.25; L10 1.75,-2.25; L11 2.25,-2.25; L12 2.75,-2.25; M1 -2.75,-2.75; M2 -2.25,-2.75; M3 -1.75,-2.75; M4 -1.25,-2.75; M5 -0.75,-2.75; M6 -0.25,-2.75; M7 0.25,-2.75; M8 0.75,-2.75; M9 1.25,-2.75; M10 1.75,-2.75; M11 2.25,-2.75; M12 2.75,-2.75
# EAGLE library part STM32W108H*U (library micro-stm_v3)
ARM 32-bit Cortex™-M3 CPU 24 MHz maximum frequency 128 Kbytes of Flash memory 8 kbytes of SRAM 2.1 to 3.6 V application supply

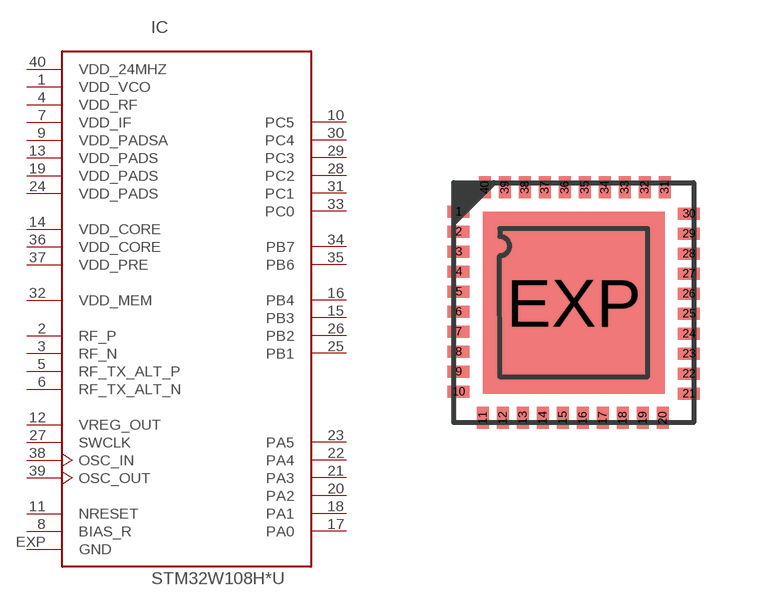
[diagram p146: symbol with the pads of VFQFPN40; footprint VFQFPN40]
Designator prefix IC

## STM32W108HBU  [VFQFPN40]
1  VDD_VCO  pwr
2  RF_P
3  RF_N
4  VDD_RF  pwr
5  RF_TX_ALT_P  out
6  RF_TX_ALT_N  out
7  VDD_IF  pwr
8  BIAS_R  in
9  VDD_PADSA  pwr
10  PC5
11  NRESET  in
12  VREG_OUT  pwr
13  VDD_PADS  pwr
14  VDD_CORE  pwr
15  PB3
16  PB4
17  PA0
18  PA1
19  VDD_PADS  pwr
20  PA2
21  PA3
22  PA4
23  PA5
24  VDD_PADS  pwr
25  PB1
26  PB2
27  SWCLK
28  PC2
29  PC3
30  PC4
31  PC1
32  VDD_MEM  pwr
33  PC0
34  PB7
35  PB6
36  VDD_CORE  pwr
37  VDD_PRE  pwr
38  OSC_IN
39  OSC_OUT
40  VDD_24MHZ  pwr
EXP  GND  pwr

## Footprint VFQFPN40 (pad centres in mm)
VFQFPN40 6 x 6 mm, 40-pin very thin 0.5 mm pitch quad flat no-lead package
smd 0.55 x 0.3: 1 -2.88,2.275; 2 -2.88,1.775; 3 -2.88,1.275; 4 -2.88,0.775; 5 -2.88,0.275; 6 -2.88,-0.225; 7 -2.88,-0.725; 8 -2.88,-1.225; 9 -2.88,-1.725; 10 -2.88,-2.225; 21 2.88,-2.275; 22 2.88,-1.775; 23 2.88,-1.275; 24 2.88,-0.775; 25 2.88,-0.275; 26 2.88,0.225; 27 2.88,0.725; 28 2.88,1.225; 29 2.88,1.725; 30 2.88,2.225
smd 0.3 x 0.55: 11 -2.275,-2.88; 12 -1.775,-2.88; 13 -1.275,-2.88; 14 -0.775,-2.88; 15 -0.275,-2.88; 16 0.225,-2.88; 17 0.725,-2.88; 18 1.225,-2.88; 19 1.725,-2.88; 20 2.225,-2.88; 31 2.275,2.88; 32 1.775,2.88; 33 1.275,2.88; 34 0.775,2.88; 35 0.275,2.88; 36 -0.225,2.88; 37 -0.725,2.88; 38 -1.225,2.88; 39 -1.725,2.88; 40 -2.225,2.88
smd 4.55 x 4.55: EXP 0,0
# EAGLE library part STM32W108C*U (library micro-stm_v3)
ARM 32-bit Cortex™-M3 CPU 24 MHz maximum frequency 128 to 192 Kbytes of Flash memory 8 to 16 kbytes of SRAM 2.1 to 3.6 V application supply

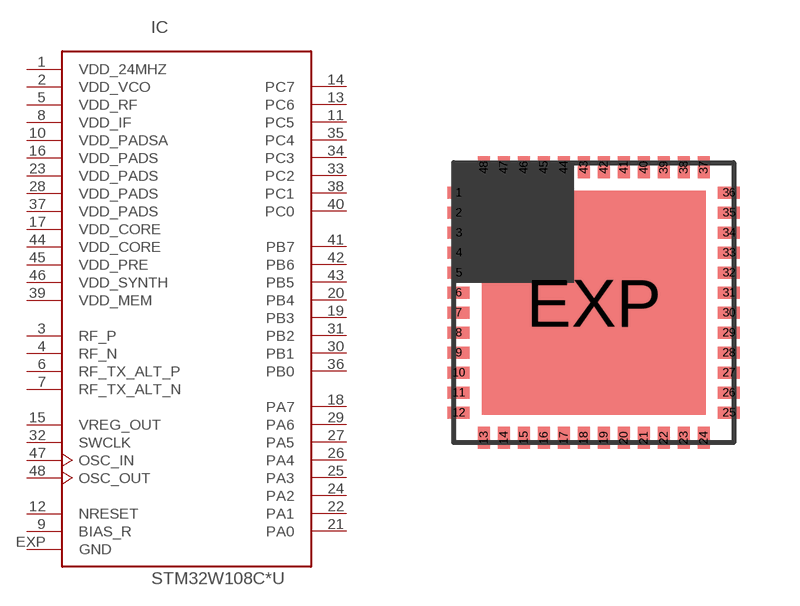
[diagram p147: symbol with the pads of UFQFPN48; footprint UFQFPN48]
Designator prefix IC

## STM32W108C8U, STM32W108CBU, STM32W108CCU, STM32W108CZU  [UFQFPN48]
1  VDD_24MHZ  pwr
2  VDD_VCO  pwr
3  RF_P
4  RF_N
5  VDD_RF  pwr
6  RF_TX_ALT_P  out
7  RF_TX_ALT_N  out
8  VDD_IF  pwr
9  BIAS_R  in
10  VDD_PADSA  pwr
11  PC5
12  NRESET  in
13  PC6
14  PC7
15  VREG_OUT  pwr
16  VDD_PADS  pwr
17  VDD_CORE  pwr
18  PA7
19  PB3
20  PB4
21  PA0
22  PA1
23  VDD_PADS  pwr
24  PA2
25  PA3
26  PA4
27  PA5
28  VDD_PADS  pwr
29  PA6
30  PB1
31  PB2
32  SWCLK
33  PC2
34  PC3
35  PC4
36  PB0
37  VDD_PADS  pwr
38  PC1
39  VDD_MEM  pwr
40  PC0
41  PB7
42  PB6
43  PB5
44  VDD_CORE  pwr
45  VDD_PRE  pwr
46  VDD_SYNTH  pwr
47  OSC_IN
48  OSC_OUT
EXP  GND  pwr

## Footprint UFQFPN48 (pad centres in mm)
UFQFPN48 7 x 7 mm, 48-pin ultra thin 0.5 mm pitch quad flat no-lead package
smd 0.55 x 0.3: 1 -3.38,2.75; 2 -3.38,2.25; 3 -3.38,1.75; 4 -3.38,1.25; 5 -3.38,0.75; 6 -3.38,0.25; 7 -3.38,-0.25; 8 -3.38,-0.75; 9 -3.38,-1.25; 10 -3.38,-1.75; 11 -3.38,-2.25; 12 -3.38,-2.75; 25 3.38,-2.75; 26 3.38,-2.25; 27 3.38,-1.75; 28 3.38,-1.25; 29 3.38,-0.75; 30 3.38,-0.25; 31 3.38,0.25; 32 3.38,0.75; 33 3.38,1.25; 34 3.38,1.75; 35 3.38,2.25; 36 3.38,2.75
smd 0.3 x 0.55: 13 -2.75,-3.38; 14 -2.25,-3.38; 15 -1.75,-3.38; 16 -1.25,-3.38; 17 -0.75,-3.38; 18 -0.25,-3.38; 19 0.25,-3.38; 20 0.75,-3.38; 21 1.25,-3.38; 22 1.75,-3.38; 23 2.25,-3.38; 24 2.75,-3.38; 37 2.75,3.38; 38 2.25,3.38; 39 1.75,3.38; 40 1.25,3.38; 41 0.75,3.38; 42 0.25,3.38; 43 -0.25,3.38; 44 -0.75,3.38; 45 -1.25,3.38; 46 -1.75,3.38; 47 -2.25,3.38; 48 -2.75,3.38
smd 5.6 x 5.6: EXP 0,0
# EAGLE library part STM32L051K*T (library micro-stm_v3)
ARM 32-bit Cortex™-M0+ CPU 32 MHz maximum frequency 32 to 64 Kbytes of Flash memory 2 kbyte of Data EEPROM 8 kbytes of SRAM 27 GPIOs 1.8 to 3.6 V application supply

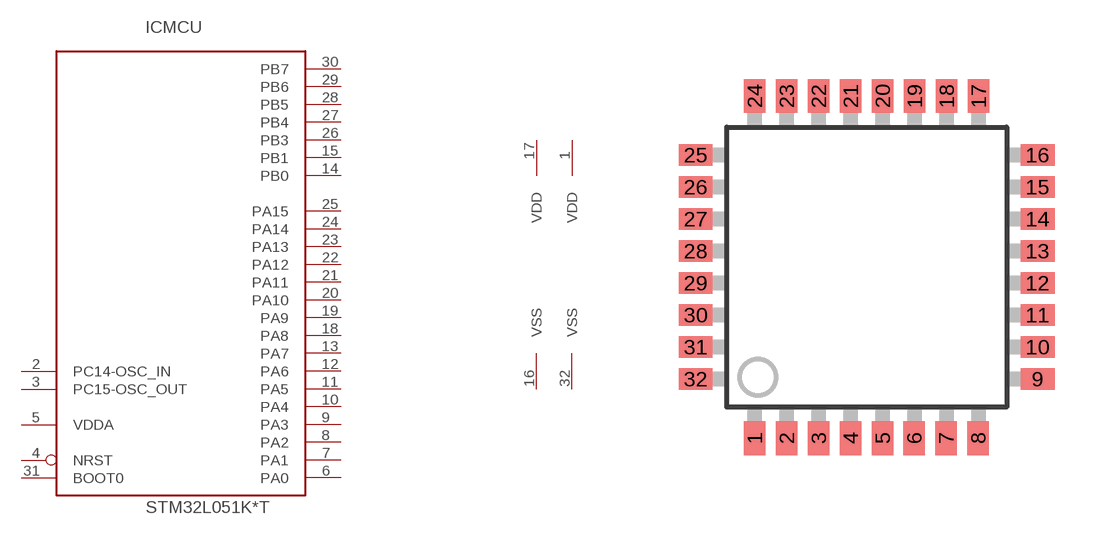
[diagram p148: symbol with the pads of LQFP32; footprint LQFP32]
Designator prefix IC; gates MCU=STM32_32PIN_TYP4 PWR=PWR_VDD2_VSS2

## STM32L051K6T, STM32L051K8T  [LQFP32]
1  PWR:VDD  pwr
2  MCU:PC14-OSC_IN
3  MCU:PC15-OSC_OUT
4  MCU:NRST
5  MCU:VDDA  pwr
6  MCU:PA0
7  MCU:PA1
8  MCU:PA2
9  MCU:PA3
10  MCU:PA4
11  MCU:PA5
12  MCU:PA6
13  MCU:PA7
14  MCU:PB0
15  MCU:PB1
16  PWR:VSS  pwr
17  PWR:VDD  pwr
18  MCU:PA8
19  MCU:PA9
20  MCU:PA10
21  MCU:PA11
22  MCU:PA12
23  MCU:PA13
24  MCU:PA14
25  MCU:PA15
26  MCU:PB3
27  MCU:PB4
28  MCU:PB5
29  MCU:PB6
30  MCU:PB7
31  MCU:BOOT0  in
32  PWR:VSS  pwr

## Footprint LQFP32 (pad centres in mm)
LQFP32 7 x 7 mm, 32-pin low-profile quad flat package
smd 0.54 x 0.85: 1 -2.8,-4.275; 2 -2,-4.275; 3 -1.2,-4.275; 4 -0.4,-4.275; 5 0.4,-4.275; 6 1.19,-4.275; 7 1.99,-4.275; 8 2.79,-4.275; 17 2.8,4.275; 18 2,4.275; 19 1.2,4.275; 20 0.4,4.275; 21 -0.4,4.275; 22 -1.2,4.275; 23 -2,4.275; 24 -2.8,4.275
smd 0.85 x 0.54: 9 4.275,-2.8; 10 4.275,-2; 11 4.275,-1.2; 12 4.275,-0.4; 13 4.275,0.4; 14 4.275,1.2; 15 4.275,2; 16 4.275,2.8; 25 -4.275,2.8; 26 -4.275,2; 27 -4.275,1.2; 28 -4.275,0.4; 29 -4.275,-0.4; 30 -4.275,-1.2; 31 -4.275,-2; 32 -4.275,-2.8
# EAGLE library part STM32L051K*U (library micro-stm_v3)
ARM 32-bit Cortex™-M0+ CPU 32 MHz maximum frequency 32 to 64 Kbytes of Flash memory 2 kbyte of Data EEPROM 8 kbytes of SRAM 27 GPIOs 1.8 to 3.6 V application supply

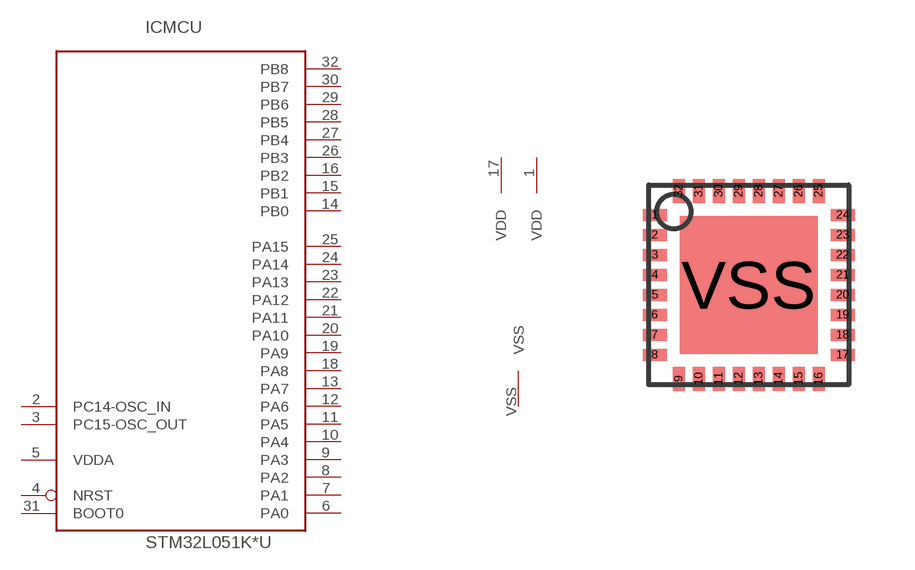
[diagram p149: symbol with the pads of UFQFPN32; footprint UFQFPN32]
Designator prefix IC; gates MCU=STM32_32PIN_TYP3 PWR=PWR_VDD2_VSS1

## STM32L051K6U, STM32L051K8U  [UFQFPN32]
1  PWR:VDD  pwr
2  MCU:PC14-OSC_IN
3  MCU:PC15-OSC_OUT
4  MCU:NRST
5  MCU:VDDA  pwr
6  MCU:PA0
7  MCU:PA1
8  MCU:PA2
9  MCU:PA3
10  MCU:PA4
11  MCU:PA5
12  MCU:PA6
13  MCU:PA7
14  MCU:PB0
15  MCU:PB1
16  MCU:PB2
17  PWR:VDD  pwr
18  MCU:PA8
19  MCU:PA9
20  MCU:PA10
21  MCU:PA11
22  MCU:PA12
23  MCU:PA13
24  MCU:PA14
25  MCU:PA15
26  MCU:PB3
27  MCU:PB4
28  MCU:PB5
29  MCU:PB6
30  MCU:PB7
31  MCU:BOOT0  in
32  MCU:PB8
VSS  PWR:VSS  pwr

## Footprint UFQFPN32 (pad centres in mm)
UFQFPN32 5 x 5 mm, 32-pin ultra thin fine pitch quad flat no-lead package
smd 0.6 x 0.3: 1 -2.35,1.75; 2 -2.35,1.25; 3 -2.35,0.75; 4 -2.35,0.25; 5 -2.35,-0.25; 6 -2.35,-0.75; 7 -2.35,-1.25; 8 -2.35,-1.75; 17 2.35,-1.75; 18 2.35,-1.25; 19 2.35,-0.75; 20 2.35,-0.25; 21 2.35,0.25; 22 2.35,0.75; 23 2.35,1.25; 24 2.35,1.75
smd 0.3 x 0.6: 9 -1.75,-2.35; 10 -1.25,-2.35; 11 -0.75,-2.35; 12 -0.25,-2.35; 13 0.25,-2.35; 14 0.75,-2.35; 15 1.25,-2.35; 16 1.75,-2.35; 25 1.75,2.35; 26 1.25,2.35; 27 0.75,2.35; 28 0.25,2.35; 29 -0.25,2.35; 30 -0.75,2.35; 31 -1.25,2.35; 32 -1.75,2.35
smd 3.45 x 3.45: VSS 0,0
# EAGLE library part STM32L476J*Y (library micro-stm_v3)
ARM 32-bit Cortex™-M4 CPU 80 MHz maximum frequency 512..1024 Kbytes of Flash memory 128 kbytes of SRAM 57 GPIOs 1.71 to 3.6 V application supply

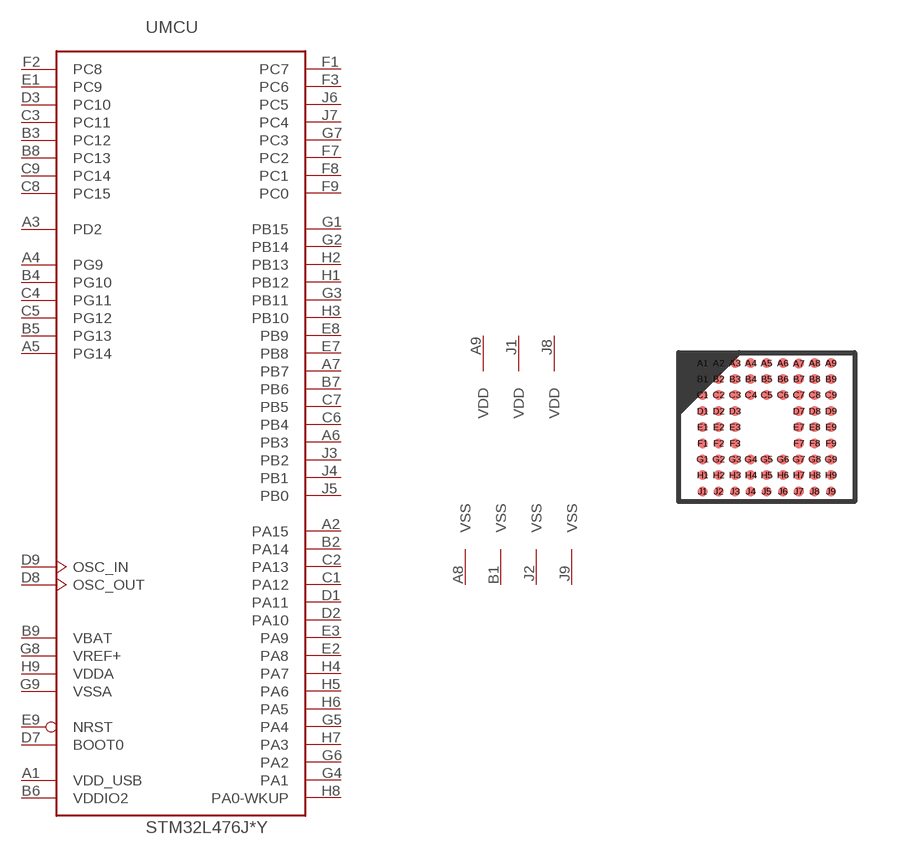
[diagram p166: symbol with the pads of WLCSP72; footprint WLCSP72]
Designator prefix -; gates MCU=STM32_72PIN_TYP1 PWR=PWR_VDD3_VSS4

## STM32L476JEY, STM32L476JGY  [WLCSP72]
A1  MCU:VDD_USB  pwr
A2  MCU:PA15
A3  MCU:PD2
A4  MCU:PG9
A5  MCU:PG14
A6  MCU:PB3
A7  MCU:PB7
A8  PWR:VSS  pwr
A9  PWR:VDD  pwr
B1  PWR:VSS  pwr
B2  MCU:PA14
B3  MCU:PC12
B4  MCU:PG10
B5  MCU:PG13
B6  MCU:VDDIO2  pwr
B7  MCU:PB6
B8  MCU:PC13
B9  MCU:VBAT  pwr
C1  MCU:PA12
C2  MCU:PA13
C3  MCU:PC11
C4  MCU:PG11
C5  MCU:PG12
C6  MCU:PB4
C7  MCU:PB5
C8  MCU:PC15
C9  MCU:PC14
D1  MCU:PA11
D2  MCU:PA10
D3  MCU:PC10
D7  MCU:BOOT0  in
D8  MCU:OSC_OUT
D9  MCU:OSC_IN
E1  MCU:PC9
E2  MCU:PA8
E3  MCU:PA9
E7  MCU:PB8
E8  MCU:PB9
E9  MCU:NRST
F1  MCU:PC7
F2  MCU:PC8
F3  MCU:PC6
F7  MCU:PC2
F8  MCU:PC1
F9  MCU:PC0
G1  MCU:PB15
G2  MCU:PB14
G3  MCU:PB11
G4  MCU:PA1
G5  MCU:PA4
G6  MCU:PA2
G7  MCU:PC3
G8  MCU:VREF+  pwr
G9  MCU:VSSA  pwr
H1  MCU:PB12
H2  MCU:PB13
H3  MCU:PB10
H4  MCU:PA7
H5  MCU:PA6
H6  MCU:PA5
H7  MCU:PA3
H8  MCU:PA0-WKUP
H9  MCU:VDDA  pwr
J1  PWR:VDD  pwr
J2  PWR:VSS  pwr
J3  MCU:PB2
J4  MCU:PB1
J5  MCU:PB0
J6  MCU:PC5
J7  MCU:PC4
J8  PWR:VDD  pwr
J9  PWR:VSS  pwr

## Footprint WLCSP72 (pad centres in mm)
WLCSP72 4,4084 x 3,7594 mm, 9 x 9-pin 0.4 mm pitch wafer-level chip-scale package
smd 0.25 x 0.25: A1 -1.597,1.597; A2 -1.201,1.597; A3 -0.794,1.597; A4 -0.397,1.597; A5 0,1.597; A6 0.407,1.597; A7 0.804,1.588; A8 1.201,1.597; A9 1.607,1.597; B1 -1.597,1.201; B2 -1.201,1.201; B3 -0.794,1.201; B4 -0.397,1.201; B5 0,1.201; B6 0.407,1.201; B7 0.804,1.201; B8 1.201,1.201; B9 1.607,1.201; C1 -1.597,0.804; C2 -1.201,0.804; C3 -0.794,0.804; C4 -0.397,0.804; C5 0,0.804; C6 0.407,0.804; C7 0.804,0.804; C8 1.201,0.804; C9 1.607,0.804; D1 -1.597,0.397; D2 -1.201,0.397; D3 -0.794,0.397; D7 0.804,0.397; D8 1.201,0.397; D9 1.607,0.397; E1 -1.597,0; E2 -1.201,0; E3 -0.794,0; E7 0.804,0; E8 1.201,0; E9 1.607,0; F1 -1.597,-0.407; F2 -1.201,-0.407; F3 -0.794,-0.407; F7 0.804,-0.407; F8 1.201,-0.407; F9 1.607,-0.407; G1 -1.597,-0.804; G2 -1.201,-0.804; G3 -0.794,-0.804; G4 -0.397,-0.804; G5 0,-0.804; G6 0.407,-0.804; G7 0.804,-0.804; G8 1.201,-0.804; G9 1.607,-0.804; H1 -1.597,-1.201; H2 -1.201,-1.201; H3 -0.794,-1.201; H4 -0.397,-1.201; H5 0,-1.201; H6 0.407,-1.201; H7 0.804,-1.201; H8 1.201,-1.201; H9 1.607,-1.201; J1 -1.597,-1.607; J2 -1.201,-1.607; J3 -0.794,-1.607; J4 -0.397,-1.607; J5 0,-1.607; J6 0.407,-1.607; J7 0.804,-1.607; J8 1.201,-1.607; J9 1.607,-1.607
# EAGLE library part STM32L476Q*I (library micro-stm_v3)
ARM 32-bit Cortex™-M4 CPU 80 MHz maximum frequency 512..1024 Kbytes of Flash memory 128 kbytes of SRAM 109 GPIOs 1.71 to 3.6 V application supply

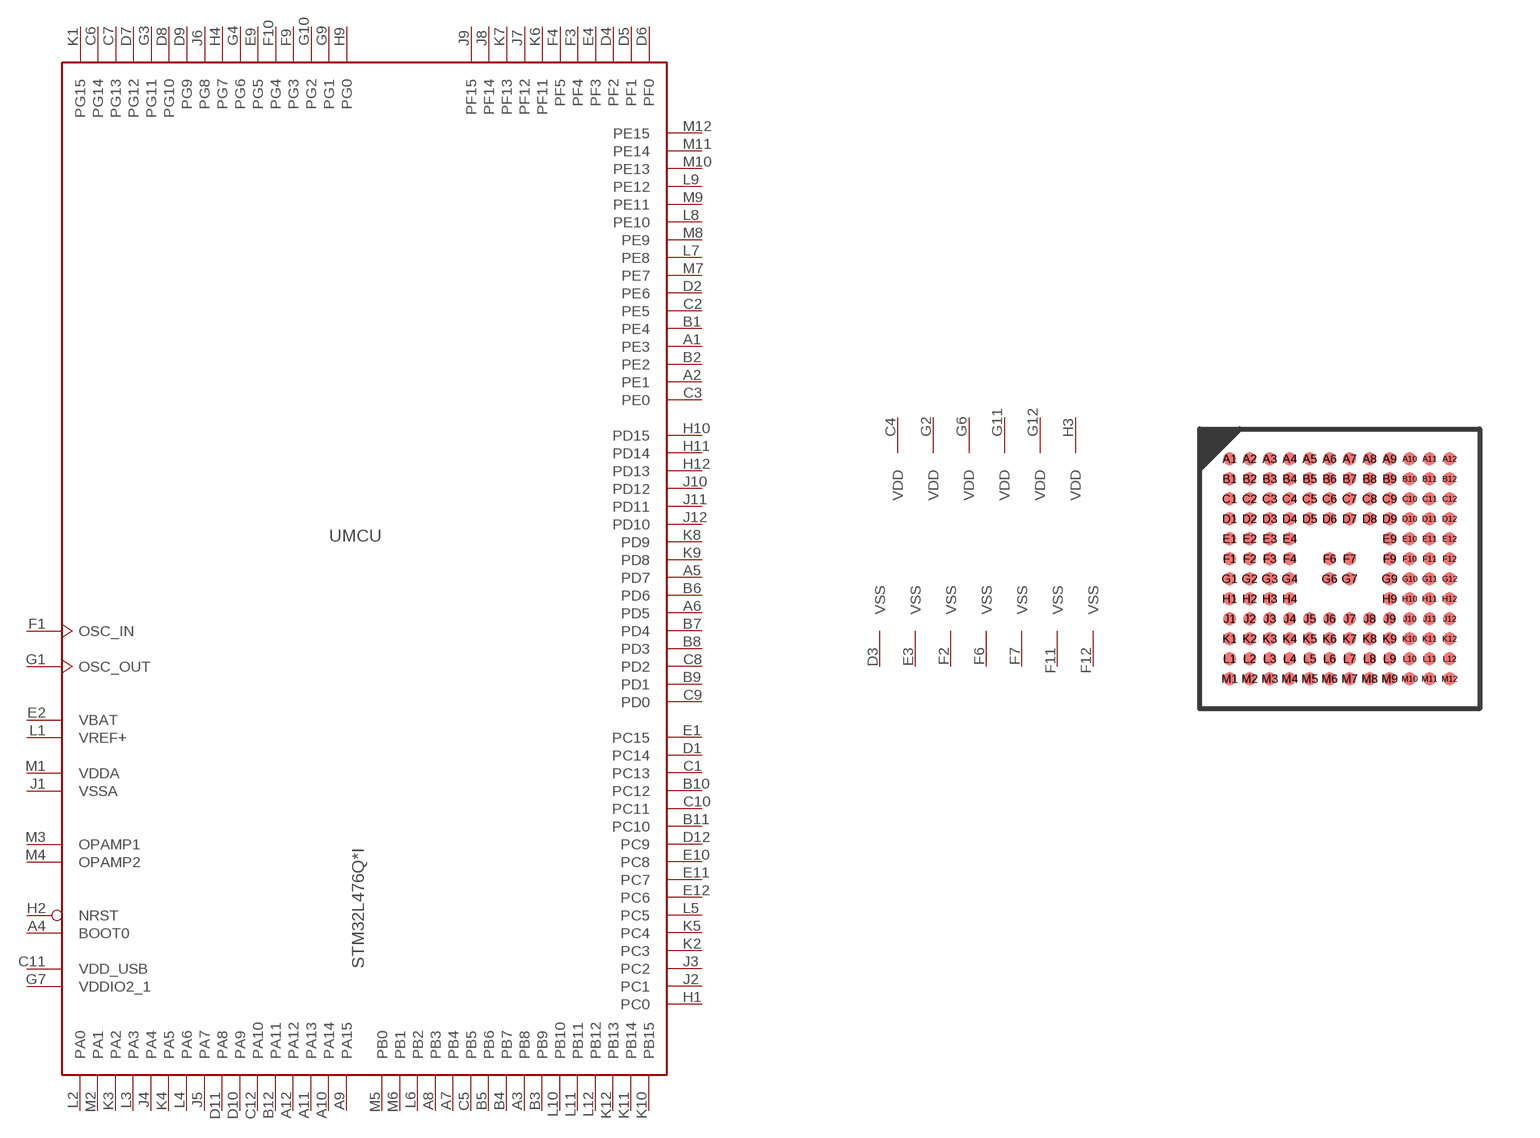
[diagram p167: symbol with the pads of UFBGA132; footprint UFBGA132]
Designator prefix -; gates MCU=STM32_132PIN_TYP2 PWR=PWR_VDD6_VSS7

## STM32L476QEI, STM32L476QGI  [UFBGA132]
A1  MCU:PE3
A2  MCU:PE1
A3  MCU:PB8
A4  MCU:BOOT0  in
A5  MCU:PD7
A6  MCU:PD5
A7  MCU:PB4
A8  MCU:PB3
A9  MCU:PA15
A10  MCU:PA14
A11  MCU:PA13
A12  MCU:PA12
B1  MCU:PE4
B2  MCU:PE2
B3  MCU:PB9
B4  MCU:PB7
B5  MCU:PB6
B6  MCU:PD6
B7  MCU:PD4
B8  MCU:PD3
B9  MCU:PD1
B10  MCU:PC12
B11  MCU:PC10
B12  MCU:PA11
C1  MCU:PC13
C2  MCU:PE5
C3  MCU:PE0
C4  PWR:VDD  pwr
C5  MCU:PB5
C6  MCU:PG14
C7  MCU:PG13
C8  MCU:PD2
C9  MCU:PD0
C10  MCU:PC11
C11  MCU:VDD_USB
C12  MCU:PA10
D1  MCU:PC14
D2  MCU:PE6
D3  PWR:VSS  pwr
D4  MCU:PF2
D5  MCU:PF1
D6  MCU:PF0
D7  MCU:PG12
D8  MCU:PG10
D9  MCU:PG9
D10  MCU:PA9
D11  MCU:PA8
D12  MCU:PC9
E1  MCU:PC15
E2  MCU:VBAT  pwr
E3  PWR:VSS  pwr
E4  MCU:PF3
E9  MCU:PG5
E10  MCU:PC8
E11  MCU:PC7
E12  MCU:PC6
F1  MCU:OSC_IN
F2  PWR:VSS  pwr
F3  MCU:PF4
F4  MCU:PF5
F6  PWR:VSS  pwr
F7  PWR:VSS  pwr
F9  MCU:PG3
F10  MCU:PG4
F11  PWR:VSS  pwr
F12  PWR:VSS  pwr
G1  MCU:OSC_OUT
G2  PWR:VDD  pwr
G3  MCU:PG11
G4  MCU:PG6
G6  PWR:VDD  pwr
G7  MCU:VDDIO2_1
G9  MCU:PG1
G10  MCU:PG2
G11  PWR:VDD  pwr
G12  PWR:VDD  pwr
H1  MCU:PC0
H2  MCU:NRST
H3  PWR:VDD  pwr
H4  MCU:PG7
H9  MCU:PG0
H10  MCU:PD15
H11  MCU:PD14
H12  MCU:PD13
J1  MCU:VSSA  pwr
J2  MCU:PC1
J3  MCU:PC2
J4  MCU:PA4
J5  MCU:PA7
J6  MCU:PG8
J7  MCU:PF12
J8  MCU:PF14
J9  MCU:PF15
J10  MCU:PD12
J11  MCU:PD11
J12  MCU:PD10
K1  MCU:PG15
K2  MCU:PC3
K3  MCU:PA2
K4  MCU:PA5
K5  MCU:PC4
K6  MCU:PF11
K7  MCU:PF13
K8  MCU:PD9
K9  MCU:PD8
K10  MCU:PB15
K11  MCU:PB14
K12  MCU:PB13
L1  MCU:VREF+  pwr
L2  MCU:PA0
L3  MCU:PA3
L4  MCU:PA6
L5  MCU:PC5
L6  MCU:PB2
L7  MCU:PE8
L8  MCU:PE10
L9  MCU:PE12
L10  MCU:PB10
L11  MCU:PB11
L12  MCU:PB12
M1  MCU:VDDA  pwr
M2  MCU:PA1
M3  MCU:OPAMP1
M4  MCU:OPAMP2
M5  MCU:PB0
M6  MCU:PB1
M7  MCU:PE7
M8  MCU:PE9
M9  MCU:PE11
M10  MCU:PE13
M11  MCU:PE14
M12  MCU:PE15

## Footprint UFBGA132 (pad centres in mm)
UFBGA132 7 x 7 mm, 12 x 12-pin ultra fine 0.5 mm pitch ball grid array package
smd 0.32 x 0.32: A1 -2.75,2.75; A2 -2.25,2.75; A3 -1.75,2.75; A4 -1.25,2.75; A5 -0.75,2.75; A6 -0.25,2.75; A7 0.25,2.75; A8 0.75,2.75; A9 1.25,2.75; A10 1.75,2.75; A11 2.25,2.75; A12 2.75,2.75; B1 -2.75,2.25; B2 -2.25,2.25; B3 -1.75,2.25; B4 -1.25,2.25; B5 -0.75,2.25; B6 -0.25,2.25; B7 0.25,2.25; B8 0.75,2.25; B9 1.25,2.25; B10 1.75,2.25; B11 2.25,2.25; B12 2.75,2.25; C1 -2.75,1.75; C2 -2.25,1.75; C3 -1.75,1.75; C4 -1.25,1.75; C5 -0.75,1.75; C6 -0.25,1.75; C7 0.25,1.75; C8 0.75,1.75; C9 1.25,1.75; C10 1.75,1.75; C11 2.25,1.75; C12 2.75,1.75; D1 -2.75,1.25; D2 -2.25,1.25; D3 -1.75,1.25; D4 -1.25,1.25; D5 -0.75,1.25; D6 -0.25,1.25; D7 0.25,1.25; D8 0.75,1.25; D9 1.25,1.25; D10 1.75,1.25; D11 2.25,1.25; D12 2.75,1.25; E1 -2.75,0.75; E2 -2.25,0.75; E3 -1.75,0.75; E4 -1.25,0.75; E9 1.25,0.75; E10 1.75,0.75; E11 2.25,0.75; E12 2.75,0.75; F1 -2.75,0.25; F2 -2.25,0.25; F3 -1.75,0.25; F4 -1.25,0.25; F6 -0.25,0.25; F7 0.25,0.25; F9 1.25,0.25; F10 1.75,0.25; F11 2.25,0.25; F12 2.75,0.25; G1 -2.75,-0.25; G2 -2.25,-0.25; G3 -1.75,-0.25; G4 -1.25,-0.25; G6 -0.25,-0.25; G7 0.25,-0.25; G9 1.25,-0.25; G10 1.75,-0.25; G11 2.25,-0.25; G12 2.75,-0.25; H1 -2.75,-0.75; H2 -2.25,-0.75; H3 -1.75,-0.75; H4 -1.25,-0.75; H9 1.25,-0.75; H10 1.75,-0.75; H11 2.25,-0.75; H12 2.75,-0.75; J1 -2.75,-1.25; J2 -2.25,-1.25; J3 -1.75,-1.25; J4 -1.25,-1.25; J5 -0.75,-1.25; J6 -0.25,-1.25; J7 0.25,-1.25; J8 0.75,-1.25; J9 1.25,-1.25; J10 1.75,-1.25; J11 2.25,-1.25; J12 2.75,-1.25; K1 -2.75,-1.75; K2 -2.25,-1.75; K3 -1.75,-1.75; K4 -1.25,-1.75; K5 -0.75,-1.75; K6 -0.25,-1.75; K7 0.25,-1.75; K8 0.75,-1.75; K9 1.25,-1.75; K10 1.75,-1.75; K11 2.25,-1.75; K12 2.75,-1.75; L1 -2.75,-2.25; L2 -2.25,-2.25; L3 -1.75,-2.25; L4 -1.25,-2.25; L5 -0.75,-2.25; L6 -0.25,-2.25; L7 0.25,-2.25; L8 0.75,-2.25; L9 1.25,-2.25; L10 1.75,-2.25; L11 2.25,-2.25; L12 2.75,-2.25; M1 -2.75,-2.75; M2 -2.25,-2.75; M3 -1.75,-2.75; M4 -1.25,-2.75; M5 -0.75,-2.75; M6 -0.25,-2.75; M7 0.25,-2.75; M8 0.75,-2.75; M9 1.25,-2.75; M10 1.75,-2.75; M11 2.25,-2.75; M12 2.75,-2.75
